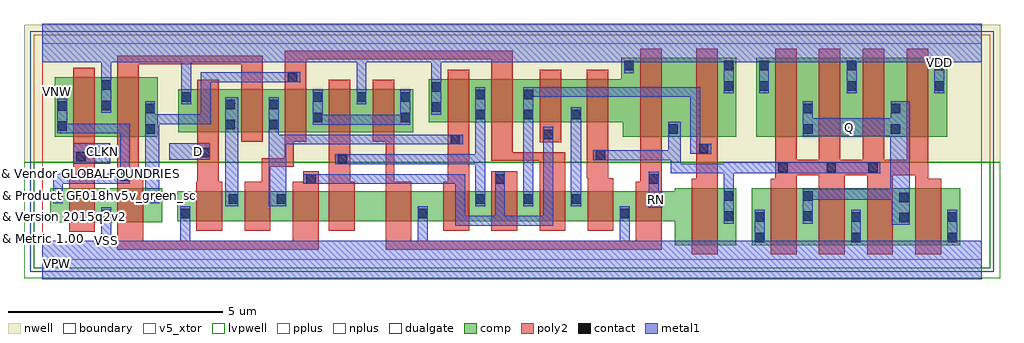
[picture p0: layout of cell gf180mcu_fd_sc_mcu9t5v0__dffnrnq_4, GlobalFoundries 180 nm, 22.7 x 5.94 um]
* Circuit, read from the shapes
.subckt gf180mcu_fd_sc_mcu9t5v0__dffnrnq_4 CLKN D Q RN VDD VNW VSS
XM1 VSS CLKN n1 VSUBS nfet_05v0 w=0.79u l=0.6u
XM2 n2 n1 VSS VSUBS nfet_05v0 w=0.79u l=0.6u
XM3 n3 D VSS VSUBS nfet_05v0 w=0.7u l=0.6u
XM4 n4 n2 n3 VSUBS nfet_05v0 w=0.7u l=0.6u
XM5 n5 n1 n4 VSUBS nfet_05v0 w=0.7u l=0.6u
XM6 n6 n7 n5 VSUBS nfet_05v0 w=0.7u l=0.6u
XM7 VSS RN n6 VSUBS nfet_05v0 w=0.7u l=0.6u
XM8 n7 n4 VSS VSUBS nfet_05v0 w=0.7u l=0.6u
XM9 n8 n1 n7 VSUBS nfet_05v0 w=0.7u l=0.6u
XM10 n9 n2 n8 VSUBS nfet_05v0 w=0.7u l=0.6u
XM11 VSS n10 n9 VSUBS nfet_05v0 w=0.7u l=0.6u
XM12 n11 RN VSS VSUBS nfet_05v0 w=0.7u l=0.6u
XM13 n10 n8 n11 VSUBS nfet_05v0 w=1.32u l=0.6u
XM14 Q n10 VSS VSUBS nfet_05v0 w=1.32u l=0.6u m=4
XM15 VDD CLKN n1 VNW pfet_05v0 w=1.38u l=0.5u
XM16 n2 n1 VDD VNW pfet_05v0 w=1.38u l=0.5u
XM17 n3 D VDD VNW pfet_05v0 w=1u l=0.5u
XM18 n4 n1 n3 VNW pfet_05v0 w=1u l=0.5u
XM19 n12 n2 n4 VNW pfet_05v0 w=1u l=0.5u
XM20 VDD n7 n12 VNW pfet_05v0 w=1u l=0.5u
XM21 n12 RN VDD VNW pfet_05v0 w=1u l=0.5u
XM22 n7 n4 VDD VNW pfet_05v0 w=1u l=0.5u
XM23 n8 n2 n7 VNW pfet_05v0 w=1u l=0.5u
XM24 n9 n1 n8 VNW pfet_05v0 w=1u l=0.5u
XM25 VDD n10 n9 VNW pfet_05v0 w=1u l=0.5u
XM26 n10 RN VDD VNW pfet_05v0 w=1.83u l=0.5u
XM27 VDD n8 n10 VNW pfet_05v0 w=1.83u l=0.5u
XM28 Q n10 VDD VNW pfet_05v0 w=1.83u l=0.5u m=4
.ends

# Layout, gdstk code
import gdstk
lib = gdstk.Library(unit=1e-6, precision=1e-09)
def R(c, l, rs):  # rectangles x0, y0, x1, y1
    for r in rs: c.add(gdstk.rectangle(r[:2], r[2:], *l))
def A(c, l, x, y, w, h, nx, ny, dx, dy):  # array of equal rectangles
    R(c, l, [(x+i*dx, y+j*dy, x+i*dx+w, y+j*dy+h) for i in range(nx) for j in range(ny)])
def P(c, l, *ps):  # polygons
    for p in ps: c.add(gdstk.Polygon(p, *l))
boundary = (0, 0)
nwell = (21, 0)
comp = (22, 0)
poly2 = (30, 0)
pplus = (31, 0)
nplus = (32, 0)
contact = (33, 0)
metal1 = (34, 0)
dualgate = (55, 0)
v5_xtor = (112, 1)
lvpwell = (204, 0)

gf180mcu_fd_sc_mcu9t5v0_ = lib.new_cell('gf180mcu_fd_sc_mcu9t5v0__dffnrnq_4')
R(gf180mcu_fd_sc_mcu9t5v0_, boundary, [(0,0,21.84,5.04)])
R(gf180mcu_fd_sc_mcu9t5v0_, nwell, [(-0.43,2.265,22.27,5.47)])
R(gf180mcu_fd_sc_mcu9t5v0_, comp, [(16.5,0.345,21.34,1.665), (0.18,0.875,2.78,1.665), (0.28,2.865,2.68,4.245), (16.6,2.865,21.04,4.695), (3.16,2.965,8.62,3.965)])
P(gf180mcu_fd_sc_mcu9t5v0_, comp, [(14.7,0.345),(14.7,0.9),(3.14,0.9),(3.14,1.6),(14.7,1.6),(14.7,1.665),(16.14,1.665),(16.14,0.345)],
  [(13.5,2.865),(13.5,3.2),(8.98,3.2),(8.98,4.2),(13.46,4.2),(13.46,4.695),(16.14,4.695),(16.14,2.865)])
R(gf180mcu_fd_sc_mcu9t5v0_, poly2, [(10.44,0.68,11.04,2.06), (11.565,2.74,12.065,4.42)])
P(gf180mcu_fd_sc_mcu9t5v0_, poly2, [(0.62,0.655),(0.62,1.885),(0.72,1.885),(0.72,4.465),(1.22,4.465),(1.22,0.655)],
  [(3.58,0.68),(3.58,1.82),(3.6,1.82),(3.6,4.185),(4.1,4.185),(4.1,1.82),(4.18,1.82),(4.18,0.68)],
  [(1.74,0.24),(1.74,4.745),(5.12,4.745),(5.12,2.745),(4.62,2.745),(4.62,4.545),(2.24,4.545),(2.24,1.885),(2.34,1.885),(2.34,0.44),(5.82,0.44),(5.82,1.82),(6.06,1.82),(6.06,2.06),(6.42,2.06),(6.42,0.24)],
  [(6.66,0.68),(6.66,4.185),(7.16,4.185),(7.16,1.82),(7.26,1.82),(7.26,0.68)],
  [(9.32,0.68),(9.32,1.82),(9.42,1.82),(9.42,4.42),(9.92,4.42),(9.92,0.68)],
  [(4.7,0.68),(4.7,1.82),(5.1,1.82),(5.1,2.36),(5.64,2.36),(5.64,4.86),(10.94,4.86),(10.94,2.5),(12.16,2.5),(12.16,0.68),(11.56,0.68),(11.56,2.3),(10.44,2.3),(10.44,4.66),(6.14,4.66),(6.14,2.745),(5.84,2.745),(5.84,2.16),(5.3,2.16),(5.3,0.68)],
  [(12.68,0.68),(12.68,1.9),(12.66,1.9),(12.66,4.42),(13.16,4.42),(13.16,1.9),(13.28,1.9),(13.28,0.68)],
  [(7.98,0.24),(7.98,2.745),(7.68,2.745),(7.68,4.185),(8.18,4.185),(8.18,1.82),(8.58,1.82),(8.58,0.44),(13.8,0.44),(13.8,1.82),(13.9,1.82),(13.9,4.915),(14.4,4.915),(14.4,0.24)],
  [(15.1,0.125),(15.1,1.885),(15.2,1.885),(15.2,4.915),(15.7,4.915),(15.7,0.125)],
  [(16.94,0.125),(16.94,1.885),(17.04,1.885),(17.04,4.915),(17.54,4.915),(17.54,2.325),(18.06,2.325),(18.06,4.915),(18.56,4.915),(18.56,2.325),(19.08,2.325),(19.08,4.915),(19.58,4.915),(19.58,2.325),(20.1,2.325),(20.1,4.915),(20.6,4.915),(20.6,1.885),(20.9,1.885),(20.9,0.125),(20.3,0.125),(20.3,1.965),(19.78,1.965),(19.78,0.125),(19.18,0.125),(19.18,1.965),(18.66,1.965),(18.66,0.125),(18.06,0.125),(18.06,1.965),(17.54,1.965),(17.54,0.125)])
R(gf180mcu_fd_sc_mcu9t5v0_, pplus, [(-0.2,2.265,22.04,5.24)])
R(gf180mcu_fd_sc_mcu9t5v0_, nplus, [(-0.2,-0.2,22.04,2.265)])
A(gf180mcu_fd_sc_mcu9t5v0_, contact, 16.57, 0.415, 0.22, 0.22, 3, 2, 2.24, 0.47)
A(gf180mcu_fd_sc_mcu9t5v0_, contact, 10.07, 1.31, 0.22, 0.22, 3, 1, 1.12, 0)
A(gf180mcu_fd_sc_mcu9t5v0_, contact, 6.29, 3.675, 0.22, 0.22, 3, 1, 1.02, 0)
A(gf180mcu_fd_sc_mcu9t5v0_, contact, 16.67, 3.935, 0.22, 0.22, 3, 2, 2.04, 0.47)
R(gf180mcu_fd_sc_mcu9t5v0_, contact, [(19.93,0.875,20.15,1.095), (15.85,0.905,16.07,1.125), (17.69,0.905,17.91,1.125), (1.37,0.945,1.59,1.165), (3.21,0.97,3.43,1.19), (8.73,0.97,8.95,1.19), (13.43,0.97,13.65,1.19), (4.33,1.31,4.55,1.53), (5.45,1.31,5.67,1.53), (19.93,1.345,20.15,1.565), (0.25,1.375,0.47,1.595), (2.49,1.375,2.71,1.595), (15.85,1.375,16.07,1.595), (17.69,1.375,17.91,1.595), (6.13,1.77,6.35,1.99), (10.53,1.77,10.75,1.99), (14.11,1.77,14.33,1.99), (1.81,1.835,2.03,2.055), (17.11,2.035,17.33,2.255), (18.235,2.035,18.455,2.255), (19.205,2.035,19.425,2.255), (6.87,2.23,7.09,2.45), (0.79,2.295,1.01,2.515), (12.87,2.325,13.09,2.545), (3.67,2.39,3.89,2.61), (15.27,2.475,15.49,2.695), (9.49,2.69,9.71,2.91), (11.65,2.81,11.87,3.03), (2.39,2.935,2.61,3.155), (14.56,2.935,14.78,3.155), (17.69,2.935,17.91,3.155), (19.73,2.935,19.95,3.155), (0.35,3,0.57,3.22), (4.25,3.035,4.47,3.255), (5.27,3.035,5.49,3.255), (6.29,3.205,6.51,3.425), (8.33,3.205,8.55,3.425), (10.07,3.27,10.29,3.49), (11.195,3.27,11.415,3.49), (12.29,3.27,12.51,3.49), (2.39,3.405,2.61,3.625), (17.69,3.405,17.91,3.625), (19.73,3.405,19.95,3.625), (9.05,3.44,9.27,3.66), (0.35,3.47,0.57,3.69), (1.37,3.485,1.59,3.705), (4.25,3.505,4.47,3.725), (5.27,3.505,5.49,3.725), (3.23,3.675,3.45,3.895), (10.07,3.74,10.29,3.96), (11.195,3.74,11.415,3.96), (9.05,3.91,9.27,4.13), (15.85,3.935,16.07,4.155), (1.37,3.955,1.59,4.175), (5.71,4.135,5.93,4.355), (13.53,4.405,13.75,4.625), (15.85,4.405,16.07,4.625)])
R(gf180mcu_fd_sc_mcu9t5v0_, metal1, [(4.245,1.25,4.555,3.785), (12.285,1.25,12.535,3.55), (0.71,2.235,1.575,2.71), (2.945,2.33,3.895,2.71)])
P(gf180mcu_fd_sc_mcu9t5v0_, metal1, [(0.245,1.315),(0.245,2.005),(1.805,2.005),(1.805,2.94),(0.345,2.94),(0.345,3.75),(0.575,3.75),(0.575,3.17),(2.035,3.17),(2.035,1.775),(0.475,1.775),(0.475,1.315)],
  [(2.385,1.315),(2.385,3.685),(2.615,3.685),(2.615,3.385),(3.685,3.385),(3.685,4.36),(5.99,4.36),(5.99,4.13),(3.915,4.13),(3.915,3.155),(2.715,3.155),(2.715,1.315)],
  [(6.285,3.145),(6.285,3.955),(6.515,3.955),(6.515,3.375),(8.325,3.375),(8.325,3.955),(8.555,3.955),(8.555,3.145)],
  [(5.265,1.25),(5.265,3.785),(5.495,3.785),(5.495,2.915),(9.77,2.915),(9.77,2.685),(5.675,2.685),(5.675,1.25)],
  [(10.065,1.25),(10.065,2.225),(6.81,2.225),(6.81,2.455),(10.065,2.455),(10.065,4.02),(10.295,4.02),(10.295,1.25)],
  [(9.605,0.79),(9.605,1.765),(6.07,1.765),(6.07,1.995),(9.835,1.995),(9.835,1.02),(10.525,1.02),(10.525,2.05),(10.755,2.05),(10.755,1.02),(11.645,1.02),(11.645,3.09),(11.875,3.09),(11.875,0.79)],
  [(14.105,1.21),(14.105,2.05),(14.335,2.05),(14.335,1.59),(14.41,1.59),(14.41,1.21)],
  [(11.185,1.25),(11.185,4.02),(15.3,4.02),(15.3,2.7),(15.55,2.7),(15.55,2.47),(15.07,2.47),(15.07,3.79),(11.42,3.79),(11.42,3.21),(11.415,3.21),(11.415,1.25)],
  [(15.845,0.845),(15.845,2.01),(14.61,2.01),(14.61,2.32),(12.81,2.32),(12.81,2.55),(14.555,2.55),(14.555,3.215),(14.84,3.215),(14.84,2.24),(15.845,2.24),(15.845,2.275),(19.485,2.275),(19.485,2.015),(16.075,2.015),(16.075,0.845)],
  [(19.75,0.815),(19.75,1.395),(17.915,1.395),(17.915,0.845),(17.685,0.845),(17.685,1.655),(19.715,1.655),(19.715,2.875),(17.685,2.875),(17.685,3.685),(17.915,3.685),(17.915,3.295),(19.725,3.295),(19.725,3.685),(20.175,3.685),(20.175,0.815)],
  [(0,-0.45),(0,0.45),(1.365,0.45),(1.365,1.225),(1.595,1.225),(1.595,0.45),(3.205,0.45),(3.205,1.25),(3.435,1.25),(3.435,0.45),(8.725,0.45),(8.725,1.25),(8.955,1.25),(8.955,0.45),(13.425,0.45),(13.425,1.25),(13.655,1.25),(13.655,0.45),(16.565,0.45),(16.565,1.165),(16.795,1.165),(16.795,0.45),(18.805,0.45),(18.805,1.165),(19.035,1.165),(19.035,0.45),(21.045,0.45),(21.045,1.165),(21.275,1.165),(21.275,0.45),(21.84,0.45),(21.84,-0.45)],
  [(9.045,3.38),(9.045,4.59),(7.535,4.59),(7.535,3.615),(7.305,3.615),(7.305,4.59),(3.455,4.59),(3.455,3.615),(3.225,3.615),(3.225,4.59),(1.595,4.59),(1.595,3.425),(1.365,3.425),(1.365,4.59),(0,4.59),(0,5.49),(21.84,5.49),(21.84,4.59),(20.975,4.59),(20.975,3.875),(20.745,3.875),(20.745,4.59),(18.935,4.59),(18.935,3.875),(18.705,3.875),(18.705,4.59),(16.895,4.59),(16.895,3.875),(16.665,3.875),(16.665,4.59),(16.075,4.59),(16.075,3.875),(15.845,3.875),(15.845,4.59),(13.755,4.59),(13.755,4.345),(13.525,4.345),(13.525,4.59),(9.275,4.59),(9.275,3.38)])
R(gf180mcu_fd_sc_mcu9t5v0_, dualgate, [(-0.28,-0.28,22.12,5.32)])
R(gf180mcu_fd_sc_mcu9t5v0_, v5_xtor, [(0,0,21.84,5.04)])
R(gf180mcu_fd_sc_mcu9t5v0_, lvpwell, [(-0.43,-0.43,22.27,2.265)])
gf180mcu_fd_sc_mcu9t5v0_.add(gdstk.Label('CLKN', (1.4,2.52), layer=34, texttype=10))
gf180mcu_fd_sc_mcu9t5v0_.add(gdstk.Label('D', (3.64,2.52), layer=34, texttype=10))
gf180mcu_fd_sc_mcu9t5v0_.add(gdstk.Label('Q', (18.76,3.08), layer=34, texttype=10))
gf180mcu_fd_sc_mcu9t5v0_.add(gdstk.Label('RN', (14.28,1.4), layer=34, texttype=10))
gf180mcu_fd_sc_mcu9t5v0_.add(gdstk.Label('VDD', (20.86,4.59), layer=34, texttype=10))
gf180mcu_fd_sc_mcu9t5v0_.add(gdstk.Label('VSS', (1.48,0.45), layer=34, texttype=10))
gf180mcu_fd_sc_mcu9t5v0_.add(gdstk.Label('& Vendor GLOBALFOUNDRIES', (0,2), layer=63, texttype=63))
gf180mcu_fd_sc_mcu9t5v0_.add(gdstk.Label('& Product GF018hv5v_green_sc9', (0,1.5), layer=63, texttype=63))
gf180mcu_fd_sc_mcu9t5v0_.add(gdstk.Label('& Version 2015q2v2', (0,1), layer=63, texttype=63))
gf180mcu_fd_sc_mcu9t5v0_.add(gdstk.Label('& Metric 1.00', (0,0.5), layer=63, texttype=63))
gf180mcu_fd_sc_mcu9t5v0_.add(gdstk.Label('VNW', (0.345,3.92), layer=21, texttype=10))
gf180mcu_fd_sc_mcu9t5v0_.add(gdstk.Label('VPW', (0.34,-0.085), layer=204, texttype=10))

lib.write_gds('gf180mcu_fd_sc_mcu9t5v0__dffnrnq_4.gds')
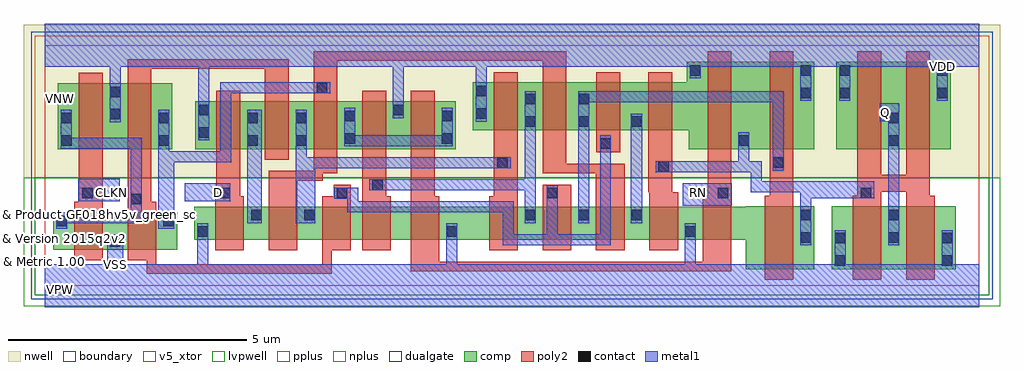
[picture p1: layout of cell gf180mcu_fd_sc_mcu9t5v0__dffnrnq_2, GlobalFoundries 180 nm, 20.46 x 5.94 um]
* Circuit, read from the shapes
.subckt gf180mcu_fd_sc_mcu9t5v0__dffnrnq_2 CLKN D Q RN VDD VNW VSS
XM1 VSS CLKN n1 VSUBS nfet_05v0 w=0.79u l=0.6u
XM2 n2 n1 VSS VSUBS nfet_05v0 w=0.79u l=0.6u
XM3 n3 D VSS VSUBS nfet_05v0 w=0.7u l=0.6u
XM4 n4 n2 n3 VSUBS nfet_05v0 w=0.7u l=0.6u
XM5 n5 n1 n4 VSUBS nfet_05v0 w=0.7u l=0.6u
XM6 n6 n7 n5 VSUBS nfet_05v0 w=0.7u l=0.6u
XM7 VSS RN n6 VSUBS nfet_05v0 w=0.7u l=0.6u
XM8 n7 n4 VSS VSUBS nfet_05v0 w=0.7u l=0.6u
XM9 n8 n1 n7 VSUBS nfet_05v0 w=0.7u l=0.6u
XM10 n9 n2 n8 VSUBS nfet_05v0 w=0.7u l=0.6u
XM11 VSS n10 n9 VSUBS nfet_05v0 w=0.7u l=0.6u
XM12 n11 RN VSS VSUBS nfet_05v0 w=0.7u l=0.6u
XM13 n10 n8 n11 VSUBS nfet_05v0 w=1.32u l=0.6u
XM14 Q n10 VSS VSUBS nfet_05v0 w=1.32u l=0.6u m=2
XM15 VDD CLKN n1 VNW pfet_05v0 w=1.38u l=0.5u
XM16 n2 n1 VDD VNW pfet_05v0 w=1.38u l=0.5u
XM17 n3 D VDD VNW pfet_05v0 w=1u l=0.5u
XM18 n4 n1 n3 VNW pfet_05v0 w=1u l=0.5u
XM19 n12 n2 n4 VNW pfet_05v0 w=1u l=0.5u
XM20 VDD n7 n12 VNW pfet_05v0 w=1u l=0.5u
XM21 n12 RN VDD VNW pfet_05v0 w=1u l=0.5u
XM22 n7 n4 VDD VNW pfet_05v0 w=1u l=0.5u
XM23 n8 n2 n7 VNW pfet_05v0 w=1u l=0.5u
XM24 n9 n1 n8 VNW pfet_05v0 w=1u l=0.5u
XM25 VDD n10 n9 VNW pfet_05v0 w=1u l=0.5u
XM26 n10 RN VDD VNW pfet_05v0 w=1.83u l=0.5u
XM27 VDD n8 n10 VNW pfet_05v0 w=1.83u l=0.5u
XM28 Q n10 VDD VNW pfet_05v0 w=1.83u l=0.5u m=2
.ends

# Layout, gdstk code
import gdstk
lib = gdstk.Library(unit=1e-6, precision=1e-09)
def R(c, l, rs):  # rectangles x0, y0, x1, y1
    for r in rs: c.add(gdstk.rectangle(r[:2], r[2:], *l))
def A(c, l, x, y, w, h, nx, ny, dx, dy):  # array of equal rectangles
    R(c, l, [(x+i*dx, y+j*dy, x+i*dx+w, y+j*dy+h) for i in range(nx) for j in range(ny)])
def P(c, l, *ps):  # polygons
    for p in ps: c.add(gdstk.Polygon(p, *l))
boundary = (0, 0)
nwell = (21, 0)
comp = (22, 0)
poly2 = (30, 0)
pplus = (31, 0)
nplus = (32, 0)
contact = (33, 0)
metal1 = (34, 0)
dualgate = (55, 0)
v5_xtor = (112, 1)
lvpwell = (204, 0)

gf180mcu_fd_sc_mcu9t5v0_ = lib.new_cell('gf180mcu_fd_sc_mcu9t5v0__dffnrnq_2')
R(gf180mcu_fd_sc_mcu9t5v0_, boundary, [(0,0,19.6,5.04)])
R(gf180mcu_fd_sc_mcu9t5v0_, nwell, [(-0.43,2.265,20.03,5.47)])
R(gf180mcu_fd_sc_mcu9t5v0_, comp, [(16.5,0.345,19.1,1.665), (0.18,0.75,2.78,1.54), (0.28,2.865,2.68,4.245), (3.16,2.865,8.62,3.865), (16.6,2.865,19,4.695)])
P(gf180mcu_fd_sc_mcu9t5v0_, comp, [(14.7,0.345),(14.7,0.96),(3.14,0.96),(3.14,1.66),(14.7,1.66),(14.7,1.665),(16.14,1.665),(16.14,0.345)],
  [(13.5,2.865),(13.5,3.26),(8.98,3.26),(8.98,4.26),(13.46,4.26),(13.46,4.695),(16.14,4.695),(16.14,2.865)])
R(gf180mcu_fd_sc_mcu9t5v0_, poly2, [(10.44,0.74,11.04,2.12), (11.565,2.8,12.065,4.48)])
P(gf180mcu_fd_sc_mcu9t5v0_, poly2, [(0.62,0.53),(0.62,1.76),(0.72,1.76),(0.72,4.465),(1.22,4.465),(1.22,0.53)],
  [(3.58,0.74),(3.58,1.88),(3.6,1.88),(3.6,4.085),(4.1,4.085),(4.1,1.88),(4.18,1.88),(4.18,0.74)],
  [(2.14,0.25),(2.14,0.53),(1.74,0.53),(1.74,4.745),(5.12,4.745),(5.12,2.645),(4.62,2.645),(4.62,4.545),(2.24,4.545),(2.24,1.76),(2.34,1.76),(2.34,0.45),(5.82,0.45),(5.82,1.88),(6.06,1.88),(6.06,2.12),(6.42,2.12),(6.42,0.74),(6.02,0.74),(6.02,0.25)],
  [(6.66,0.74),(6.66,4.085),(7.16,4.085),(7.16,1.88),(7.26,1.88),(7.26,0.74)],
  [(9.32,0.74),(9.32,1.88),(9.42,1.88),(9.42,4.48),(9.92,4.48),(9.92,0.74)],
  [(4.7,0.74),(4.7,2.405),(5.64,2.405),(5.64,4.325),(5.645,4.325),(5.645,4.92),(10.94,4.92),(10.94,2.56),(12.16,2.56),(12.16,0.74),(11.56,0.74),(11.56,2.36),(10.44,2.36),(10.44,4.72),(6.14,4.72),(6.14,2.36),(5.835,2.36),(5.835,2.205),(5.3,2.205),(5.3,0.74)],
  [(12.68,0.74),(12.68,1.96),(12.66,1.96),(12.66,4.48),(13.16,4.48),(13.16,1.96),(13.28,1.96),(13.28,0.74)],
  [(7.68,0.3),(7.68,4.085),(8.18,4.085),(8.18,1.88),(8.28,1.88),(8.28,0.5),(13.8,0.5),(13.8,1.88),(13.9,1.88),(13.9,4.915),(14.4,4.915),(14.4,0.3)],
  [(15.1,0.125),(15.1,1.885),(15.2,1.885),(15.2,4.915),(15.7,4.915),(15.7,0.125)],
  [(16.94,0.125),(16.94,1.885),(17.04,1.885),(17.04,4.915),(17.54,4.915),(17.54,2.325),(18.06,2.325),(18.06,4.915),(18.56,4.915),(18.56,1.885),(18.66,1.885),(18.66,0.125),(18.06,0.125),(18.06,1.965),(17.54,1.965),(17.54,0.125)])
R(gf180mcu_fd_sc_mcu9t5v0_, pplus, [(-0.2,2.265,19.8,5.24)])
R(gf180mcu_fd_sc_mcu9t5v0_, nplus, [(-0.2,-0.2,19.8,2.265)])
A(gf180mcu_fd_sc_mcu9t5v0_, contact, 10.07, 1.37, 0.22, 0.22, 3, 1, 1.12, 0)
R(gf180mcu_fd_sc_mcu9t5v0_, contact, [(16.57,0.415,16.79,0.635), (18.81,0.415,19.03,0.635), (1.37,0.82,1.59,1.04), (16.57,0.885,16.79,1.105), (18.81,0.885,19.03,1.105), (15.85,0.905,16.07,1.125), (17.69,0.905,17.91,1.125), (3.21,1.03,3.43,1.25), (8.43,1.03,8.65,1.25), (13.43,1.03,13.65,1.25), (0.25,1.25,0.47,1.47), (2.49,1.25,2.71,1.47), (4.33,1.37,4.55,1.59), (5.45,1.37,5.67,1.59), (15.85,1.375,16.07,1.595), (17.69,1.375,17.91,1.595), (1.81,1.71,2.03,1.93), (0.79,1.83,1.01,2.05), (3.67,1.83,3.89,2.05), (6.13,1.83,6.35,2.05), (10.53,1.83,10.75,2.05), (14.11,1.83,14.33,2.05), (17.11,1.835,17.33,2.055), (6.87,2.005,7.09,2.225), (12.87,2.385,13.09,2.605), (9.49,2.465,9.71,2.685), (15.27,2.475,15.49,2.695), (11.65,2.87,11.87,3.09), (0.35,2.935,0.57,3.155), (2.39,2.935,2.61,3.155), (4.25,2.935,4.47,3.155), (5.27,2.935,5.49,3.155), (14.55,2.935,14.77,3.155), (17.69,2.935,17.91,3.155), (6.29,2.98,6.51,3.2), (8.33,2.98,8.55,3.2), (3.23,3.105,3.45,3.325), (10.07,3.33,10.29,3.55), (11.195,3.33,11.415,3.55), (12.29,3.33,12.51,3.55), (0.35,3.405,0.57,3.625), (2.39,3.405,2.61,3.625), (4.25,3.405,4.47,3.625), (5.27,3.405,5.49,3.625), (17.69,3.405,17.91,3.625), (6.29,3.45,6.51,3.67), (8.33,3.45,8.55,3.67), (1.37,3.485,1.59,3.705), (9.05,3.5,9.27,3.72), (3.23,3.575,3.45,3.795), (7.31,3.575,7.53,3.795), (10.07,3.8,10.29,4.02), (11.195,3.8,11.415,4.02), (15.85,3.935,16.07,4.155), (16.67,3.935,16.89,4.155), (18.71,3.935,18.93,4.155), (1.37,3.955,1.59,4.175), (9.05,3.97,9.27,4.19), (5.71,4.035,5.93,4.255), (13.53,4.405,13.75,4.625), (15.85,4.405,16.07,4.625), (16.67,4.405,16.89,4.625), (18.71,4.405,18.93,4.625)])
R(gf180mcu_fd_sc_mcu9t5v0_, metal1, [(4.245,1.31,4.555,3.685), (12.285,1.31,12.535,3.61), (13.38,1.675,14.41,2.15), (0.71,1.77,1.575,2.245), (2.945,1.77,3.895,2.15)])
P(gf180mcu_fd_sc_mcu9t5v0_, metal1, [(0.245,1.19),(0.245,1.54),(1.805,1.54),(1.805,2.875),(0.345,2.875),(0.345,3.685),(0.575,3.685),(0.575,3.105),(2.035,3.105),(2.035,1.31),(0.475,1.31),(0.475,1.19)],
  [(2.385,1.19),(2.385,3.685),(2.615,3.685),(2.615,2.815),(3.685,2.815),(3.685,4.26),(5.99,4.26),(5.99,4.03),(3.915,4.03),(3.915,2.585),(2.715,2.585),(2.715,1.19)],
  [(6.285,2.92),(6.285,3.73),(6.515,3.73),(6.515,3.15),(8.325,3.15),(8.325,3.73),(8.555,3.73),(8.555,2.92)],
  [(5.265,1.31),(5.265,3.685),(5.495,3.685),(5.495,2.69),(9.77,2.69),(9.77,2.46),(5.675,2.46),(5.675,1.31)],
  [(10.065,1.31),(10.065,2),(6.81,2),(6.81,2.23),(10.065,2.23),(10.065,4.08),(10.295,4.08),(10.295,1.31)],
  [(9.605,0.85),(9.605,1.54),(6.35,1.54),(6.35,1.825),(6.07,1.825),(6.07,2.055),(6.58,2.055),(6.58,1.77),(9.835,1.77),(9.835,1.08),(10.525,1.08),(10.525,2.11),(10.755,2.11),(10.755,1.08),(11.645,1.08),(11.645,3.15),(11.875,3.15),(11.875,0.85)],
  [(11.185,1.31),(11.185,4.08),(15.495,4.08),(15.495,2.415),(15.265,2.415),(15.265,3.85),(11.42,3.85),(11.42,3.27),(11.415,3.27),(11.415,1.31)],
  [(15.845,0.845),(15.845,1.955),(14.805,1.955),(14.805,2.38),(12.81,2.38),(12.81,2.61),(14.545,2.61),(14.545,3.215),(14.775,3.215),(14.775,2.61),(15.035,2.61),(15.035,2.185),(17.39,2.185),(17.39,1.83),(16.075,1.83),(16.075,0.845)],
  [(17.685,0.845),(17.685,3.45),(17.51,3.45),(17.51,3.83),(17.915,3.83),(17.915,0.845)],
  [(0,-0.45),(0,0.45),(1.31,0.45),(1.31,1.08),(1.65,1.08),(1.65,0.45),(3.205,0.45),(3.205,1.31),(3.435,1.31),(3.435,0.45),(8.425,0.45),(8.425,1.31),(8.655,1.31),(8.655,0.45),(13.425,0.45),(13.425,1.31),(13.655,1.31),(13.655,0.45),(16.565,0.45),(16.565,1.165),(16.795,1.165),(16.795,0.45),(18.805,0.45),(18.805,1.165),(19.035,1.165),(19.035,0.45),(19.6,0.45),(19.6,-0.45)],
  [(3.225,3.045),(3.225,4.59),(1.595,4.59),(1.595,3.425),(1.365,3.425),(1.365,4.59),(0,4.59),(0,5.49),(19.6,5.49),(19.6,4.59),(18.935,4.59),(18.935,3.875),(18.705,3.875),(18.705,4.59),(16.895,4.59),(16.895,3.875),(16.665,3.875),(16.665,4.59),(16.075,4.59),(16.075,3.875),(15.845,3.875),(15.845,4.59),(13.755,4.59),(13.755,4.345),(13.525,4.345),(13.525,4.59),(9.275,4.59),(9.275,3.44),(9.045,3.44),(9.045,4.59),(7.535,4.59),(7.535,3.515),(7.305,3.515),(7.305,4.59),(3.455,4.59),(3.455,3.045)])
R(gf180mcu_fd_sc_mcu9t5v0_, dualgate, [(-0.28,-0.28,19.88,5.32)])
R(gf180mcu_fd_sc_mcu9t5v0_, v5_xtor, [(0,0,19.6,5.04)])
R(gf180mcu_fd_sc_mcu9t5v0_, lvpwell, [(-0.43,-0.43,20.03,2.265)])
gf180mcu_fd_sc_mcu9t5v0_.add(gdstk.Label('CLKN', (1.4,1.96), layer=34, texttype=10))
gf180mcu_fd_sc_mcu9t5v0_.add(gdstk.Label('D', (3.64,1.96), layer=34, texttype=10))
gf180mcu_fd_sc_mcu9t5v0_.add(gdstk.Label('Q', (17.64,3.64), layer=34, texttype=10))
gf180mcu_fd_sc_mcu9t5v0_.add(gdstk.Label('RN', (13.72,1.96), layer=34, texttype=10))
gf180mcu_fd_sc_mcu9t5v0_.add(gdstk.Label('VDD', (18.82,4.59), layer=34, texttype=10))
gf180mcu_fd_sc_mcu9t5v0_.add(gdstk.Label('VSS', (1.48,0.45), layer=34, texttype=10))
gf180mcu_fd_sc_mcu9t5v0_.add(gdstk.Label('& Vendor GLOBALFOUNDRIES', (0,2), layer=63, texttype=63))
gf180mcu_fd_sc_mcu9t5v0_.add(gdstk.Label('& Product GF018hv5v_green_sc9', (0,1.5), layer=63, texttype=63))
gf180mcu_fd_sc_mcu9t5v0_.add(gdstk.Label('& Version 2015q2v2', (0,1), layer=63, texttype=63))
gf180mcu_fd_sc_mcu9t5v0_.add(gdstk.Label('& Metric 1.00', (0,0.5), layer=63, texttype=63))
gf180mcu_fd_sc_mcu9t5v0_.add(gdstk.Label('VNW', (0.345,3.92), layer=21, texttype=10))
gf180mcu_fd_sc_mcu9t5v0_.add(gdstk.Label('VPW', (0.34,-0.085), layer=204, texttype=10))

lib.write_gds('gf180mcu_fd_sc_mcu9t5v0__dffnrnq_2.gds')
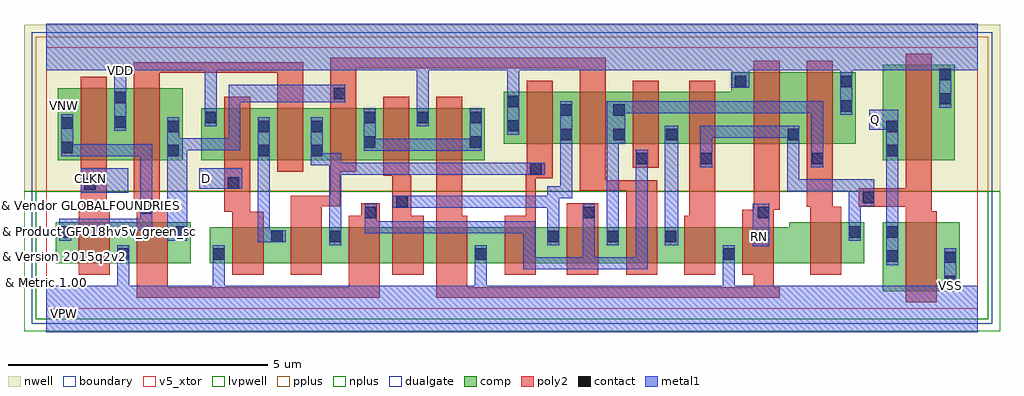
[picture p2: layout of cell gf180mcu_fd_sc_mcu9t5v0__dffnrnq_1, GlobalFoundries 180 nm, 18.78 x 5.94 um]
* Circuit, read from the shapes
.subckt gf180mcu_fd_sc_mcu9t5v0__dffnrnq_1 CLKN D Q RN VDD VNW VSS
XM1 VSS CLKN n1 VSUBS nfet_05v0 w=0.79u l=0.6u
XM2 n2 n1 VSS VSUBS nfet_05v0 w=0.79u l=0.6u
XM3 n3 D VSS VSUBS nfet_05v0 w=0.7u l=0.6u
XM4 n4 n2 n3 VSUBS nfet_05v0 w=0.7u l=0.6u
XM5 n5 n1 n4 VSUBS nfet_05v0 w=0.7u l=0.6u
XM6 n6 n7 n5 VSUBS nfet_05v0 w=0.7u l=0.6u
XM7 VSS RN n6 VSUBS nfet_05v0 w=0.7u l=0.6u
XM8 n7 n4 VSS VSUBS nfet_05v0 w=0.7u l=0.6u
XM9 n8 n1 n7 VSUBS nfet_05v0 w=0.7u l=0.6u
XM10 n9 n2 n8 VSUBS nfet_05v0 w=0.7u l=0.6u
XM11 VSS n10 n9 VSUBS nfet_05v0 w=0.7u l=0.6u
XM12 n11 RN VSS VSUBS nfet_05v0 w=0.7u l=0.6u
XM13 n10 n8 n11 VSUBS nfet_05v0 w=0.79u l=0.6u
XM14 VSS n10 Q VSUBS nfet_05v0 w=1.32u l=0.6u
XM15 VDD CLKN n1 VNW pfet_05v0 w=1.38u l=0.5u
XM16 n2 n1 VDD VNW pfet_05v0 w=1.38u l=0.5u
XM17 n3 D VDD VNW pfet_05v0 w=1u l=0.5u
XM18 n4 n1 n3 VNW pfet_05v0 w=1u l=0.5u
XM19 n12 n2 n4 VNW pfet_05v0 w=1u l=0.5u
XM20 VDD n7 n12 VNW pfet_05v0 w=1u l=0.5u
XM21 n12 RN VDD VNW pfet_05v0 w=1u l=0.5u
XM22 n7 n4 VDD VNW pfet_05v0 w=1u l=0.5u
XM23 n8 n2 n7 VNW pfet_05v0 w=1u l=0.5u
XM24 n9 n1 n8 VNW pfet_05v0 w=1u l=0.5u
XM25 VDD n10 n9 VNW pfet_05v0 w=1u l=0.5u
XM26 n10 RN VDD VNW pfet_05v0 w=1.38u l=0.5u
XM27 VDD n8 n10 VNW pfet_05v0 w=1.38u l=0.5u
XM28 VDD n10 Q VNW pfet_05v0 w=1.83u l=0.5u
.ends

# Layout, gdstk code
import gdstk
lib = gdstk.Library(unit=1e-6, precision=1e-09)
def R(c, l, rs):  # rectangles x0, y0, x1, y1
    for r in rs: c.add(gdstk.rectangle(r[:2], r[2:], *l))
def A(c, l, x, y, w, h, nx, ny, dx, dy):  # array of equal rectangles
    R(c, l, [(x+i*dx, y+j*dy, x+i*dx+w, y+j*dy+h) for i in range(nx) for j in range(ny)])
def P(c, l, *ps):  # polygons
    for p in ps: c.add(gdstk.Polygon(p, *l))
boundary = (0, 0)
nwell = (21, 0)
comp = (22, 0)
poly2 = (30, 0)
pplus = (31, 0)
nplus = (32, 0)
contact = (33, 0)
metal1 = (34, 0)
dualgate = (55, 0)
v5_xtor = (112, 1)
lvpwell = (204, 0)

gf180mcu_fd_sc_mcu9t5v0_ = lib.new_cell('gf180mcu_fd_sc_mcu9t5v0__dffnrnq_1')
R(gf180mcu_fd_sc_mcu9t5v0_, boundary, [(0,0,17.92,5.04)])
R(gf180mcu_fd_sc_mcu9t5v0_, nwell, [(-0.43,2.265,18.35,5.47)])
R(gf180mcu_fd_sc_mcu9t5v0_, comp, [(16.095,0.345,17.575,1.665), (0.18,0.875,2.78,1.665), (0.22,2.865,2.62,4.245), (2.98,2.865,8.44,3.865), (16.095,2.865,17.475,4.695)])
P(gf180mcu_fd_sc_mcu9t5v0_, comp, [(8.8,3.175),(8.8,4.175),(13.175,4.175),(13.175,4.555),(15.575,4.555),(15.575,3.175)],
  [(3.14,0.875),(3.14,1.575),(14.295,1.575),(14.295,1.665),(15.735,1.665),(15.735,0.875)])
R(gf180mcu_fd_sc_mcu9t5v0_, poly2, [(10.015,0.655,10.615,2.035), (11.28,2.715,11.78,4.395)])
P(gf180mcu_fd_sc_mcu9t5v0_, poly2, [(0.62,0.655),(0.62,1.885),(0.66,1.885),(0.66,4.465),(1.16,4.465),(1.16,1.885),(1.22,1.885),(1.22,0.655)],
  [(3.58,0.655),(3.58,1.875),(3.42,1.875),(3.42,4.085),(3.92,4.085),(3.92,1.875),(4.18,1.875),(4.18,0.655)],
  [(1.74,0.215),(1.74,1.965),(1.68,1.965),(1.68,4.745),(4.94,4.745),(4.94,2.645),(4.44,2.645),(4.44,4.545),(2.18,4.545),(2.18,1.965),(2.34,1.965),(2.34,0.415),(5.82,0.415),(5.82,1.795),(6.06,1.795),(6.06,2.035),(6.42,2.035),(6.42,0.215)],
  [(6.66,0.655),(6.66,2.565),(6.48,2.565),(6.48,4.085),(6.98,4.085),(6.98,2.565),(7.02,2.565),(7.02,1.795),(7.26,1.795),(7.26,0.655)],
  [(8.82,0.655),(8.82,1.795),(9.22,1.795),(9.22,2.61),(9.24,2.61),(9.24,4.395),(9.74,4.395),(9.74,2.52),(9.42,2.52),(9.42,0.655)],
  [(4.7,0.655),(4.7,2.175),(5.46,2.175),(5.46,4.835),(10.76,4.835),(10.76,2.475),(11.755,2.475),(11.755,0.655),(11.155,0.655),(11.155,2.275),(10.26,2.275),(10.26,4.635),(5.96,4.635),(5.96,2.645),(5.66,2.645),(5.66,1.975),(5.3,1.975),(5.3,0.655)],
  [(12.275,0.655),(12.275,1.795),(12.375,1.795),(12.375,4.395),(12.875,4.395),(12.875,0.655)],
  [(7.5,0.215),(7.5,4.085),(8,4.085),(8,1.795),(8.1,1.795),(8.1,0.415),(13.615,0.415),(13.615,0.655),(13.395,0.655),(13.395,1.905),(13.615,1.905),(13.615,4.775),(14.115,4.775),(14.115,1.905),(13.995,1.905),(13.995,0.415),(14.115,0.415),(14.115,0.215)],
  [(14.695,0.655),(14.695,1.965),(14.635,1.965),(14.635,4.775),(15.135,4.775),(15.135,1.965),(15.295,1.965),(15.295,0.655)],
  [(16.535,0.125),(16.535,1.965),(15.635,1.965),(15.635,2.325),(16.535,2.325),(16.535,4.915),(17.035,4.915),(17.035,1.885),(17.135,1.885),(17.135,0.125)])
R(gf180mcu_fd_sc_mcu9t5v0_, pplus, [(-0.2,2.265,18.12,5.24)])
R(gf180mcu_fd_sc_mcu9t5v0_, nplus, [(-0.2,-0.2,18.12,2.265)])
A(gf180mcu_fd_sc_mcu9t5v0_, contact, 9.89, 3.245, 0.22, 0.22, 3, 1, 1.02, 0)
A(gf180mcu_fd_sc_mcu9t5v0_, contact, 6.11, 3.575, 0.22, 0.22, 3, 1, 1.02, 0)
R(gf180mcu_fd_sc_mcu9t5v0_, contact, [(17.285,0.415,17.505,0.635), (17.285,0.885,17.505,1.105), (16.165,0.905,16.385,1.125), (1.37,0.945,1.59,1.165), (3.21,0.945,3.43,1.165), (8.25,0.945,8.47,1.165), (13.025,0.945,13.245,1.165), (4.33,1.285,4.55,1.505), (5.45,1.285,5.67,1.505), (9.64,1.285,9.86,1.505), (10.785,1.285,11.005,1.505), (11.905,1.285,12.125,1.505), (0.25,1.375,0.47,1.595), (2.49,1.375,2.71,1.595), (15.445,1.375,15.665,1.595), (16.165,1.375,16.385,1.595), (6.13,1.745,6.35,1.965), (10.325,1.745,10.545,1.965), (13.685,1.745,13.905,1.965), (1.81,1.835,2.03,2.055), (6.73,1.955,6.95,2.175), (15.705,2.035,15.925,2.255), (0.73,2.295,0.95,2.515), (3.49,2.315,3.71,2.535), (9.31,2.59,9.53,2.81), (11.35,2.785,11.57,3.005), (12.585,2.785,12.805,3.005), (14.725,2.785,14.945,3.005), (2.33,2.935,2.55,3.155), (4.07,2.935,4.29,3.155), (5.09,2.935,5.31,3.155), (16.165,2.935,16.385,3.155), (0.29,3,0.51,3.22), (6.11,3.105,6.33,3.325), (8.15,3.105,8.37,3.325), (14.265,3.245,14.485,3.465), (2.33,3.405,2.55,3.625), (4.07,3.405,4.29,3.625), (5.09,3.405,5.31,3.625), (16.165,3.405,16.385,3.625), (8.87,3.415,9.09,3.635), (0.29,3.47,0.51,3.69), (1.31,3.485,1.53,3.705), (3.05,3.575,3.27,3.795), (9.89,3.715,10.11,3.935), (10.91,3.715,11.13,3.935), (15.285,3.795,15.505,4.015), (8.87,3.885,9.09,4.105), (17.185,3.935,17.405,4.155), (1.31,3.955,1.53,4.175), (5.53,4.035,5.75,4.255), (13.245,4.265,13.465,4.485), (15.285,4.265,15.505,4.485), (17.185,4.405,17.405,4.625)])
R(gf180mcu_fd_sc_mcu9t5v0_, metal1, [(13.59,1.21,13.91,2.025), (11.9,1.225,12.155,3.525), (0.665,2.235,1.575,2.71), (2.945,2.31,3.77,2.71)])
P(gf180mcu_fd_sc_mcu9t5v0_, metal1, [(0.245,1.315),(0.245,1.74),(1.805,1.74),(1.805,2.94),(0.285,2.94),(0.285,3.75),(0.515,3.75),(0.515,3.17),(2.035,3.17),(2.035,1.51),(0.475,1.51),(0.475,1.315)],
  [(4.065,1.28),(4.065,3.685),(4.295,3.685),(4.295,1.51),(4.61,1.51),(4.61,1.28)],
  [(2.325,1.315),(2.325,3.685),(2.555,3.685),(2.555,3.285),(3.505,3.285),(3.505,4.315),(5.755,4.315),(5.755,3.975),(3.735,3.975),(3.735,3.055),(2.715,3.055),(2.715,1.315)],
  [(6.105,3.045),(6.105,3.855),(6.335,3.855),(6.335,3.275),(8.145,3.275),(8.145,3.855),(8.375,3.855),(8.375,3.045)],
  [(5.445,1.225),(5.445,2.765),(5.085,2.765),(5.085,3.685),(5.315,3.685),(5.315,2.995),(5.67,2.995),(5.67,2.815),(9.59,2.815),(9.59,2.585),(5.675,2.585),(5.675,1.225)],
  [(9.635,1.225),(9.635,1.95),(6.67,1.95),(6.67,2.18),(9.64,2.18),(9.64,2.36),(9.885,2.36),(9.885,3.995),(10.115,3.995),(10.115,2.13),(9.865,2.13),(9.865,1.225)],
  [(9.175,0.765),(9.175,1.455),(6.125,1.455),(6.125,2.025),(6.355,2.025),(6.355,1.685),(9.405,1.685),(9.405,0.995),(10.32,0.995),(10.32,2.025),(10.55,2.025),(10.55,0.995),(11.345,0.995),(11.345,3.065),(11.575,3.065),(11.575,0.765)],
  [(10.78,1.225),(10.78,3.995),(14.95,3.995),(14.95,2.725),(14.72,2.725),(14.72,3.765),(11.135,3.765),(11.135,3.185),(11.01,3.185),(11.01,1.225)],
  [(15.44,1.315),(15.44,2.265),(14.26,2.265),(14.26,3.295),(12.81,3.295),(12.81,2.725),(12.58,2.725),(12.58,3.525),(14.49,3.525),(14.49,2.495),(15.93,2.495),(15.93,1.975),(15.67,1.975),(15.67,1.315)],
  [(16.16,0.845),(16.16,3.45),(15.83,3.45),(15.83,3.83),(16.39,3.83),(16.39,0.845)],
  [(0,-0.45),(0,0.45),(1.365,0.45),(1.365,1.225),(1.595,1.225),(1.595,0.45),(3.205,0.45),(3.205,1.225),(3.435,1.225),(3.435,0.45),(8.245,0.45),(8.245,1.225),(8.475,1.225),(8.475,0.45),(13.02,0.45),(13.02,1.225),(13.25,1.225),(13.25,0.45),(17.28,0.45),(17.28,1.165),(17.51,1.165),(17.51,0.45),(17.92,0.45),(17.92,-0.45)],
  [(8.865,3.355),(8.865,4.59),(7.355,4.59),(7.355,3.515),(7.125,3.515),(7.125,4.59),(3.275,4.59),(3.275,3.515),(3.045,3.515),(3.045,4.59),(1.535,4.59),(1.535,3.425),(1.305,3.425),(1.305,4.59),(0,4.59),(0,5.49),(17.92,5.49),(17.92,4.59),(17.41,4.59),(17.41,3.875),(17.18,3.875),(17.18,4.59),(15.51,4.59),(15.51,3.735),(15.28,3.735),(15.28,4.59),(13.525,4.59),(13.525,4.26),(13.185,4.26),(13.185,4.59),(9.095,4.59),(9.095,3.355)])
R(gf180mcu_fd_sc_mcu9t5v0_, dualgate, [(-0.28,-0.28,18.2,5.32)])
R(gf180mcu_fd_sc_mcu9t5v0_, v5_xtor, [(0,0,17.92,5.04)])
R(gf180mcu_fd_sc_mcu9t5v0_, lvpwell, [(-0.43,-0.43,18.35,2.265)])
gf180mcu_fd_sc_mcu9t5v0_.add(gdstk.Label('CLKN', (0.84,2.52), layer=34, texttype=10))
gf180mcu_fd_sc_mcu9t5v0_.add(gdstk.Label('D', (3.08,2.52), layer=34, texttype=10))
gf180mcu_fd_sc_mcu9t5v0_.add(gdstk.Label('Q', (15.96,3.64), layer=34, texttype=10))
gf180mcu_fd_sc_mcu9t5v0_.add(gdstk.Label('RN', (13.72,1.4), layer=34, texttype=10))
gf180mcu_fd_sc_mcu9t5v0_.add(gdstk.Label('VDD', (1.42,4.59), layer=34, texttype=10))
gf180mcu_fd_sc_mcu9t5v0_.add(gdstk.Label('VSS', (17.395,0.45), layer=34, texttype=10))
gf180mcu_fd_sc_mcu9t5v0_.add(gdstk.Label('& Vendor GLOBALFOUNDRIES', (0,2), layer=63, texttype=63))
gf180mcu_fd_sc_mcu9t5v0_.add(gdstk.Label('& Product GF018hv5v_green_sc9', (0,1.5), layer=63, texttype=63))
gf180mcu_fd_sc_mcu9t5v0_.add(gdstk.Label('& Version 2015q2v2', (0,1), layer=63, texttype=63))
gf180mcu_fd_sc_mcu9t5v0_.add(gdstk.Label('& Metric 1.00', (0,0.5), layer=63, texttype=63))
gf180mcu_fd_sc_mcu9t5v0_.add(gdstk.Label('VNW', (0.345,3.92), layer=21, texttype=10))
gf180mcu_fd_sc_mcu9t5v0_.add(gdstk.Label('VPW', (0.34,-0.085), layer=204, texttype=10))

lib.write_gds('gf180mcu_fd_sc_mcu9t5v0__dffnrnq_1.gds')
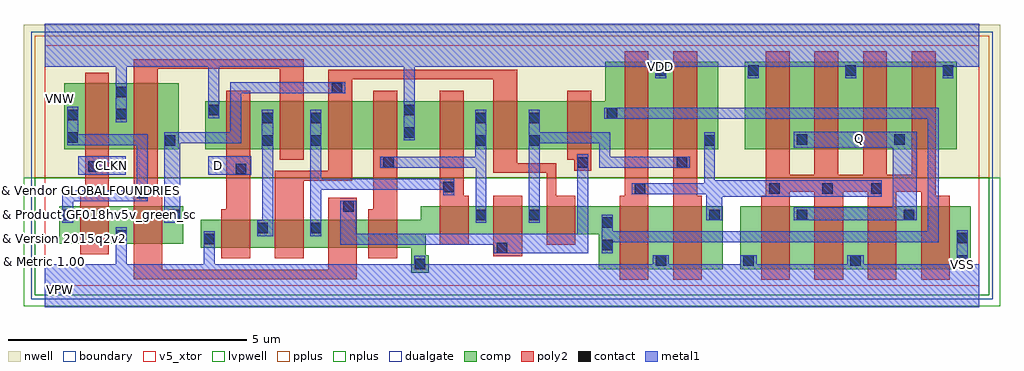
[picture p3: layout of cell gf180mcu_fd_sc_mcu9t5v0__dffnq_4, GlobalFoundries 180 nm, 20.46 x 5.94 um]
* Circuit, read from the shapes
.subckt gf180mcu_fd_sc_mcu9t5v0__dffnq_4 CLKN D Q VDD VNW VSS
XM1 VSS CLKN n1 VSUBS nfet_05v0 w=0.79u l=0.6u
XM2 n2 n1 VSS VSUBS nfet_05v0 w=0.79u l=0.6u
XM3 n3 D VSS VSUBS nfet_05v0 w=0.59u l=0.6u
XM4 n4 n2 n3 VSUBS nfet_05v0 w=0.59u l=0.6u
XM5 n5 n1 n4 VSUBS nfet_05v0 w=0.59u l=0.6u
XM6 VSS n6 n5 VSUBS nfet_05v0 w=0.59u l=0.6u
XM7 n6 n4 VSS VSUBS nfet_05v0 w=0.59u l=0.6u
XM8 n7 n1 n6 VSUBS nfet_05v0 w=0.59u l=0.6u
XM9 n8 n2 n7 VSUBS nfet_05v0 w=0.59u l=0.6u
XM10 VSS n9 n8 VSUBS nfet_05v0 w=1.32u l=0.6u
XM11 n9 n7 VSS VSUBS nfet_05v0 w=1.32u l=0.6u
XM12 Q n9 VSS VSUBS nfet_05v0 w=1.32u l=0.6u m=4
XM13 VDD CLKN n1 VNW pfet_05v0 w=1.38u l=0.5u
XM14 n2 n1 VDD VNW pfet_05v0 w=1.38u l=0.5u
XM15 n3 D VDD VNW pfet_05v0 w=1u l=0.5u
XM16 n4 n1 n3 VNW pfet_05v0 w=1u l=0.5u
XM17 n10 n2 n4 VNW pfet_05v0 w=1u l=0.5u
XM18 VDD n6 n10 VNW pfet_05v0 w=1u l=0.5u
XM19 n6 n4 VDD VNW pfet_05v0 w=1u l=0.5u
XM20 n7 n2 n6 VNW pfet_05v0 w=1u l=0.5u
XM21 n8 n1 n7 VNW pfet_05v0 w=1u l=0.5u
XM22 VDD n9 n8 VNW pfet_05v0 w=1.83u l=0.5u
XM23 n9 n7 VDD VNW pfet_05v0 w=1.83u l=0.5u
XM24 Q n9 VDD VNW pfet_05v0 w=1.83u l=0.5u m=4
.ends

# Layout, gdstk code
import gdstk
lib = gdstk.Library(unit=1e-6, precision=1e-09)
def R(c, l, rs):  # rectangles x0, y0, x1, y1
    for r in rs: c.add(gdstk.rectangle(r[:2], r[2:], *l))
def A(c, l, x, y, w, h, nx, ny, dx, dy):  # array of equal rectangles
    R(c, l, [(x+i*dx, y+j*dy, x+i*dx+w, y+j*dy+h) for i in range(nx) for j in range(ny)])
def P(c, l, *ps):  # polygons
    for p in ps: c.add(gdstk.Polygon(p, *l))
boundary = (0, 0)
nwell = (21, 0)
comp = (22, 0)
poly2 = (30, 0)
pplus = (31, 0)
nplus = (32, 0)
contact = (33, 0)
metal1 = (34, 0)
dualgate = (55, 0)
v5_xtor = (112, 1)
lvpwell = (204, 0)

gf180mcu_fd_sc_mcu9t5v0_ = lib.new_cell('gf180mcu_fd_sc_mcu9t5v0__dffnq_4')
R(gf180mcu_fd_sc_mcu9t5v0_, boundary, [(0,0,19.6,5.04)])
R(gf180mcu_fd_sc_mcu9t5v0_, nwell, [(-0.43,2.265,20.03,5.47)])
R(gf180mcu_fd_sc_mcu9t5v0_, comp, [(14.58,0.345,19.42,1.665), (0.31,0.875,2.91,1.665), (0.41,2.865,2.81,4.245), (14.68,2.865,19.12,4.695)])
P(gf180mcu_fd_sc_mcu9t5v0_, comp, [(3.37,2.865),(3.37,3.865),(11.76,3.865),(11.76,4.695),(14.12,4.695),(14.12,2.865)],
  [(7.69,0.275),(7.69,0.795),(3.27,0.795),(3.27,1.385),(7.89,1.385),(7.89,1.665),(14.22,1.665),(14.22,0.345),(11.62,0.345),(11.62,1.075),(7.99,1.075),(7.99,0.635),(8.05,0.635),(8.05,0.275)])
R(gf180mcu_fd_sc_mcu9t5v0_, poly2, [(9.41,0.615,10.01,1.885)])
P(gf180mcu_fd_sc_mcu9t5v0_, poly2, [(0.75,0.655),(0.75,1.885),(0.85,1.885),(0.85,4.465),(1.35,4.465),(1.35,0.655)],
  [(3.71,0.575),(3.71,1.605),(3.81,1.605),(3.81,4.085),(4.31,4.085),(4.31,0.575)],
  [(1.87,0.135),(1.87,4.745),(5.43,4.745),(5.43,2.645),(4.93,2.645),(4.93,4.545),(2.37,4.545),(2.37,1.885),(2.47,1.885),(2.47,0.335),(5.95,0.335),(5.95,1.845),(6.55,1.845),(6.55,0.135)],
  [(6.79,0.575),(6.79,1.605),(6.89,1.605),(6.89,4.085),(7.39,4.085),(7.39,0.575)],
  [(8.29,0.855),(8.29,4.085),(8.79,4.085),(8.79,1.885),(8.89,1.885),(8.89,0.855)],
  [(4.83,0.575),(4.83,2.405),(5.95,2.405),(5.95,4.525),(9.905,4.525),(9.905,2.565),(10.73,2.565),(10.73,1.885),(11.13,1.885),(11.13,0.855),(10.53,0.855),(10.53,2.365),(9.405,2.365),(9.405,4.325),(6.45,4.325),(6.45,2.205),(5.43,2.205),(5.43,0.575)],
  [(11.1,2.405),(11.1,2.645),(10.96,2.645),(10.96,4.085),(11.46,4.085),(11.46,2.405)],
  [(12.06,0.125),(12.06,1.885),(12.16,1.885),(12.16,4.915),(12.66,4.915),(12.66,0.125)],
  [(13.18,0.125),(13.18,4.915),(13.68,4.915),(13.68,1.885),(13.78,1.885),(13.78,0.125)],
  [(15.02,0.125),(15.02,1.885),(15.12,1.885),(15.12,4.915),(15.62,4.915),(15.62,2.325),(16.14,2.325),(16.14,4.915),(16.64,4.915),(16.64,2.325),(17.16,2.325),(17.16,4.915),(17.66,4.915),(17.66,2.325),(18.18,2.325),(18.18,4.915),(18.68,4.915),(18.68,1.885),(18.98,1.885),(18.98,0.125),(18.38,0.125),(18.38,1.965),(17.86,1.965),(17.86,0.125),(17.26,0.125),(17.26,1.965),(16.74,1.965),(16.74,0.125),(16.14,0.125),(16.14,1.965),(15.62,1.965),(15.62,0.125)])
R(gf180mcu_fd_sc_mcu9t5v0_, pplus, [(-0.2,2.265,19.8,5.24)])
R(gf180mcu_fd_sc_mcu9t5v0_, nplus, [(-0.2,-0.2,19.8,2.265)])
A(gf180mcu_fd_sc_mcu9t5v0_, contact, 14.65, 0.415, 0.22, 0.22, 3, 1, 2.24, 0)
A(gf180mcu_fd_sc_mcu9t5v0_, contact, 14.75, 4.405, 0.22, 0.22, 3, 1, 2.04, 0)
R(gf180mcu_fd_sc_mcu9t5v0_, contact, [(7.76,0.345,7.98,0.565), (12.81,0.415,13.03,0.635), (9.48,0.685,9.7,0.905), (11.69,0.74,11.91,0.96), (3.34,0.865,3.56,1.085), (19.13,0.885,19.35,1.105), (1.5,0.945,1.72,1.165), (4.46,1.095,4.68,1.315), (5.58,1.095,5.8,1.315), (11.69,1.21,11.91,1.43), (0.38,1.375,0.6,1.595), (2.62,1.375,2.84,1.595), (9.04,1.375,9.26,1.595), (10.16,1.375,10.38,1.595), (13.93,1.375,14.15,1.595), (15.77,1.375,15.99,1.595), (18.01,1.375,18.23,1.595), (6.26,1.555,6.48,1.775), (1.94,1.835,2.16,2.055), (12.37,1.925,12.59,2.145), (15.19,1.93,15.41,2.15), (16.305,1.93,16.525,2.15), (17.33,1.93,17.55,2.15), (8.36,1.96,8.58,2.18), (4.01,2.335,4.23,2.555), (0.92,2.39,1.14,2.61), (7.1,2.475,7.32,2.695), (11.17,2.475,11.39,2.695), (13.25,2.475,13.47,2.695), (2.52,2.935,2.74,3.155), (4.56,2.935,4.78,3.155), (5.58,2.935,5.8,3.155), (9.035,2.935,9.255,3.155), (10.16,2.935,10.38,3.155), (13.83,2.935,14.05,3.155), (15.77,2.95,15.99,3.17), (17.81,2.95,18.03,3.17), (0.48,3,0.7,3.22), (7.54,3.105,7.76,3.325), (4.56,3.405,4.78,3.625), (5.58,3.405,5.8,3.625), (9.035,3.405,9.255,3.625), (10.16,3.405,10.38,3.625), (0.48,3.47,0.7,3.69), (1.5,3.485,1.72,3.705), (11.79,3.505,12.01,3.725), (3.44,3.575,3.66,3.795), (7.54,3.575,7.76,3.795), (1.5,3.955,1.72,4.175), (6.02,4.035,6.24,4.255), (12.81,4.405,13.03,4.625)])
R(gf180mcu_fd_sc_mcu9t5v0_, metal1, [(0.71,2.33,1.705,2.71), (3.43,2.33,4.33,2.71)])
P(gf180mcu_fd_sc_mcu9t5v0_, metal1, [(0.375,1.315),(0.375,2.005),(1.935,2.005),(1.935,2.94),(0.475,2.94),(0.475,3.75),(0.705,3.75),(0.705,3.17),(2.165,3.17),(2.165,1.775),(0.605,1.775),(0.605,1.315)],
  [(4.455,1.035),(4.455,1.375),(4.56,1.375),(4.56,2.875),(4.555,2.875),(4.555,3.685),(4.79,3.685),(4.79,1.035)],
  [(2.515,1.315),(2.515,3.215),(3.895,3.215),(3.895,4.26),(6.3,4.26),(6.3,4.03),(4.125,4.03),(4.125,2.985),(2.845,2.985),(2.845,1.315)],
  [(5.575,1.035),(5.575,3.685),(5.805,3.685),(5.805,2.24),(8.585,2.24),(8.585,1.9),(8.355,1.9),(8.355,2.01),(5.805,2.01),(5.805,1.035)],
  [(9.035,1.315),(9.035,2.47),(7.04,2.47),(7.04,2.7),(9.03,2.7),(9.03,3.685),(9.265,3.685),(9.265,1.315)],
  [(9.42,0.68),(9.42,0.855),(6.2,0.855),(6.2,1.78),(6.54,1.78),(6.54,1.085),(11.165,1.085),(11.165,2.755),(11.395,2.755),(11.395,0.68)],
  [(10.155,1.315),(10.155,3.685),(10.385,3.685),(10.385,3.215),(11.855,3.215),(11.855,2.7),(13.53,2.7),(13.53,2.47),(11.625,2.47),(11.625,2.985),(10.385,2.985),(10.385,1.315)],
  [(13.87,1.37),(13.87,1.92),(12.31,1.92),(12.31,2.15),(13.825,2.15),(13.825,3.215),(14.055,3.215),(14.055,2.21),(17.555,2.21),(17.555,1.87),(14.21,1.87),(14.21,1.37)],
  [(15.71,1.37),(15.71,1.64),(17.785,1.64),(17.785,2.89),(15.71,2.89),(15.71,3.23),(18.29,3.23),(18.29,1.37)],
  [(11.685,0.68),(11.685,1.49),(11.915,1.49),(11.915,1.14),(18.52,1.14),(18.52,3.5),(11.73,3.5),(11.73,3.73),(18.75,3.73),(18.75,0.91),(11.915,0.91),(11.915,0.68)],
  [(0,-0.45),(0,0.45),(1.495,0.45),(1.495,1.225),(1.725,1.225),(1.725,0.45),(3.335,0.45),(3.335,1.145),(3.565,1.145),(3.565,0.45),(7.755,0.45),(7.755,0.625),(7.985,0.625),(7.985,0.45),(12.75,0.45),(12.75,0.64),(13.09,0.64),(13.09,0.45),(14.59,0.45),(14.59,0.64),(14.93,0.64),(14.93,0.45),(16.83,0.45),(16.83,0.64),(17.17,0.64),(17.17,0.45),(19.125,0.45),(19.125,1.165),(19.355,1.165),(19.355,0.45),(19.6,0.45),(19.6,-0.45)],
  [(7.535,3.045),(7.535,4.59),(3.665,4.59),(3.665,3.515),(3.435,3.515),(3.435,4.59),(1.725,4.59),(1.725,3.425),(1.495,3.425),(1.495,4.59),(0,4.59),(0,5.49),(19.6,5.49),(19.6,4.59),(19.055,4.59),(19.055,4.345),(18.825,4.345),(18.825,4.59),(17.015,4.59),(17.015,4.345),(16.785,4.345),(16.785,4.59),(14.975,4.59),(14.975,4.345),(14.745,4.345),(14.745,4.59),(13.035,4.59),(13.035,4.345),(12.805,4.345),(12.805,4.59),(7.765,4.59),(7.765,3.045)])
R(gf180mcu_fd_sc_mcu9t5v0_, dualgate, [(-0.28,-0.28,19.88,5.32)])
R(gf180mcu_fd_sc_mcu9t5v0_, v5_xtor, [(0,0,19.6,5.04)])
R(gf180mcu_fd_sc_mcu9t5v0_, lvpwell, [(-0.43,-0.43,20.03,2.265)])
gf180mcu_fd_sc_mcu9t5v0_.add(gdstk.Label('CLKN', (1.4,2.52), layer=34, texttype=10))
gf180mcu_fd_sc_mcu9t5v0_.add(gdstk.Label('D', (3.64,2.52), layer=34, texttype=10))
gf180mcu_fd_sc_mcu9t5v0_.add(gdstk.Label('Q', (17.08,3.08), layer=34, texttype=10))
gf180mcu_fd_sc_mcu9t5v0_.add(gdstk.Label('VDD', (12.92,4.59), layer=34, texttype=10))
gf180mcu_fd_sc_mcu9t5v0_.add(gdstk.Label('VSS', (19.24,0.45), layer=34, texttype=10))
gf180mcu_fd_sc_mcu9t5v0_.add(gdstk.Label('& Vendor GLOBALFOUNDRIES', (0,2), layer=63, texttype=63))
gf180mcu_fd_sc_mcu9t5v0_.add(gdstk.Label('& Product GF018hv5v_green_sc9', (0,1.5), layer=63, texttype=63))
gf180mcu_fd_sc_mcu9t5v0_.add(gdstk.Label('& Version 2015q2v2', (0,1), layer=63, texttype=63))
gf180mcu_fd_sc_mcu9t5v0_.add(gdstk.Label('& Metric 1.00', (0,0.5), layer=63, texttype=63))
gf180mcu_fd_sc_mcu9t5v0_.add(gdstk.Label('VNW', (0.345,3.92), layer=21, texttype=10))
gf180mcu_fd_sc_mcu9t5v0_.add(gdstk.Label('VPW', (0.34,-0.085), layer=204, texttype=10))

lib.write_gds('gf180mcu_fd_sc_mcu9t5v0__dffnq_4.gds')
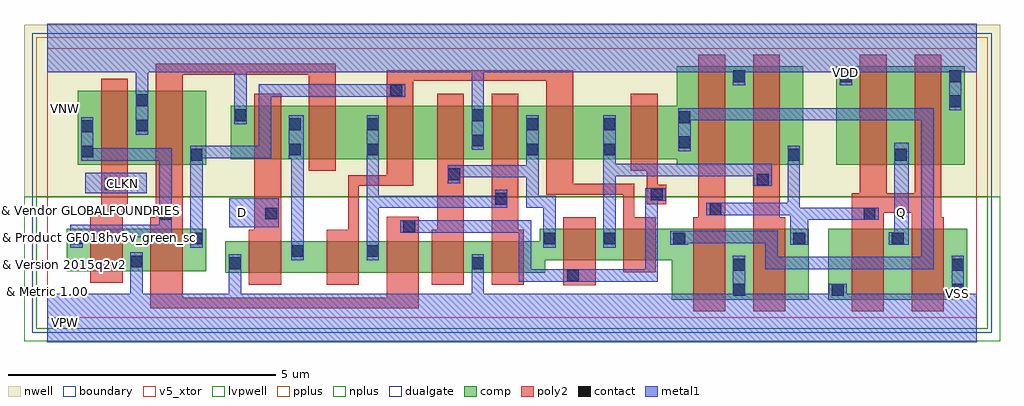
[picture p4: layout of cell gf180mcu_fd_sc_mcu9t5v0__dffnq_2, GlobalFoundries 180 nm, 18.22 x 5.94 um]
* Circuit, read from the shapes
.subckt gf180mcu_fd_sc_mcu9t5v0__dffnq_2 CLKN D Q VDD VNW VSS
XM1 VSS CLKN n1 VSUBS nfet_05v0 w=0.79u l=0.6u
XM2 n2 n1 VSS VSUBS nfet_05v0 w=0.79u l=0.6u
XM3 n3 D VSS VSUBS nfet_05v0 w=0.59u l=0.6u
XM4 n4 n2 n3 VSUBS nfet_05v0 w=0.59u l=0.6u
XM5 n5 n1 n4 VSUBS nfet_05v0 w=0.59u l=0.6u
XM6 VSS n6 n5 VSUBS nfet_05v0 w=0.59u l=0.6u
XM7 n6 n4 VSS VSUBS nfet_05v0 w=0.59u l=0.6u
XM8 n7 n1 n6 VSUBS nfet_05v0 w=0.59u l=0.6u
XM9 n8 n2 n7 VSUBS nfet_05v0 w=0.59u l=0.6u
XM10 VSS n9 n8 VSUBS nfet_05v0 w=1.32u l=0.6u
XM11 n9 n7 VSS VSUBS nfet_05v0 w=1.32u l=0.6u
XM12 Q n9 VSS VSUBS nfet_05v0 w=1.32u l=0.6u m=2
XM13 VDD CLKN n1 VNW pfet_05v0 w=1.38u l=0.5u
XM14 n2 n1 VDD VNW pfet_05v0 w=1.38u l=0.5u
XM15 n3 D VDD VNW pfet_05v0 w=1u l=0.5u
XM16 n4 n1 n3 VNW pfet_05v0 w=1u l=0.5u
XM17 n10 n2 n4 VNW pfet_05v0 w=1u l=0.5u
XM18 VDD n6 n10 VNW pfet_05v0 w=1u l=0.5u
XM19 n6 n4 VDD VNW pfet_05v0 w=1u l=0.5u
XM20 n7 n2 n6 VNW pfet_05v0 w=1u l=0.5u
XM21 n8 n1 n7 VNW pfet_05v0 w=1u l=0.5u
XM22 VDD n9 n8 VNW pfet_05v0 w=1.83u l=0.5u
XM23 n9 n7 VDD VNW pfet_05v0 w=1.83u l=0.5u
XM24 Q n9 VDD VNW pfet_05v0 w=1.83u l=0.5u m=2
.ends

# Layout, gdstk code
import gdstk
lib = gdstk.Library(unit=1e-6, precision=1e-09)
def R(c, l, rs):  # rectangles x0, y0, x1, y1
    for r in rs: c.add(gdstk.rectangle(r[:2], r[2:], *l))
def P(c, l, *ps):  # polygons
    for p in ps: c.add(gdstk.Polygon(p, *l))
boundary = (0, 0)
nwell = (21, 0)
comp = (22, 0)
poly2 = (30, 0)
pplus = (31, 0)
nplus = (32, 0)
contact = (33, 0)
metal1 = (34, 0)
dualgate = (55, 0)
v5_xtor = (112, 1)
lvpwell = (204, 0)

gf180mcu_fd_sc_mcu9t5v0_ = lib.new_cell('gf180mcu_fd_sc_mcu9t5v0__dffnq_2')
R(gf180mcu_fd_sc_mcu9t5v0_, boundary, [(0,0,17.36,5.04)])
R(gf180mcu_fd_sc_mcu9t5v0_, nwell, [(-0.43,2.265,17.79,5.47)])
R(gf180mcu_fd_sc_mcu9t5v0_, comp, [(14.58,0.345,17.18,1.665), (0.37,0.875,2.97,1.665), (0.57,2.865,2.97,4.245), (14.735,2.865,17.135,4.695)])
P(gf180mcu_fd_sc_mcu9t5v0_, comp, [(11.76,2.865),(11.76,2.965),(3.43,2.965),(3.43,3.965),(11.76,3.965),(11.76,4.695),(14.12,4.695),(14.12,2.865)],
  [(11.66,0.345),(11.66,1.075),(9.3,1.075),(9.3,0.84),(3.33,0.84),(3.33,1.43),(9.2,1.43),(9.2,1.665),(14.22,1.665),(14.22,0.345)])
R(gf180mcu_fd_sc_mcu9t5v0_, poly2, [(9.64,0.615,10.24,1.885)])
P(gf180mcu_fd_sc_mcu9t5v0_, poly2, [(0.81,0.655),(0.81,1.965),(1.01,1.965),(1.01,4.465),(1.51,4.465),(1.51,1.965),(1.41,1.965),(1.41,0.655)],
  [(3.77,0.62),(3.77,1.65),(3.87,1.65),(3.87,4.185),(4.37,4.185),(4.37,0.62)],
  [(1.93,0.18),(1.93,1.885),(2.03,1.885),(2.03,4.745),(5.39,4.745),(5.39,2.745),(4.89,2.745),(4.89,4.545),(2.53,4.545),(2.53,0.38),(6.34,0.38),(6.34,1.89),(6.94,1.89),(6.94,0.18)],
  [(7.18,0.62),(7.18,1.65),(7.28,1.65),(7.28,4.185),(7.78,4.185),(7.78,0.62)],
  [(8.3,0.62),(8.3,4.185),(8.8,4.185),(8.8,1.65),(8.9,1.65),(8.9,0.62)],
  [(5.22,0.62),(5.22,1.65),(5.62,1.65),(5.62,2.665),(6.34,2.665),(6.34,4.625),(9.82,4.625),(9.82,2.505),(10.96,2.505),(10.96,1.885),(11.36,1.885),(11.36,0.855),(10.76,0.855),(10.76,2.305),(9.32,2.305),(9.32,4.425),(6.84,4.425),(6.84,2.465),(5.82,2.465),(5.82,0.62)],
  [(11.2,2.125),(11.2,2.745),(10.9,2.745),(10.9,4.185),(11.4,4.185),(11.4,2.485),(11.56,2.485),(11.56,2.125)],
  [(12.06,0.125),(12.06,1.885),(12.16,1.885),(12.16,4.915),(12.66,4.915),(12.66,0.125)],
  [(13.18,0.125),(13.18,4.915),(13.68,4.915),(13.68,1.885),(13.78,1.885),(13.78,0.125)],
  [(15.02,0.125),(15.02,2.325),(15.175,2.325),(15.175,4.915),(15.675,4.915),(15.675,2.325),(16.195,2.325),(16.195,4.915),(16.695,4.915),(16.695,1.885),(16.74,1.885),(16.74,0.125),(16.14,0.125),(16.14,1.965),(15.62,1.965),(15.62,0.125)])
R(gf180mcu_fd_sc_mcu9t5v0_, pplus, [(-0.2,2.265,17.56,5.24)])
R(gf180mcu_fd_sc_mcu9t5v0_, nplus, [(-0.2,-0.2,17.56,2.265)])
R(gf180mcu_fd_sc_mcu9t5v0_, contact, [(12.81,0.415,13.03,0.635), (14.65,0.415,14.87,0.635), (16.89,0.415,17.11,0.635), (9.71,0.685,9.93,0.905), (12.81,0.885,13.03,1.105), (16.89,0.885,17.11,1.105), (3.4,0.91,3.62,1.13), (7.93,0.91,8.15,1.13), (1.56,0.945,1.78,1.165), (4.565,1.14,4.785,1.36), (5.97,1.14,6.19,1.36), (0.44,1.375,0.66,1.595), (2.68,1.375,2.9,1.595), (9.27,1.375,9.49,1.595), (10.39,1.375,10.61,1.595), (11.69,1.375,11.91,1.595), (13.93,1.375,14.15,1.595), (15.77,1.375,15.99,1.595), (6.65,1.6,6.87,1.82), (2.1,1.835,2.32,2.055), (15.245,1.835,15.465,2.055), (4.075,1.84,4.295,2.06), (12.37,1.925,12.59,2.145), (8.37,2.115,8.59,2.335), (11.27,2.195,11.49,2.415), (1.08,2.39,1.3,2.61), (13.25,2.475,13.47,2.695), (7.49,2.575,7.71,2.795), (2.68,2.935,2.9,3.155), (13.83,2.935,14.05,3.155), (15.825,2.935,16.045,3.155), (0.64,3,0.86,3.22), (4.52,3.035,4.74,3.255), (5.97,3.035,6.19,3.255), (8.95,3.035,9.17,3.255), (10.39,3.035,10.61,3.255), (11.79,3.17,12.01,3.39), (7.93,3.205,8.15,3.425), (0.64,3.47,0.86,3.69), (1.66,3.485,1.88,3.705), (4.52,3.505,4.74,3.725), (5.97,3.505,6.19,3.725), (8.95,3.505,9.17,3.725), (10.39,3.505,10.61,3.725), (11.79,3.64,12.01,3.86), (3.5,3.675,3.72,3.895), (7.93,3.675,8.15,3.895), (16.845,3.935,17.065,4.155), (1.66,3.955,1.88,4.175), (6.41,4.135,6.63,4.355), (12.81,4.405,13.03,4.625), (14.805,4.405,15.025,4.625), (16.845,4.405,17.065,4.625)])
R(gf180mcu_fd_sc_mcu9t5v0_, metal1, [(3.4,1.69,4.325,2.235), (0.71,2.33,1.865,2.71)])
P(gf180mcu_fd_sc_mcu9t5v0_, metal1, [(0.435,1.315),(0.435,1.74),(2.095,1.74),(2.095,2.94),(0.635,2.94),(0.635,3.75),(0.865,3.75),(0.865,3.17),(2.325,3.17),(2.325,1.51),(0.665,1.51),(0.665,1.315)],
  [(4.56,1.08),(4.56,2.975),(4.515,2.975),(4.515,3.785),(4.79,3.785),(4.79,1.08)],
  [(2.675,1.315),(2.675,3.215),(3.955,3.215),(3.955,4.36),(6.69,4.36),(6.69,4.13),(4.185,4.13),(4.185,2.985),(2.905,2.985),(2.905,1.315)],
  [(5.965,1.08),(5.965,3.785),(6.195,3.785),(6.195,2.285),(8.365,2.285),(8.365,2.395),(8.595,2.395),(8.595,2.055),(6.195,2.055),(6.195,1.08)],
  [(9.265,1.315),(9.265,2.055),(8.945,2.055),(8.945,2.625),(7.715,2.625),(7.715,2.515),(7.485,2.515),(7.485,2.855),(8.945,2.855),(8.945,3.785),(9.175,3.785),(9.175,2.285),(9.495,2.285),(9.495,1.315)],
  [(8.805,0.68),(8.805,1.595),(6.59,1.595),(6.59,1.825),(9.035,1.825),(9.035,0.91),(11.17,0.91),(11.17,2.42),(11.55,2.42),(11.55,2.19),(11.4,2.19),(11.4,0.68)],
  [(10.385,1.315),(10.385,3.785),(10.615,3.785),(10.615,2.88),(13.53,2.88),(13.53,2.47),(13.19,2.47),(13.19,2.65),(10.615,2.65),(10.615,1.315)],
  [(13.87,1.37),(13.87,1.92),(12.31,1.92),(12.31,2.15),(13.825,2.15),(13.825,3.215),(14.055,3.215),(14.055,2.06),(15.525,2.06),(15.525,1.83),(14.21,1.83),(14.21,1.37)],
  [(15.71,1.37),(15.71,1.6),(15.82,1.6),(15.82,3.27),(16.09,3.27),(16.09,1.37)],
  [(13.41,0.91),(13.41,1.395),(11.97,1.395),(11.97,1.37),(11.63,1.37),(11.63,1.625),(13.64,1.625),(13.64,1.14),(16.32,1.14),(16.32,3.69),(12.015,3.69),(12.015,3.11),(11.785,3.11),(11.785,3.92),(16.55,3.92),(16.55,0.91)],
  [(0,-0.45),(0,0.45),(1.555,0.45),(1.555,1.225),(1.785,1.225),(1.785,0.45),(3.395,0.45),(3.395,1.19),(3.625,1.19),(3.625,0.45),(7.925,0.45),(7.925,1.19),(8.155,1.19),(8.155,0.45),(12.805,0.45),(12.805,1.165),(13.035,1.165),(13.035,0.45),(14.59,0.45),(14.59,0.64),(14.93,0.64),(14.93,0.45),(16.885,0.45),(16.885,1.165),(17.115,1.165),(17.115,0.45),(17.36,0.45),(17.36,-0.45)],
  [(7.925,3.145),(7.925,4.59),(3.725,4.59),(3.725,3.615),(3.495,3.615),(3.495,4.59),(1.885,4.59),(1.885,3.425),(1.655,3.425),(1.655,4.59),(0,4.59),(0,5.49),(17.36,5.49),(17.36,4.59),(17.07,4.59),(17.07,3.875),(16.84,3.875),(16.84,4.59),(15.03,4.59),(15.03,4.345),(14.8,4.345),(14.8,4.59),(13.035,4.59),(13.035,4.345),(12.805,4.345),(12.805,4.59),(8.155,4.59),(8.155,3.145)])
R(gf180mcu_fd_sc_mcu9t5v0_, dualgate, [(-0.28,-0.28,17.64,5.32)])
R(gf180mcu_fd_sc_mcu9t5v0_, v5_xtor, [(0,0,17.36,5.04)])
R(gf180mcu_fd_sc_mcu9t5v0_, lvpwell, [(-0.43,-0.43,17.79,2.265)])
gf180mcu_fd_sc_mcu9t5v0_.add(gdstk.Label('CLKN', (1.4,2.52), layer=34, texttype=10))
gf180mcu_fd_sc_mcu9t5v0_.add(gdstk.Label('D', (3.64,1.96), layer=34, texttype=10))
gf180mcu_fd_sc_mcu9t5v0_.add(gdstk.Label('Q', (15.96,1.96), layer=34, texttype=10))
gf180mcu_fd_sc_mcu9t5v0_.add(gdstk.Label('VDD', (14.915,4.59), layer=34, texttype=10))
gf180mcu_fd_sc_mcu9t5v0_.add(gdstk.Label('VSS', (17,0.45), layer=34, texttype=10))
gf180mcu_fd_sc_mcu9t5v0_.add(gdstk.Label('& Vendor GLOBALFOUNDRIES', (0,2), layer=63, texttype=63))
gf180mcu_fd_sc_mcu9t5v0_.add(gdstk.Label('& Product GF018hv5v_green_sc9', (0,1.5), layer=63, texttype=63))
gf180mcu_fd_sc_mcu9t5v0_.add(gdstk.Label('& Version 2015q2v2', (0,1), layer=63, texttype=63))
gf180mcu_fd_sc_mcu9t5v0_.add(gdstk.Label('& Metric 1.00', (0,0.5), layer=63, texttype=63))
gf180mcu_fd_sc_mcu9t5v0_.add(gdstk.Label('VNW', (0.345,3.92), layer=21, texttype=10))
gf180mcu_fd_sc_mcu9t5v0_.add(gdstk.Label('VPW', (0.34,-0.085), layer=204, texttype=10))

lib.write_gds('gf180mcu_fd_sc_mcu9t5v0__dffnq_2.gds')
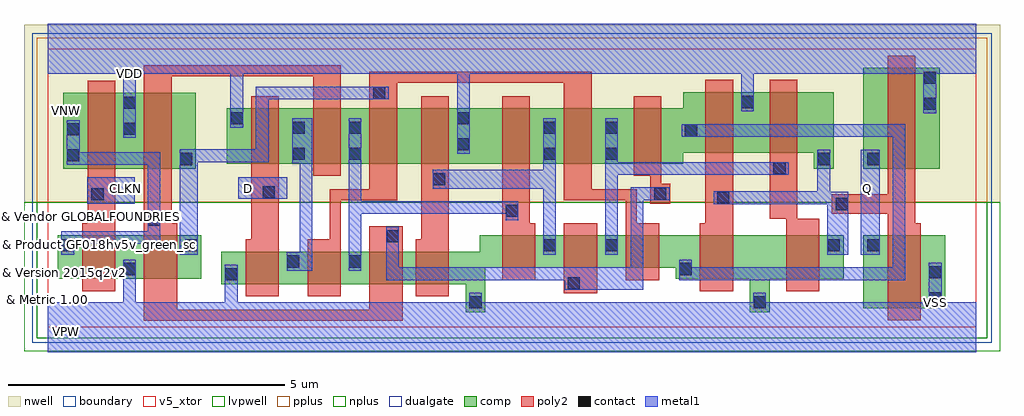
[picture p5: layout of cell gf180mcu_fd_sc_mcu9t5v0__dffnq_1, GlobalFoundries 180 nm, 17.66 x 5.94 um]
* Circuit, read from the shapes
.subckt gf180mcu_fd_sc_mcu9t5v0__dffnq_1 CLKN D Q VDD VNW VSS
XM1 VSS CLKN n1 VSUBS nfet_05v0 w=0.79u l=0.6u
XM2 n2 n1 VSS VSUBS nfet_05v0 w=0.79u l=0.6u
XM3 n3 D VSS VSUBS nfet_05v0 w=0.59u l=0.6u
XM4 n4 n2 n3 VSUBS nfet_05v0 w=0.59u l=0.6u
XM5 n5 n1 n4 VSUBS nfet_05v0 w=0.59u l=0.6u
XM6 VSS n6 n5 VSUBS nfet_05v0 w=0.59u l=0.6u
XM7 n6 n4 VSS VSUBS nfet_05v0 w=0.59u l=0.6u
XM8 n7 n1 n6 VSUBS nfet_05v0 w=0.59u l=0.6u
XM9 n8 n2 n7 VSUBS nfet_05v0 w=0.59u l=0.6u
XM10 VSS n9 n8 VSUBS nfet_05v0 w=0.79u l=0.6u
XM11 n9 n7 VSS VSUBS nfet_05v0 w=0.79u l=0.6u
XM12 VSS n9 Q VSUBS nfet_05v0 w=1.32u l=0.6u
XM13 VDD CLKN n1 VNW pfet_05v0 w=1.38u l=0.5u
XM14 n2 n1 VDD VNW pfet_05v0 w=1.38u l=0.5u
XM15 n3 D VDD VNW pfet_05v0 w=1u l=0.5u
XM16 n4 n1 n3 VNW pfet_05v0 w=1u l=0.5u
XM17 n10 n2 n4 VNW pfet_05v0 w=1u l=0.5u
XM18 VDD n6 n10 VNW pfet_05v0 w=1u l=0.5u
XM19 n6 n4 VDD VNW pfet_05v0 w=1u l=0.5u
XM20 n7 n2 n6 VNW pfet_05v0 w=1u l=0.5u
XM21 n8 n1 n7 VNW pfet_05v0 w=1u l=0.5u
XM22 VDD n9 n8 VNW pfet_05v0 w=1.1u l=0.5u
XM23 n9 n7 VDD VNW pfet_05v0 w=1.1u l=0.5u
XM24 VDD n9 Q VNW pfet_05v0 w=1.83u l=0.5u
.ends

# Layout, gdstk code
import gdstk
lib = gdstk.Library(unit=1e-6, precision=1e-09)
def R(c, l, rs):  # rectangles x0, y0, x1, y1
    for r in rs: c.add(gdstk.rectangle(r[:2], r[2:], *l))
def P(c, l, *ps):  # polygons
    for p in ps: c.add(gdstk.Polygon(p, *l))
boundary = (0, 0)
nwell = (21, 0)
comp = (22, 0)
poly2 = (30, 0)
pplus = (31, 0)
nplus = (32, 0)
contact = (33, 0)
metal1 = (34, 0)
dualgate = (55, 0)
v5_xtor = (112, 1)
lvpwell = (204, 0)

gf180mcu_fd_sc_mcu9t5v0_ = lib.new_cell('gf180mcu_fd_sc_mcu9t5v0__dffnq_1')
R(gf180mcu_fd_sc_mcu9t5v0_, boundary, [(0,0,16.8,5.04)])
R(gf180mcu_fd_sc_mcu9t5v0_, nwell, [(-0.43,2.265,17.23,5.47)])
R(gf180mcu_fd_sc_mcu9t5v0_, comp, [(14.76,0.345,16.24,1.665), (0.18,0.875,2.78,1.665), (0.28,2.865,2.68,4.245), (14.76,2.865,16.14,4.695)])
P(gf180mcu_fd_sc_mcu9t5v0_, comp, [(13.86,2.865),(13.86,3.155),(11.5,3.155),(11.5,2.96),(3.24,2.96),(3.24,3.96),(11.5,3.96),(11.5,4.255),(14.22,4.255),(14.22,2.865)],
  [(7.56,0.275),(7.56,0.78),(3.14,0.78),(3.14,1.37),(7.82,1.37),(7.82,1.665),(14.4,1.665),(14.4,0.875),(13.06,0.875),(13.06,0.275),(12.7,0.275),(12.7,0.875),(11.36,0.875),(11.36,1.075),(7.92,1.075),(7.92,0.275)])
R(gf180mcu_fd_sc_mcu9t5v0_, poly2, [(9.34,0.615,9.94,1.885)])
P(gf180mcu_fd_sc_mcu9t5v0_, poly2, [(0.62,0.655),(0.62,1.885),(0.72,1.885),(0.72,4.465),(1.22,4.465),(1.22,0.655)],
  [(3.58,0.56),(3.58,1.59),(3.68,1.59),(3.68,4.18),(4.18,4.18),(4.18,0.56)],
  [(1.74,0.12),(1.74,4.745),(5.3,4.745),(5.3,2.74),(4.8,2.74),(4.8,4.545),(2.24,4.545),(2.24,1.885),(2.34,1.885),(2.34,0.32),(5.82,0.32),(5.82,1.83),(6.42,1.83),(6.42,0.12)],
  [(6.66,0.56),(6.66,1.59),(6.76,1.59),(6.76,4.18),(7.26,4.18),(7.26,0.56)],
  [(8.22,0.855),(8.22,4.18),(8.72,4.18),(8.72,1.885),(8.82,1.885),(8.82,0.855)],
  [(4.7,0.56),(4.7,1.59),(5.1,1.59),(5.1,2.5),(5.82,2.5),(5.82,4.62),(9.84,4.62),(9.84,2.5),(10.66,2.5),(10.66,1.885),(11.06,1.885),(11.06,0.855),(10.46,0.855),(10.46,2.3),(9.34,2.3),(9.34,4.42),(6.32,4.42),(6.32,2.3),(5.3,2.3),(5.3,0.56)],
  [(10.9,2.235),(10.9,2.74),(10.6,2.74),(10.6,4.18),(11.1,4.18),(11.1,2.595),(11.26,2.595),(11.26,2.235)],
  [(11.8,0.655),(11.8,1.885),(11.9,1.885),(11.9,4.475),(12.4,4.475),(12.4,0.655)],
  [(13.36,0.655),(13.36,1.965),(13.06,1.965),(13.06,4.475),(13.56,4.475),(13.56,1.965),(13.96,1.965),(13.96,0.655)],
  [(15.2,0.125),(15.2,2.05),(14.185,2.05),(14.185,2.41),(15.2,2.41),(15.2,4.915),(15.7,4.915),(15.7,1.885),(15.8,1.885),(15.8,0.125)])
R(gf180mcu_fd_sc_mcu9t5v0_, pplus, [(-0.2,2.265,17,5.24)])
R(gf180mcu_fd_sc_mcu9t5v0_, nplus, [(-0.2,-0.2,17,2.265)])
R(gf180mcu_fd_sc_mcu9t5v0_, contact, [(7.63,0.345,7.85,0.565), (12.77,0.345,12.99,0.565), (15.95,0.415,16.17,0.635), (9.41,0.685,9.63,0.905), (3.21,0.85,3.43,1.07), (15.95,0.885,16.17,1.105), (1.37,0.945,1.59,1.165), (11.43,0.945,11.65,1.165), (4.33,1.08,4.55,1.3), (5.45,1.08,5.67,1.3), (0.25,1.375,0.47,1.595), (2.49,1.375,2.71,1.595), (8.97,1.375,9.19,1.595), (10.09,1.375,10.31,1.595), (14.11,1.375,14.33,1.595), (14.83,1.375,15.05,1.595), (6.13,1.54,6.35,1.76), (1.81,1.835,2.03,2.055), (8.29,2,8.51,2.22), (14.255,2.12,14.475,2.34), (12.11,2.235,12.33,2.455), (0.79,2.295,1.01,2.515), (10.97,2.305,11.19,2.525), (3.89,2.335,4.11,2.555), (6.97,2.57,7.19,2.79), (13.13,2.765,13.35,2.985), (2.39,2.935,2.61,3.155), (13.93,2.935,14.15,3.155), (14.83,2.935,15.05,3.155), (0.35,3,0.57,3.22), (4.43,3.03,4.65,3.25), (5.45,3.03,5.67,3.25), (8.97,3.03,9.19,3.25), (10.09,3.03,10.31,3.25), (7.41,3.2,7.63,3.42), (11.53,3.45,11.75,3.67), (0.35,3.47,0.57,3.69), (1.37,3.485,1.59,3.705), (4.43,3.5,4.65,3.72), (5.45,3.5,5.67,3.72), (8.97,3.5,9.19,3.72), (10.09,3.5,10.31,3.72), (3.31,3.67,3.53,3.89), (7.41,3.67,7.63,3.89), (15.85,3.935,16.07,4.155), (1.37,3.955,1.59,4.175), (12.55,3.965,12.77,4.185), (5.89,4.13,6.11,4.35), (15.85,4.405,16.07,4.625)])
R(gf180mcu_fd_sc_mcu9t5v0_, metal1, [(14.71,1.315,15.055,3.215), (0.71,2.235,1.57,2.71), (3.45,2.33,4.33,2.71)])
P(gf180mcu_fd_sc_mcu9t5v0_, metal1, [(0.245,1.315),(0.245,1.74),(1.805,1.74),(1.805,2.94),(0.345,2.94),(0.345,3.75),(0.575,3.75),(0.575,3.17),(2.035,3.17),(2.035,1.51),(0.475,1.51),(0.475,1.315)],
  [(4.325,1.02),(4.325,1.36),(4.56,1.36),(4.56,2.97),(4.425,2.97),(4.425,3.78),(4.79,3.78),(4.79,1.02)],
  [(2.385,1.315),(2.385,3.22),(3.765,3.22),(3.765,4.355),(6.17,4.355),(6.17,4.125),(3.995,4.125),(3.995,2.99),(2.715,2.99),(2.715,1.315)],
  [(5.445,1.02),(5.445,3.78),(5.675,3.78),(5.675,2.28),(8.515,2.28),(8.515,1.94),(8.285,1.94),(8.285,2.05),(5.675,2.05),(5.675,1.02)],
  [(8.965,1.315),(8.965,2.51),(6.965,2.51),(6.965,2.85),(8.965,2.85),(8.965,3.78),(9.195,3.78),(9.195,1.315)],
  [(9.35,0.68),(9.35,0.855),(6.125,0.855),(6.125,1.82),(6.355,1.82),(6.355,1.085),(10.545,1.085),(10.545,2.53),(11.25,2.53),(11.25,2.3),(10.775,2.3),(10.775,0.68)],
  [(10.085,1.315),(10.085,3.78),(10.315,3.78),(10.315,2.99),(13.41,2.99),(13.41,2.76),(10.315,2.76),(10.315,1.315)],
  [(14.105,1.315),(14.105,2.23),(12.05,2.23),(12.05,2.46),(13.925,2.46),(13.925,3.215),(14.155,3.215),(14.155,2.455),(14.48,2.455),(14.48,1.315)],
  [(11.425,0.855),(11.425,1.225),(11.655,1.225),(11.655,1.085),(15.285,1.085),(15.285,3.445),(11.47,3.445),(11.47,3.675),(15.515,3.675),(15.515,0.855)],
  [(0,-0.45),(0,0.45),(1.365,0.45),(1.365,1.225),(1.595,1.225),(1.595,0.45),(3.205,0.45),(3.205,1.13),(3.435,1.13),(3.435,0.45),(7.625,0.45),(7.625,0.625),(7.855,0.625),(7.855,0.45),(12.765,0.45),(12.765,0.625),(12.995,0.625),(12.995,0.45),(15.945,0.45),(15.945,1.165),(16.175,1.165),(16.175,0.45),(16.8,0.45),(16.8,-0.45)],
  [(7.405,3.14),(7.405,4.59),(3.535,4.59),(3.535,3.61),(3.305,3.61),(3.305,4.59),(1.595,4.59),(1.595,3.425),(1.365,3.425),(1.365,4.59),(0,4.59),(0,5.49),(16.8,5.49),(16.8,4.59),(16.075,4.59),(16.075,3.875),(15.845,3.875),(15.845,4.59),(12.775,4.59),(12.775,3.905),(12.545,3.905),(12.545,4.59),(7.635,4.59),(7.635,3.14)])
R(gf180mcu_fd_sc_mcu9t5v0_, dualgate, [(-0.28,-0.28,17.08,5.32)])
R(gf180mcu_fd_sc_mcu9t5v0_, v5_xtor, [(0,0,16.8,5.04)])
R(gf180mcu_fd_sc_mcu9t5v0_, lvpwell, [(-0.43,-0.43,17.23,2.265)])
gf180mcu_fd_sc_mcu9t5v0_.add(gdstk.Label('CLKN', (1.4,2.52), layer=34, texttype=10))
gf180mcu_fd_sc_mcu9t5v0_.add(gdstk.Label('D', (3.64,2.52), layer=34, texttype=10))
gf180mcu_fd_sc_mcu9t5v0_.add(gdstk.Label('Q', (14.84,2.52), layer=34, texttype=10))
gf180mcu_fd_sc_mcu9t5v0_.add(gdstk.Label('VDD', (1.48,4.59), layer=34, texttype=10))
gf180mcu_fd_sc_mcu9t5v0_.add(gdstk.Label('VSS', (16.06,0.45), layer=34, texttype=10))
gf180mcu_fd_sc_mcu9t5v0_.add(gdstk.Label('& Vendor GLOBALFOUNDRIES', (0,2), layer=63, texttype=63))
gf180mcu_fd_sc_mcu9t5v0_.add(gdstk.Label('& Product GF018hv5v_green_sc9', (0,1.5), layer=63, texttype=63))
gf180mcu_fd_sc_mcu9t5v0_.add(gdstk.Label('& Version 2015q2v2', (0,1), layer=63, texttype=63))
gf180mcu_fd_sc_mcu9t5v0_.add(gdstk.Label('& Metric 1.00', (0,0.5), layer=63, texttype=63))
gf180mcu_fd_sc_mcu9t5v0_.add(gdstk.Label('VNW', (0.345,3.92), layer=21, texttype=10))
gf180mcu_fd_sc_mcu9t5v0_.add(gdstk.Label('VPW', (0.34,-0.085), layer=204, texttype=10))

lib.write_gds('gf180mcu_fd_sc_mcu9t5v0__dffnq_1.gds')
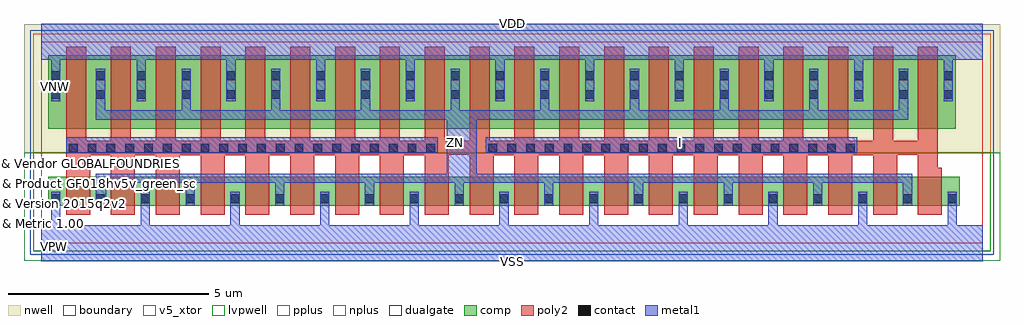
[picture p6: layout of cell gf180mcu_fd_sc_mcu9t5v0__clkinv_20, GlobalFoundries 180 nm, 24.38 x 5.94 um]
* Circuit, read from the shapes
.subckt gf180mcu_fd_sc_mcu9t5v0__clkinv_20 I VDD VNW VSS ZN
XM1 ZN I VSS VSUBS nfet_05v0 w=0.73u l=0.6u m=20
XM2 ZN I VDD VNW pfet_05v0 w=1.83u l=0.5u m=20
.ends

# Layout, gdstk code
import gdstk
lib = gdstk.Library(unit=1e-6, precision=1e-09)
def R(c, l, rs):  # rectangles x0, y0, x1, y1
    for r in rs: c.add(gdstk.rectangle(r[:2], r[2:], *l))
def A(c, l, x, y, w, h, nx, ny, dx, dy):  # array of equal rectangles
    R(c, l, [(x+i*dx, y+j*dy, x+i*dx+w, y+j*dy+h) for i in range(nx) for j in range(ny)])
def P(c, l, *ps):  # polygons
    for p in ps: c.add(gdstk.Polygon(p, *l))
boundary = (0, 0)
nwell = (21, 0)
comp = (22, 0)
poly2 = (30, 0)
pplus = (31, 0)
nplus = (32, 0)
contact = (33, 0)
metal1 = (34, 0)
dualgate = (55, 0)
v5_xtor = (112, 1)
lvpwell = (204, 0)

gf180mcu_fd_sc_mcu9t5v0_ = lib.new_cell('gf180mcu_fd_sc_mcu9t5v0__clkinv_20')
R(gf180mcu_fd_sc_mcu9t5v0_, boundary, [(0,0,23.52,5.04)])
R(gf180mcu_fd_sc_mcu9t5v0_, nwell, [(-0.43,2.265,23.95,5.47)])
R(gf180mcu_fd_sc_mcu9t5v0_, comp, [(0.18,0.935,22.94,1.665), (0.18,2.865,22.84,4.695)])
P(gf180mcu_fd_sc_mcu9t5v0_, poly2, [(0.62,0.715),(0.62,4.915),(1.12,4.915),(1.12,2.565),(1.74,2.565),(1.74,4.915),(2.24,4.915),(2.24,2.565),(2.86,2.565),(2.86,4.915),(3.36,4.915),(3.36,2.565),(3.98,2.565),(3.98,4.915),(4.48,4.915),(4.48,2.565),(5.1,2.565),(5.1,4.915),(5.6,4.915),(5.6,2.565),(6.22,2.565),(6.22,4.915),(6.72,4.915),(6.72,2.565),(7.34,2.565),(7.34,4.915),(7.84,4.915),(7.84,2.565),(8.46,2.565),(8.46,4.915),(8.96,4.915),(8.96,2.565),(9.58,2.565),(9.58,4.915),(10.08,4.915),(10.08,2.565),(10.7,2.565),(10.7,4.915),(11.2,4.915),(11.2,2.565),(11.82,2.565),(11.82,4.915),(12.32,4.915),(12.32,2.565),(12.94,2.565),(12.94,4.915),(13.44,4.915),(13.44,2.565),(14.06,2.565),(14.06,4.915),(14.56,4.915),(14.56,2.565),(15.18,2.565),(15.18,4.915),(15.68,4.915),(15.68,2.565),(16.3,2.565),(16.3,4.915),(16.8,4.915),(16.8,2.565),(17.42,2.565),(17.42,4.915),(17.92,4.915),(17.92,2.565),(18.54,2.565),(18.54,4.915),(19.04,4.915),(19.04,2.565),(19.66,2.565),(19.66,4.915),(20.16,4.915),(20.16,2.565),(20.78,2.565),(20.78,4.915),(21.28,4.915),(21.28,2.56),(21.9,2.56),(21.9,4.915),(22.4,4.915),(22.4,1.885),(22.5,1.885),(22.5,0.715),(21.9,0.715),(21.9,2.21),(21.38,2.21),(21.38,0.715),(20.78,0.715),(20.78,2.205),(20.26,2.205),(20.26,0.715),(19.66,0.715),(19.66,2.205),(19.14,2.205),(19.14,0.715),(18.54,0.715),(18.54,2.205),(18.02,2.205),(18.02,0.715),(17.42,0.715),(17.42,2.205),(16.9,2.205),(16.9,0.715),(16.3,0.715),(16.3,2.205),(15.78,2.205),(15.78,0.715),(15.18,0.715),(15.18,2.205),(14.66,2.205),(14.66,0.715),(14.06,0.715),(14.06,2.205),(13.54,2.205),(13.54,0.715),(12.94,0.715),(12.94,2.205),(12.42,2.205),(12.42,0.715),(11.82,0.715),(11.82,2.205),(11.3,2.205),(11.3,0.715),(10.7,0.715),(10.7,2.21),(10.18,2.21),(10.18,0.715),(9.58,0.715),(9.58,2.205),(9.06,2.205),(9.06,0.715),(8.46,0.715),(8.46,2.205),(7.94,2.205),(7.94,0.715),(7.34,0.715),(7.34,2.205),(6.82,2.205),(6.82,0.715),(6.22,0.715),(6.22,2.205),(5.7,2.205),(5.7,0.715),(5.1,0.715),(5.1,2.205),(4.58,2.205),(4.58,0.715),(3.98,0.715),(3.98,2.205),(3.46,2.205),(3.46,0.715),(2.86,0.715),(2.86,2.205),(2.34,2.205),(2.34,0.715),(1.74,0.715),(1.74,2.205),(1.22,2.205),(1.22,0.715)])
R(gf180mcu_fd_sc_mcu9t5v0_, pplus, [(-0.2,2.265,23.72,5.24)])
R(gf180mcu_fd_sc_mcu9t5v0_, nplus, [(-0.2,-0.2,23.72,2.265)])
A(gf180mcu_fd_sc_mcu9t5v0_, contact, 0.25, 1.005, 0.22, 0.22, 21, 1, 1.12, 0)
A(gf180mcu_fd_sc_mcu9t5v0_, contact, 0.69, 2.275, 0.22, 0.22, 20, 1, 0.47, 0)
A(gf180mcu_fd_sc_mcu9t5v0_, contact, 11.17, 2.275, 0.22, 0.22, 20, 1, 0.47, 0)
A(gf180mcu_fd_sc_mcu9t5v0_, contact, 2.39, 3.61, 0.22, 0.22, 19, 2, 1.12, 0.47)
R(gf180mcu_fd_sc_mcu9t5v0_, contact, [(0.25,3.61,0.47,3.83), (1.37,3.61,1.59,3.83), (0.25,4.08,0.47,4.3), (1.37,4.08,1.59,4.3)])
R(gf180mcu_fd_sc_mcu9t5v0_, metal1, [(0.63,2.27,9.9,2.65), (11.11,2.27,20.38,2.65)])
P(gf180mcu_fd_sc_mcu9t5v0_, metal1, [(1.365,0.945),(1.365,1.745),(10.13,1.745),(10.13,3.09),(1.365,3.09),(1.365,4.36),(1.595,4.36),(1.595,3.32),(3.505,3.32),(3.505,4.36),(3.735,4.36),(3.735,3.32),(5.745,3.32),(5.745,4.36),(5.975,4.36),(5.975,3.32),(7.985,3.32),(7.985,4.36),(8.215,4.36),(8.215,3.32),(10.225,3.32),(10.225,4.36),(10.455,4.36),(10.455,3.32),(12.465,3.32),(12.465,4.36),(12.695,4.36),(12.695,3.32),(14.705,3.32),(14.705,4.36),(14.935,4.36),(14.935,3.32),(16.945,3.32),(16.945,4.36),(17.175,4.36),(17.175,3.32),(19.185,3.32),(19.185,4.36),(19.415,4.36),(19.415,3.32),(21.425,3.32),(21.425,4.36),(21.655,4.36),(21.655,3.09),(10.88,3.09),(10.88,1.745),(21.755,1.745),(21.755,0.945),(21.525,0.945),(21.525,1.515),(19.515,1.515),(19.515,0.945),(19.285,0.945),(19.285,1.515),(17.275,1.515),(17.275,0.945),(17.045,0.945),(17.045,1.515),(15.035,1.515),(15.035,0.945),(14.805,0.945),(14.805,1.515),(12.795,1.515),(12.795,0.945),(12.565,0.945),(12.565,1.515),(10.555,1.515),(10.555,0.945),(10.325,0.945),(10.325,1.515),(8.315,1.515),(8.315,0.945),(8.085,0.945),(8.085,1.515),(6.075,1.515),(6.075,0.945),(5.845,0.945),(5.845,1.515),(3.835,1.515),(3.835,0.945),(3.605,0.945),(3.605,1.515),(1.625,1.515),(1.625,0.945)],
  [(0,-0.45),(0,0.45),(0.245,0.45),(0.245,1.285),(0.475,1.285),(0.475,0.45),(2.485,0.45),(2.485,1.285),(2.715,1.285),(2.715,0.45),(4.725,0.45),(4.725,1.285),(4.955,1.285),(4.955,0.45),(6.965,0.45),(6.965,1.285),(7.195,1.285),(7.195,0.45),(9.205,0.45),(9.205,1.285),(9.435,1.285),(9.435,0.45),(11.445,0.45),(11.445,1.285),(11.675,1.285),(11.675,0.45),(13.685,0.45),(13.685,1.285),(13.915,1.285),(13.915,0.45),(15.925,0.45),(15.925,1.285),(16.155,1.285),(16.155,0.45),(18.165,0.45),(18.165,1.285),(18.395,1.285),(18.395,0.45),(20.405,0.45),(20.405,1.285),(20.635,1.285),(20.635,0.45),(22.645,0.45),(22.645,1.285),(22.875,1.285),(22.875,0.45),(23.52,0.45),(23.52,-0.45)],
  [(0.245,3.55),(0.245,4.59),(0,4.59),(0,5.49),(23.52,5.49),(23.52,4.59),(22.775,4.59),(22.775,3.55),(22.545,3.55),(22.545,4.59),(20.535,4.59),(20.535,3.55),(20.305,3.55),(20.305,4.59),(18.295,4.59),(18.295,3.55),(18.065,3.55),(18.065,4.59),(16.055,4.59),(16.055,3.55),(15.825,3.55),(15.825,4.59),(13.815,4.59),(13.815,3.55),(13.585,3.55),(13.585,4.59),(11.575,4.59),(11.575,3.55),(11.345,3.55),(11.345,4.59),(9.335,4.59),(9.335,3.55),(9.105,3.55),(9.105,4.59),(7.095,4.59),(7.095,3.55),(6.865,3.55),(6.865,4.59),(4.855,4.59),(4.855,3.55),(4.625,3.55),(4.625,4.59),(2.615,4.59),(2.615,3.55),(2.385,3.55),(2.385,4.59),(0.475,4.59),(0.475,3.55)])
R(gf180mcu_fd_sc_mcu9t5v0_, dualgate, [(-0.28,-0.28,23.8,5.32)])
R(gf180mcu_fd_sc_mcu9t5v0_, v5_xtor, [(0,0,23.52,5.04)])
R(gf180mcu_fd_sc_mcu9t5v0_, lvpwell, [(-0.43,-0.43,23.95,2.265)])
gf180mcu_fd_sc_mcu9t5v0_.add(gdstk.Label('I', (15.96,2.52), layer=34, texttype=10))
gf180mcu_fd_sc_mcu9t5v0_.add(gdstk.Label('VDD', (11.76,5.49), layer=34, texttype=10))
gf180mcu_fd_sc_mcu9t5v0_.add(gdstk.Label('VSS', (11.76,-0.45), layer=34, texttype=10))
gf180mcu_fd_sc_mcu9t5v0_.add(gdstk.Label('ZN', (10.36,2.52), layer=34, texttype=10))
gf180mcu_fd_sc_mcu9t5v0_.add(gdstk.Label('& Vendor GLOBALFOUNDRIES', (0,2), layer=63, texttype=63))
gf180mcu_fd_sc_mcu9t5v0_.add(gdstk.Label('& Product GF018hv5v_green_sc9', (0,1.5), layer=63, texttype=63))
gf180mcu_fd_sc_mcu9t5v0_.add(gdstk.Label('& Version 2015q2v2', (0,1), layer=63, texttype=63))
gf180mcu_fd_sc_mcu9t5v0_.add(gdstk.Label('& Metric 1.00', (0,0.5), layer=63, texttype=63))
gf180mcu_fd_sc_mcu9t5v0_.add(gdstk.Label('VNW', (0.345,3.92), layer=21, texttype=10))
gf180mcu_fd_sc_mcu9t5v0_.add(gdstk.Label('VPW', (0.34,-0.085), layer=204, texttype=10))

lib.write_gds('gf180mcu_fd_sc_mcu9t5v0__clkinv_20.gds')
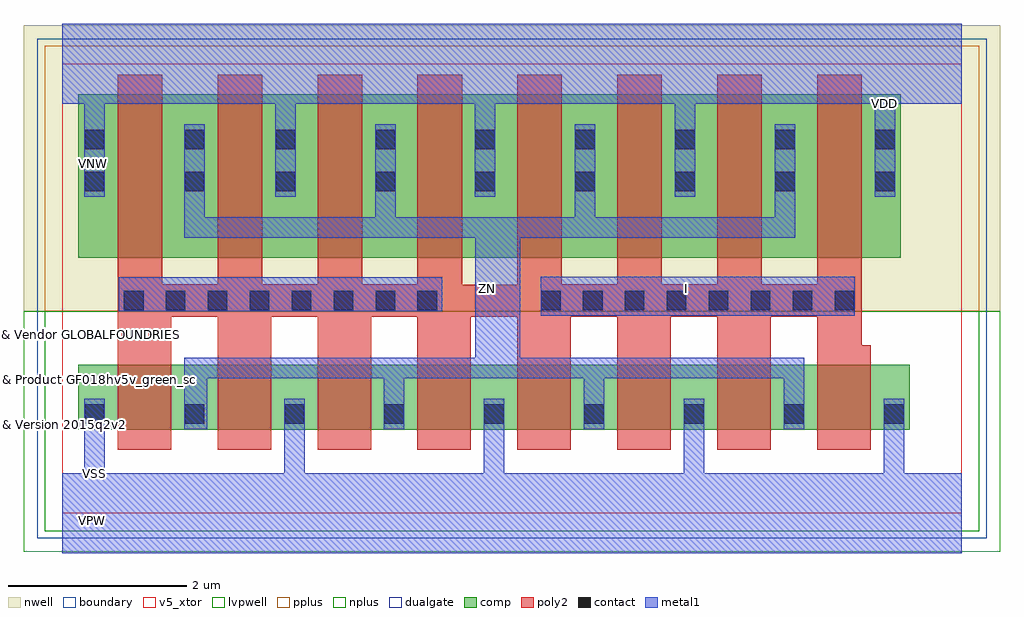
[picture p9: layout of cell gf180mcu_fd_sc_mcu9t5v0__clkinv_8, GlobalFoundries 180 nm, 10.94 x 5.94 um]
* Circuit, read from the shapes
.subckt gf180mcu_fd_sc_mcu9t5v0__clkinv_8 I VDD VNW VSS ZN
XM1 ZN I VSS VSUBS nfet_05v0 w=0.73u l=0.6u m=8
XM2 ZN I VDD VNW pfet_05v0 w=1.83u l=0.5u m=8
.ends

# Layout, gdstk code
import gdstk
lib = gdstk.Library(unit=1e-6, precision=1e-09)
def R(c, l, rs):  # rectangles x0, y0, x1, y1
    for r in rs: c.add(gdstk.rectangle(r[:2], r[2:], *l))
def A(c, l, x, y, w, h, nx, ny, dx, dy):  # array of equal rectangles
    R(c, l, [(x+i*dx, y+j*dy, x+i*dx+w, y+j*dy+h) for i in range(nx) for j in range(ny)])
def P(c, l, *ps):  # polygons
    for p in ps: c.add(gdstk.Polygon(p, *l))
boundary = (0, 0)
nwell = (21, 0)
comp = (22, 0)
poly2 = (30, 0)
pplus = (31, 0)
nplus = (32, 0)
contact = (33, 0)
metal1 = (34, 0)
dualgate = (55, 0)
v5_xtor = (112, 1)
lvpwell = (204, 0)

gf180mcu_fd_sc_mcu9t5v0_ = lib.new_cell('gf180mcu_fd_sc_mcu9t5v0__clkinv_8')
R(gf180mcu_fd_sc_mcu9t5v0_, boundary, [(0,0,10.08,5.04)])
R(gf180mcu_fd_sc_mcu9t5v0_, nwell, [(-0.43,2.265,10.51,5.47)])
R(gf180mcu_fd_sc_mcu9t5v0_, comp, [(0.18,0.935,9.5,1.665), (0.18,2.865,9.4,4.695)])
P(gf180mcu_fd_sc_mcu9t5v0_, poly2, [(0.62,0.715),(0.62,4.915),(1.12,4.915),(1.12,2.565),(1.74,2.565),(1.74,4.915),(2.24,4.915),(2.24,2.565),(2.86,2.565),(2.86,4.915),(3.36,4.915),(3.36,2.565),(3.98,2.565),(3.98,4.915),(4.48,4.915),(4.48,2.56),(5.1,2.56),(5.1,4.915),(5.6,4.915),(5.6,2.565),(6.22,2.565),(6.22,4.915),(6.72,4.915),(6.72,2.565),(7.34,2.565),(7.34,4.915),(7.84,4.915),(7.84,2.565),(8.46,2.565),(8.46,4.915),(8.96,4.915),(8.96,1.885),(9.06,1.885),(9.06,0.715),(8.46,0.715),(8.46,2.205),(7.94,2.205),(7.94,0.715),(7.34,0.715),(7.34,2.205),(6.82,2.205),(6.82,0.715),(6.22,0.715),(6.22,2.205),(5.7,2.205),(5.7,0.715),(5.1,0.715),(5.1,2.205),(4.58,2.205),(4.58,0.715),(3.98,0.715),(3.98,2.205),(3.46,2.205),(3.46,0.715),(2.86,0.715),(2.86,2.205),(2.34,2.205),(2.34,0.715),(1.74,0.715),(1.74,2.205),(1.22,2.205),(1.22,0.715)])
R(gf180mcu_fd_sc_mcu9t5v0_, pplus, [(-0.2,2.265,10.28,5.24)])
R(gf180mcu_fd_sc_mcu9t5v0_, nplus, [(-0.2,-0.2,10.28,2.265)])
A(gf180mcu_fd_sc_mcu9t5v0_, contact, 0.25, 1.005, 0.22, 0.22, 9, 1, 1.12, 0)
A(gf180mcu_fd_sc_mcu9t5v0_, contact, 0.69, 2.275, 0.22, 0.22, 8, 1, 0.47, 0)
A(gf180mcu_fd_sc_mcu9t5v0_, contact, 5.365, 2.275, 0.22, 0.22, 8, 1, 0.47, 0)
A(gf180mcu_fd_sc_mcu9t5v0_, contact, 2.39, 3.61, 0.22, 0.22, 7, 2, 1.12, 0.47)
R(gf180mcu_fd_sc_mcu9t5v0_, contact, [(0.25,3.61,0.47,3.83), (1.37,3.61,1.59,3.83), (0.25,4.08,0.47,4.3), (1.37,4.08,1.59,4.3)])
R(gf180mcu_fd_sc_mcu9t5v0_, metal1, [(5.36,2.215,8.88,2.65), (0.63,2.265,4.26,2.645)])
P(gf180mcu_fd_sc_mcu9t5v0_, metal1, [(1.365,0.945),(1.365,1.745),(4.63,1.745),(4.63,3.09),(1.365,3.09),(1.365,4.36),(1.595,4.36),(1.595,3.32),(3.505,3.32),(3.505,4.36),(3.735,4.36),(3.735,3.32),(5.745,3.32),(5.745,4.36),(5.975,4.36),(5.975,3.32),(7.985,3.32),(7.985,4.36),(8.215,4.36),(8.215,3.09),(5.13,3.09),(5.13,1.745),(8.315,1.745),(8.315,0.945),(8.085,0.945),(8.085,1.515),(6.075,1.515),(6.075,0.945),(5.845,0.945),(5.845,1.515),(3.835,1.515),(3.835,0.945),(3.605,0.945),(3.605,1.515),(1.625,1.515),(1.625,0.945)],
  [(0,-0.45),(0,0.45),(0.245,0.45),(0.245,1.285),(0.475,1.285),(0.475,0.45),(2.485,0.45),(2.485,1.285),(2.715,1.285),(2.715,0.45),(4.725,0.45),(4.725,1.285),(4.955,1.285),(4.955,0.45),(6.965,0.45),(6.965,1.285),(7.195,1.285),(7.195,0.45),(9.205,0.45),(9.205,1.285),(9.435,1.285),(9.435,0.45),(10.08,0.45),(10.08,-0.45)],
  [(0.245,3.55),(0.245,4.59),(0,4.59),(0,5.49),(10.08,5.49),(10.08,4.59),(9.335,4.59),(9.335,3.55),(9.105,3.55),(9.105,4.59),(7.095,4.59),(7.095,3.55),(6.865,3.55),(6.865,4.59),(4.855,4.59),(4.855,3.55),(4.625,3.55),(4.625,4.59),(2.615,4.59),(2.615,3.55),(2.385,3.55),(2.385,4.59),(0.475,4.59),(0.475,3.55)])
R(gf180mcu_fd_sc_mcu9t5v0_, dualgate, [(-0.28,-0.28,10.36,5.32)])
R(gf180mcu_fd_sc_mcu9t5v0_, v5_xtor, [(0,0,10.08,5.04)])
R(gf180mcu_fd_sc_mcu9t5v0_, lvpwell, [(-0.43,-0.43,10.51,2.265)])
gf180mcu_fd_sc_mcu9t5v0_.add(gdstk.Label('I', (7,2.52), layer=34, texttype=10))
gf180mcu_fd_sc_mcu9t5v0_.add(gdstk.Label('VDD', (9.22,4.59), layer=34, texttype=10))
gf180mcu_fd_sc_mcu9t5v0_.add(gdstk.Label('VSS', (0.36,0.45), layer=34, texttype=10))
gf180mcu_fd_sc_mcu9t5v0_.add(gdstk.Label('ZN', (4.76,2.52), layer=34, texttype=10))
gf180mcu_fd_sc_mcu9t5v0_.add(gdstk.Label('& Vendor GLOBALFOUNDRIES', (0,2), layer=63, texttype=63))
gf180mcu_fd_sc_mcu9t5v0_.add(gdstk.Label('& Product GF018hv5v_green_sc9', (0,1.5), layer=63, texttype=63))
gf180mcu_fd_sc_mcu9t5v0_.add(gdstk.Label('& Version 2015q2v2', (0,1), layer=63, texttype=63))
gf180mcu_fd_sc_mcu9t5v0_.add(gdstk.Label('& Metric 1.00', (0,0.5), layer=63, texttype=63))
gf180mcu_fd_sc_mcu9t5v0_.add(gdstk.Label('VNW', (0.345,3.92), layer=21, texttype=10))
gf180mcu_fd_sc_mcu9t5v0_.add(gdstk.Label('VPW', (0.34,-0.085), layer=204, texttype=10))

lib.write_gds('gf180mcu_fd_sc_mcu9t5v0__clkinv_8.gds')
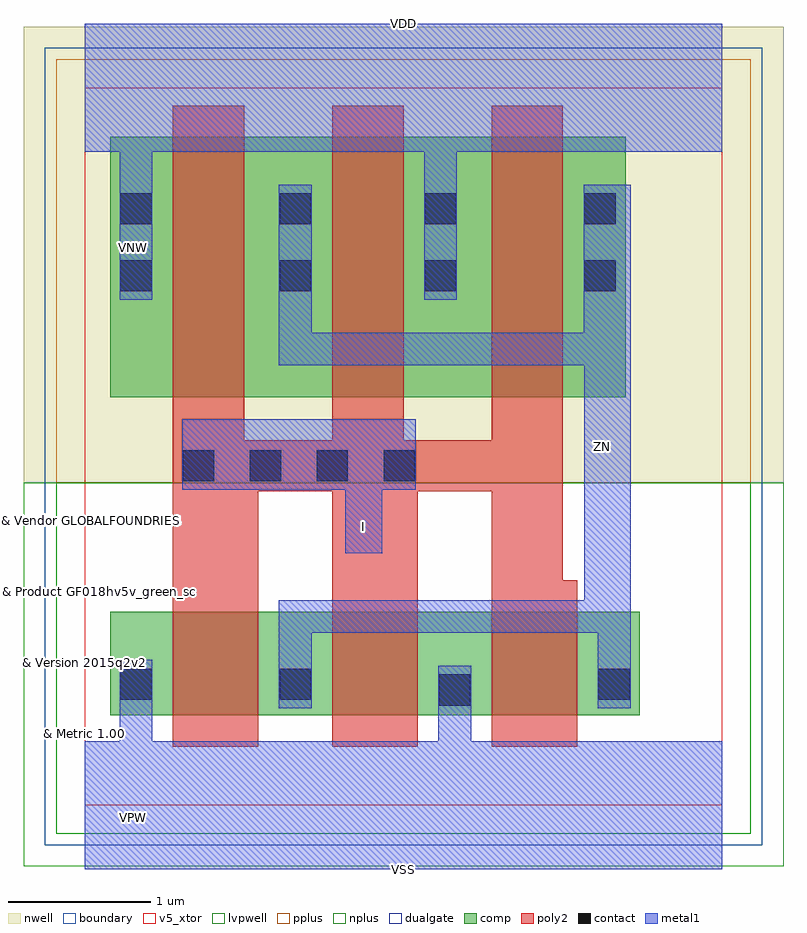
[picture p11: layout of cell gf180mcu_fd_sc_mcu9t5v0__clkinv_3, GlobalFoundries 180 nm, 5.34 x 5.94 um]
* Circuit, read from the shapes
.subckt gf180mcu_fd_sc_mcu9t5v0__clkinv_3 I VDD VNW VSS ZN
XM1 ZN I VSS VSUBS nfet_05v0 w=0.73u l=0.6u m=3
XM2 ZN I VDD VNW pfet_05v0 w=1.83u l=0.5u m=3
.ends

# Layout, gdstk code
import gdstk
lib = gdstk.Library(unit=1e-6, precision=1e-09)
def R(c, l, rs):  # rectangles x0, y0, x1, y1
    for r in rs: c.add(gdstk.rectangle(r[:2], r[2:], *l))
def A(c, l, x, y, w, h, nx, ny, dx, dy):  # array of equal rectangles
    R(c, l, [(x+i*dx, y+j*dy, x+i*dx+w, y+j*dy+h) for i in range(nx) for j in range(ny)])
def P(c, l, *ps):  # polygons
    for p in ps: c.add(gdstk.Polygon(p, *l))
boundary = (0, 0)
nwell = (21, 0)
comp = (22, 0)
poly2 = (30, 0)
pplus = (31, 0)
nplus = (32, 0)
contact = (33, 0)
metal1 = (34, 0)
dualgate = (55, 0)
v5_xtor = (112, 1)
lvpwell = (204, 0)

gf180mcu_fd_sc_mcu9t5v0_ = lib.new_cell('gf180mcu_fd_sc_mcu9t5v0__clkinv_3')
R(gf180mcu_fd_sc_mcu9t5v0_, boundary, [(0,0,4.48,5.04)])
R(gf180mcu_fd_sc_mcu9t5v0_, nwell, [(-0.43,2.265,4.91,5.47)])
R(gf180mcu_fd_sc_mcu9t5v0_, comp, [(0.18,0.63,3.9,1.36), (0.18,2.865,3.8,4.695)])
P(gf180mcu_fd_sc_mcu9t5v0_, poly2, [(0.62,0.41),(0.62,4.915),(1.12,4.915),(1.12,2.565),(1.74,2.565),(1.74,4.915),(2.24,4.915),(2.24,2.565),(2.86,2.565),(2.86,4.915),(3.36,4.915),(3.36,1.58),(3.46,1.58),(3.46,0.41),(2.86,0.41),(2.86,2.205),(2.34,2.205),(2.34,0.41),(1.74,0.41),(1.74,2.205),(1.22,2.205),(1.22,0.41)])
R(gf180mcu_fd_sc_mcu9t5v0_, pplus, [(-0.2,2.265,4.68,5.24)])
R(gf180mcu_fd_sc_mcu9t5v0_, nplus, [(-0.2,-0.2,4.68,2.265)])
A(gf180mcu_fd_sc_mcu9t5v0_, contact, 0.69, 2.275, 0.22, 0.22, 4, 1, 0.47, 0)
R(gf180mcu_fd_sc_mcu9t5v0_, contact, [(2.49,0.7,2.71,0.92), (0.25,0.74,0.47,0.96), (1.37,0.74,1.59,0.96), (3.61,0.74,3.83,0.96), (0.25,3.61,0.47,3.83), (1.37,3.61,1.59,3.83), (2.39,3.61,2.61,3.83), (3.51,3.61,3.73,3.83), (0.25,4.08,0.47,4.3), (1.37,4.08,1.59,4.3), (2.39,4.08,2.61,4.3), (3.51,4.08,3.73,4.3)])
P(gf180mcu_fd_sc_mcu9t5v0_, metal1, [(1.83,1.77),(1.83,2.215),(0.685,2.215),(0.685,2.71),(2.325,2.71),(2.325,2.215),(2.09,2.215),(2.09,1.77)],
  [(1.365,0.68),(1.365,1.44),(3.51,1.44),(3.51,3.09),(1.365,3.09),(1.365,4.36),(1.595,4.36),(1.595,3.32),(3.505,3.32),(3.505,4.36),(3.835,4.36),(3.835,0.68),(3.605,0.68),(3.605,1.21),(1.595,1.21),(1.595,0.68)],
  [(0,-0.45),(0,0.45),(0.245,0.45),(0.245,1.02),(0.475,1.02),(0.475,0.45),(2.485,0.45),(2.485,0.98),(2.715,0.98),(2.715,0.45),(4.48,0.45),(4.48,-0.45)],
  [(0.245,3.55),(0.245,4.59),(0,4.59),(0,5.49),(4.48,5.49),(4.48,4.59),(2.615,4.59),(2.615,3.55),(2.385,3.55),(2.385,4.59),(0.475,4.59),(0.475,3.55)])
R(gf180mcu_fd_sc_mcu9t5v0_, dualgate, [(-0.28,-0.28,4.76,5.32)])
R(gf180mcu_fd_sc_mcu9t5v0_, v5_xtor, [(0,0,4.48,5.04)])
R(gf180mcu_fd_sc_mcu9t5v0_, lvpwell, [(-0.43,-0.43,4.91,2.265)])
gf180mcu_fd_sc_mcu9t5v0_.add(gdstk.Label('I', (1.96,1.96), layer=34, texttype=10))
gf180mcu_fd_sc_mcu9t5v0_.add(gdstk.Label('VDD', (2.24,5.49), layer=34, texttype=10))
gf180mcu_fd_sc_mcu9t5v0_.add(gdstk.Label('VSS', (2.24,-0.45), layer=34, texttype=10))
gf180mcu_fd_sc_mcu9t5v0_.add(gdstk.Label('ZN', (3.64,2.52), layer=34, texttype=10))
gf180mcu_fd_sc_mcu9t5v0_.add(gdstk.Label('& Vendor GLOBALFOUNDRIES', (0,2), layer=63, texttype=63))
gf180mcu_fd_sc_mcu9t5v0_.add(gdstk.Label('& Product GF018hv5v_green_sc9', (0,1.5), layer=63, texttype=63))
gf180mcu_fd_sc_mcu9t5v0_.add(gdstk.Label('& Version 2015q2v2', (0,1), layer=63, texttype=63))
gf180mcu_fd_sc_mcu9t5v0_.add(gdstk.Label('& Metric 1.00', (0,0.5), layer=63, texttype=63))
gf180mcu_fd_sc_mcu9t5v0_.add(gdstk.Label('VNW', (0.345,3.92), layer=21, texttype=10))
gf180mcu_fd_sc_mcu9t5v0_.add(gdstk.Label('VPW', (0.34,-0.085), layer=204, texttype=10))

lib.write_gds('gf180mcu_fd_sc_mcu9t5v0__clkinv_3.gds')
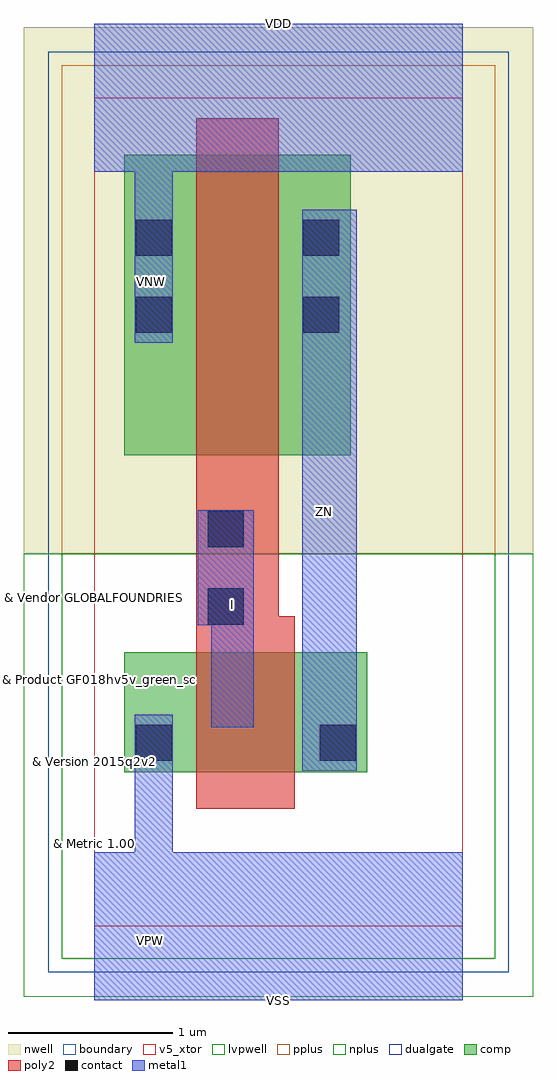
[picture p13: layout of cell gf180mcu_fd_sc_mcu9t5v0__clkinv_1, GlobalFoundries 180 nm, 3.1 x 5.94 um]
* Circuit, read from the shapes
.subckt gf180mcu_fd_sc_mcu9t5v0__clkinv_1 I VDD VNW VSS ZN
XM1 ZN I VSS VSUBS nfet_05v0 w=0.73u l=0.6u
XM2 ZN I VDD VNW pfet_05v0 w=1.83u l=0.5u
.ends

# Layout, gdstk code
import gdstk
lib = gdstk.Library(unit=1e-6, precision=1e-09)
def R(c, l, rs):  # rectangles x0, y0, x1, y1
    for r in rs: c.add(gdstk.rectangle(r[:2], r[2:], *l))
def P(c, l, *ps):  # polygons
    for p in ps: c.add(gdstk.Polygon(p, *l))
boundary = (0, 0)
nwell = (21, 0)
comp = (22, 0)
poly2 = (30, 0)
pplus = (31, 0)
nplus = (32, 0)
contact = (33, 0)
metal1 = (34, 0)
dualgate = (55, 0)
v5_xtor = (112, 1)
lvpwell = (204, 0)

gf180mcu_fd_sc_mcu9t5v0_ = lib.new_cell('gf180mcu_fd_sc_mcu9t5v0__clkinv_1')
R(gf180mcu_fd_sc_mcu9t5v0_, boundary, [(0,0,2.24,5.04)])
R(gf180mcu_fd_sc_mcu9t5v0_, nwell, [(-0.43,2.265,2.67,5.47)])
R(gf180mcu_fd_sc_mcu9t5v0_, comp, [(0.18,0.935,1.66,1.665), (0.18,2.865,1.56,4.695)])
P(gf180mcu_fd_sc_mcu9t5v0_, poly2, [(0.62,0.715),(0.62,4.915),(1.12,4.915),(1.12,1.885),(1.22,1.885),(1.22,0.715)])
R(gf180mcu_fd_sc_mcu9t5v0_, pplus, [(-0.2,2.265,2.44,5.24)])
R(gf180mcu_fd_sc_mcu9t5v0_, nplus, [(-0.2,-0.2,2.44,2.265)])
R(gf180mcu_fd_sc_mcu9t5v0_, contact, [(0.25,1.005,0.47,1.225), (1.37,1.005,1.59,1.225), (0.69,1.835,0.91,2.055), (0.69,2.305,0.91,2.525), (0.25,3.61,0.47,3.83), (1.27,3.61,1.49,3.83), (0.25,4.08,0.47,4.3), (1.27,4.08,1.49,4.3)])
R(gf180mcu_fd_sc_mcu9t5v0_, metal1, [(1.265,0.945,1.595,4.36)])
P(gf180mcu_fd_sc_mcu9t5v0_, metal1, [(0.71,1.21),(0.71,1.83),(0.63,1.83),(0.63,2.53),(0.97,2.53),(0.97,1.21)],
  [(0,-0.45),(0,0.45),(0.245,0.45),(0.245,1.285),(0.475,1.285),(0.475,0.45),(2.24,0.45),(2.24,-0.45)],
  [(0.245,3.55),(0.245,4.59),(0,4.59),(0,5.49),(2.24,5.49),(2.24,4.59),(0.475,4.59),(0.475,3.55)])
R(gf180mcu_fd_sc_mcu9t5v0_, dualgate, [(-0.28,-0.28,2.52,5.32)])
R(gf180mcu_fd_sc_mcu9t5v0_, v5_xtor, [(0,0,2.24,5.04)])
R(gf180mcu_fd_sc_mcu9t5v0_, lvpwell, [(-0.43,-0.43,2.67,2.265)])
gf180mcu_fd_sc_mcu9t5v0_.add(gdstk.Label('I', (0.84,1.96), layer=34, texttype=10))
gf180mcu_fd_sc_mcu9t5v0_.add(gdstk.Label('VDD', (1.12,5.49), layer=34, texttype=10))
gf180mcu_fd_sc_mcu9t5v0_.add(gdstk.Label('VSS', (1.12,-0.45), layer=34, texttype=10))
gf180mcu_fd_sc_mcu9t5v0_.add(gdstk.Label('ZN', (1.4,2.52), layer=34, texttype=10))
gf180mcu_fd_sc_mcu9t5v0_.add(gdstk.Label('& Vendor GLOBALFOUNDRIES', (0,2), layer=63, texttype=63))
gf180mcu_fd_sc_mcu9t5v0_.add(gdstk.Label('& Product GF018hv5v_green_sc9', (0,1.5), layer=63, texttype=63))
gf180mcu_fd_sc_mcu9t5v0_.add(gdstk.Label('& Version 2015q2v2', (0,1), layer=63, texttype=63))
gf180mcu_fd_sc_mcu9t5v0_.add(gdstk.Label('& Metric 1.00', (0,0.5), layer=63, texttype=63))
gf180mcu_fd_sc_mcu9t5v0_.add(gdstk.Label('VNW', (0.345,3.92), layer=21, texttype=10))
gf180mcu_fd_sc_mcu9t5v0_.add(gdstk.Label('VPW', (0.34,-0.085), layer=204, texttype=10))

lib.write_gds('gf180mcu_fd_sc_mcu9t5v0__clkinv_1.gds')
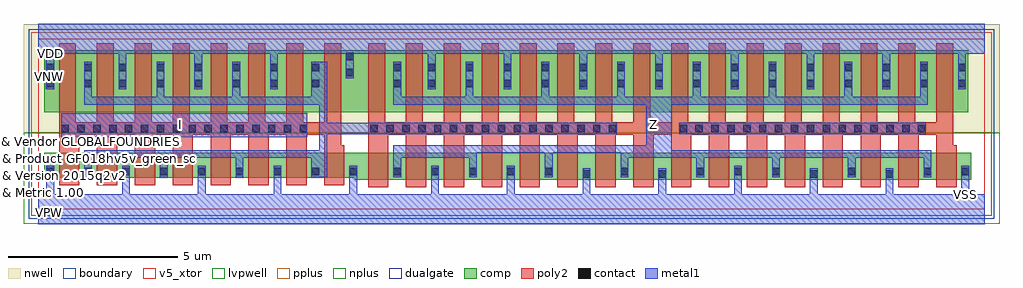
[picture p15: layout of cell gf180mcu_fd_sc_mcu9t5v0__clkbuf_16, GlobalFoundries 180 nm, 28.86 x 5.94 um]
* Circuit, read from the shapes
.subckt gf180mcu_fd_sc_mcu9t5v0__clkbuf_16 I VDD VNW VSS Z
XM1 n1 I VSS VSUBS nfet_05v0 w=0.73u l=0.6u m=8
XM2 Z n1 VSS VSUBS nfet_05v0 w=0.8u l=0.6u m=16
XM3 n1 I VDD VNW pfet_05v0 w=1.83u l=0.5u m=8
XM4 Z n1 VDD VNW pfet_05v0 w=1.83u l=0.5u m=16
.ends

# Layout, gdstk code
import gdstk
lib = gdstk.Library(unit=1e-6, precision=1e-09)
def R(c, l, rs):  # rectangles x0, y0, x1, y1
    for r in rs: c.add(gdstk.rectangle(r[:2], r[2:], *l))
def A(c, l, x, y, w, h, nx, ny, dx, dy):  # array of equal rectangles
    R(c, l, [(x+i*dx, y+j*dy, x+i*dx+w, y+j*dy+h) for i in range(nx) for j in range(ny)])
def P(c, l, *ps):  # polygons
    for p in ps: c.add(gdstk.Polygon(p, *l))
boundary = (0, 0)
nwell = (21, 0)
comp = (22, 0)
poly2 = (30, 0)
pplus = (31, 0)
nplus = (32, 0)
contact = (33, 0)
metal1 = (34, 0)
dualgate = (55, 0)
v5_xtor = (112, 1)
lvpwell = (204, 0)

gf180mcu_fd_sc_mcu9t5v0_ = lib.new_cell('gf180mcu_fd_sc_mcu9t5v0__clkbuf_16')
R(gf180mcu_fd_sc_mcu9t5v0_, boundary, [(0,0,28,5.04)])
R(gf180mcu_fd_sc_mcu9t5v0_, nwell, [(-0.43,2.265,28.43,5.47)])
R(gf180mcu_fd_sc_mcu9t5v0_, comp, [(0.18,2.865,27.5,4.695)])
P(gf180mcu_fd_sc_mcu9t5v0_, comp, [(9.36,0.865),(9.36,0.935),(0.18,0.935),(0.18,1.665),(27.6,1.665),(27.6,0.865)])
P(gf180mcu_fd_sc_mcu9t5v0_, poly2, [(0.62,0.715),(0.62,4.915),(1.12,4.915),(1.12,2.565),(1.74,2.565),(1.74,4.915),(2.24,4.915),(2.24,2.565),(2.86,2.565),(2.86,4.915),(3.36,4.915),(3.36,2.565),(3.98,2.565),(3.98,4.915),(4.48,4.915),(4.48,2.565),(5.1,2.565),(5.1,4.915),(5.6,4.915),(5.6,2.565),(6.22,2.565),(6.22,4.915),(6.72,4.915),(6.72,2.565),(7.34,2.565),(7.34,4.915),(7.84,4.915),(7.84,2.565),(8.46,2.565),(8.46,4.915),(8.96,4.915),(8.96,1.885),(9.06,1.885),(9.06,0.715),(8.46,0.715),(8.46,2.205),(7.94,2.205),(7.94,0.715),(7.34,0.715),(7.34,2.205),(6.82,2.205),(6.82,0.715),(6.22,0.715),(6.22,2.205),(5.7,2.205),(5.7,0.715),(5.1,0.715),(5.1,2.205),(4.58,2.205),(4.58,0.715),(3.98,0.715),(3.98,2.205),(3.46,2.205),(3.46,0.715),(2.86,0.715),(2.86,2.205),(2.34,2.205),(2.34,0.715),(1.74,0.715),(1.74,2.205),(1.22,2.205),(1.22,0.715)],
  [(9.76,0.645),(9.76,4.915),(10.26,4.915),(10.26,2.565),(10.88,2.565),(10.88,4.915),(11.38,4.915),(11.38,2.565),(12,2.565),(12,4.915),(12.5,4.915),(12.5,2.565),(13.12,2.565),(13.12,4.915),(13.62,4.915),(13.62,2.565),(14.24,2.565),(14.24,4.915),(14.74,4.915),(14.74,2.565),(15.36,2.565),(15.36,4.915),(15.86,4.915),(15.86,2.565),(16.48,2.565),(16.48,4.915),(16.98,4.915),(16.98,2.565),(17.6,2.565),(17.6,4.915),(18.1,4.915),(18.1,2.565),(18.72,2.565),(18.72,4.915),(19.22,4.915),(19.22,2.565),(19.84,2.565),(19.84,4.915),(20.34,4.915),(20.34,2.565),(20.96,2.565),(20.96,4.915),(21.46,4.915),(21.46,2.565),(22.08,2.565),(22.08,4.915),(22.58,4.915),(22.58,2.565),(23.2,2.565),(23.2,4.915),(23.7,4.915),(23.7,2.565),(24.32,2.565),(24.32,4.915),(24.82,4.915),(24.82,2.565),(25.44,2.565),(25.44,4.915),(25.94,4.915),(25.94,2.565),(26.56,2.565),(26.56,4.915),(27.06,4.915),(27.06,1.885),(27.16,1.885),(27.16,0.645),(26.56,0.645),(26.56,2.205),(26.04,2.205),(26.04,0.645),(25.44,0.645),(25.44,2.205),(24.92,2.205),(24.92,0.645),(24.32,0.645),(24.32,2.205),(23.8,2.205),(23.8,0.645),(23.2,0.645),(23.2,2.205),(22.68,2.205),(22.68,0.645),(22.08,0.645),(22.08,2.205),(21.56,2.205),(21.56,0.645),(20.96,0.645),(20.96,2.205),(20.44,2.205),(20.44,0.645),(19.84,0.645),(19.84,2.205),(19.32,2.205),(19.32,0.645),(18.72,0.645),(18.72,2.205),(18.2,2.205),(18.2,0.645),(17.6,0.645),(17.6,2.205),(17.08,2.205),(17.08,0.645),(16.48,0.645),(16.48,2.205),(15.96,2.205),(15.96,0.645),(15.36,0.645),(15.36,2.205),(14.84,2.205),(14.84,0.645),(14.24,0.645),(14.24,2.205),(13.72,2.205),(13.72,0.645),(13.12,0.645),(13.12,2.205),(12.6,2.205),(12.6,0.645),(12,0.645),(12,2.205),(11.48,2.205),(11.48,0.645),(10.88,0.645),(10.88,2.205),(10.36,2.205),(10.36,0.645)])
R(gf180mcu_fd_sc_mcu9t5v0_, pplus, [(-0.2,2.265,28.2,5.24)])
R(gf180mcu_fd_sc_mcu9t5v0_, nplus, [(-0.2,-0.2,28.2,2.265)])
A(gf180mcu_fd_sc_mcu9t5v0_, contact, 0.25, 1.005, 0.22, 0.22, 9, 1, 1.12, 0)
A(gf180mcu_fd_sc_mcu9t5v0_, contact, 10.51, 1.005, 0.22, 0.22, 5, 1, 1.12, 0)
A(gf180mcu_fd_sc_mcu9t5v0_, contact, 19.47, 1.005, 0.22, 0.22, 3, 1, 1.12, 0)
A(gf180mcu_fd_sc_mcu9t5v0_, contact, 0.69, 2.275, 0.22, 0.22, 16, 1, 0.47, 0)
A(gf180mcu_fd_sc_mcu9t5v0_, contact, 9.83, 2.275, 0.22, 0.22, 16, 1, 0.47, 0)
A(gf180mcu_fd_sc_mcu9t5v0_, contact, 18.97, 2.275, 0.22, 0.22, 16, 1, 0.47, 0)
A(gf180mcu_fd_sc_mcu9t5v0_, contact, 2.39, 3.61, 0.22, 0.22, 5, 2, 1.12, 0.47)
A(gf180mcu_fd_sc_mcu9t5v0_, contact, 11.53, 3.61, 0.22, 0.22, 15, 2, 1.12, 0.47)
R(gf180mcu_fd_sc_mcu9t5v0_, contact, [(16.11,0.935,16.33,1.155), (18.35,0.935,18.57,1.155), (22.83,0.935,23.05,1.155), (25.07,0.935,25.29,1.155), (17.23,1.005,17.45,1.225), (23.95,1.005,24.17,1.225), (26.19,1.005,26.41,1.225), (27.31,1.005,27.53,1.225), (0.25,3.61,0.47,3.83), (1.37,3.61,1.59,3.83), (8.09,3.61,8.31,3.83), (10.51,3.61,10.73,3.83), (9.11,3.935,9.33,4.155), (0.25,4.08,0.47,4.3), (1.37,4.08,1.59,4.3), (8.09,4.08,8.31,4.3), (10.51,4.08,10.73,4.3), (9.11,4.405,9.33,4.625)])
R(gf180mcu_fd_sc_mcu9t5v0_, metal1, [(0.685,2.125,7.965,2.84), (18.965,2.215,26.245,2.555)])
P(gf180mcu_fd_sc_mcu9t5v0_, metal1, [(1.365,0.945),(1.365,1.745),(8.32,1.745),(8.32,3.09),(1.365,3.09),(1.365,4.36),(1.595,4.36),(1.595,3.32),(3.505,3.32),(3.505,4.36),(3.735,4.36),(3.735,3.32),(5.745,3.32),(5.745,4.36),(5.975,4.36),(5.975,3.32),(8.085,3.32),(8.085,4.36),(8.55,4.36),(8.55,2.555),(17.105,2.555),(17.105,2.215),(8.55,2.215),(8.55,0.945),(8.085,0.945),(8.085,1.515),(6.075,1.515),(6.075,0.945),(5.845,0.945),(5.845,1.515),(3.835,1.515),(3.835,0.945),(3.605,0.945),(3.605,1.515),(1.595,1.515),(1.595,0.945)],
  [(10.505,0.945),(10.505,1.895),(17.985,1.895),(17.985,3.09),(10.505,3.09),(10.505,4.36),(10.735,4.36),(10.735,3.32),(12.645,3.32),(12.645,4.36),(12.875,4.36),(12.875,3.32),(14.885,3.32),(14.885,4.36),(15.115,4.36),(15.115,3.32),(17.125,3.32),(17.125,4.36),(17.355,4.36),(17.355,3.32),(19.365,3.32),(19.365,4.36),(19.595,4.36),(19.595,3.32),(21.605,3.32),(21.605,4.36),(21.835,4.36),(21.835,3.32),(23.845,3.32),(23.845,4.36),(24.075,4.36),(24.075,3.32),(26.085,3.32),(26.085,4.36),(26.315,4.36),(26.315,3.09),(18.735,3.09),(18.735,1.745),(26.415,1.745),(26.415,0.945),(26.185,0.945),(26.185,1.515),(24.175,1.515),(24.175,0.945),(23.945,0.945),(23.945,1.515),(21.935,1.515),(21.935,0.945),(21.705,0.945),(21.705,1.515),(19.695,1.515),(19.695,0.945),(19.465,0.945),(19.465,1.515),(17.455,1.515),(17.455,0.945),(17.225,0.945),(17.225,1.665),(15.215,1.665),(15.215,0.945),(14.985,0.945),(14.985,1.665),(12.975,1.665),(12.975,0.945),(12.745,0.945),(12.745,1.515),(10.735,1.515),(10.735,0.945)],
  [(0,-0.45),(0,0.45),(0.245,0.45),(0.245,1.285),(0.475,1.285),(0.475,0.45),(2.485,0.45),(2.485,1.285),(2.715,1.285),(2.715,0.45),(4.725,0.45),(4.725,1.285),(4.955,1.285),(4.955,0.45),(6.965,0.45),(6.965,1.285),(7.195,1.285),(7.195,0.45),(9.205,0.45),(9.205,1.285),(9.435,1.285),(9.435,0.45),(11.625,0.45),(11.625,1.285),(11.855,1.285),(11.855,0.45),(13.865,0.45),(13.865,1.285),(14.095,1.285),(14.095,0.45),(16.105,0.45),(16.105,1.215),(16.335,1.215),(16.335,0.45),(18.345,0.45),(18.345,1.215),(18.575,1.215),(18.575,0.45),(20.585,0.45),(20.585,1.285),(20.815,1.285),(20.815,0.45),(22.825,0.45),(22.825,1.215),(23.055,1.215),(23.055,0.45),(25.065,0.45),(25.065,1.215),(25.295,1.215),(25.295,0.45),(27.305,0.45),(27.305,1.285),(27.535,1.285),(27.535,0.45),(28,0.45),(28,-0.45)],
  [(0.245,3.55),(0.245,4.59),(0,4.59),(0,5.49),(28,5.49),(28,4.59),(27.435,4.59),(27.435,3.55),(27.205,3.55),(27.205,4.59),(25.195,4.59),(25.195,3.55),(24.965,3.55),(24.965,4.59),(22.955,4.59),(22.955,3.55),(22.725,3.55),(22.725,4.59),(20.715,4.59),(20.715,3.55),(20.485,3.55),(20.485,4.59),(18.475,4.59),(18.475,3.55),(18.245,3.55),(18.245,4.59),(16.235,4.59),(16.235,3.55),(16.005,3.55),(16.005,4.59),(13.995,4.59),(13.995,3.55),(13.765,3.55),(13.765,4.59),(11.755,4.59),(11.755,3.55),(11.525,3.55),(11.525,4.59),(9.335,4.59),(9.335,3.875),(9.105,3.875),(9.105,4.59),(7.095,4.59),(7.095,3.55),(6.865,3.55),(6.865,4.59),(4.855,4.59),(4.855,3.55),(4.625,3.55),(4.625,4.59),(2.615,4.59),(2.615,3.55),(2.385,3.55),(2.385,4.59),(0.475,4.59),(0.475,3.55)])
R(gf180mcu_fd_sc_mcu9t5v0_, dualgate, [(-0.28,-0.28,28.28,5.32)])
R(gf180mcu_fd_sc_mcu9t5v0_, v5_xtor, [(0,0,28,5.04)])
R(gf180mcu_fd_sc_mcu9t5v0_, lvpwell, [(-0.43,-0.43,28.43,2.265)])
gf180mcu_fd_sc_mcu9t5v0_.add(gdstk.Label('I', (4.2,2.52), layer=34, texttype=10))
gf180mcu_fd_sc_mcu9t5v0_.add(gdstk.Label('VDD', (0.36,4.59), layer=34, texttype=10))
gf180mcu_fd_sc_mcu9t5v0_.add(gdstk.Label('VSS', (27.42,0.45), layer=34, texttype=10))
gf180mcu_fd_sc_mcu9t5v0_.add(gdstk.Label('Z', (18.2,2.52), layer=34, texttype=10))
gf180mcu_fd_sc_mcu9t5v0_.add(gdstk.Label('& Vendor GLOBALFOUNDRIES', (0,2), layer=63, texttype=63))
gf180mcu_fd_sc_mcu9t5v0_.add(gdstk.Label('& Product GF018hv5v_green_sc9', (0,1.5), layer=63, texttype=63))
gf180mcu_fd_sc_mcu9t5v0_.add(gdstk.Label('& Version 2015q2v2', (0,1), layer=63, texttype=63))
gf180mcu_fd_sc_mcu9t5v0_.add(gdstk.Label('& Metric 1.00', (0,0.5), layer=63, texttype=63))
gf180mcu_fd_sc_mcu9t5v0_.add(gdstk.Label('VNW', (0.345,3.92), layer=21, texttype=10))
gf180mcu_fd_sc_mcu9t5v0_.add(gdstk.Label('VPW', (0.34,-0.085), layer=204, texttype=10))

lib.write_gds('gf180mcu_fd_sc_mcu9t5v0__clkbuf_16.gds')
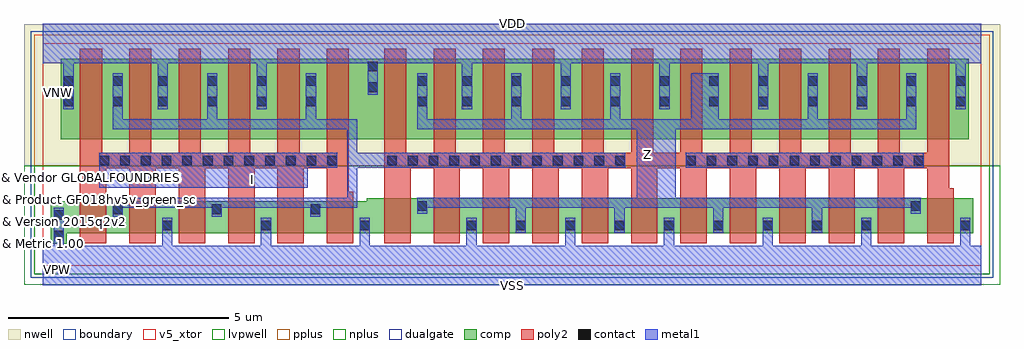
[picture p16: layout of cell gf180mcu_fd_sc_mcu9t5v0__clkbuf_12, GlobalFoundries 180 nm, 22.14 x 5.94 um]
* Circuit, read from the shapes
.subckt gf180mcu_fd_sc_mcu9t5v0__clkbuf_12 I VDD VNW VSS Z
XM1 n1 I VSS VSUBS nfet_05v0 w=0.73u l=0.6u m=6
XM2 Z n1 VSS VSUBS nfet_05v0 w=0.8u l=0.6u m=12
XM3 n1 I VDD VNW pfet_05v0 w=1.83u l=0.5u m=6
XM4 Z n1 VDD VNW pfet_05v0 w=1.83u l=0.5u m=12
.ends

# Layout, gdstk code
import gdstk
lib = gdstk.Library(unit=1e-6, precision=1e-09)
def R(c, l, rs):  # rectangles x0, y0, x1, y1
    for r in rs: c.add(gdstk.rectangle(r[:2], r[2:], *l))
def A(c, l, x, y, w, h, nx, ny, dx, dy):  # array of equal rectangles
    R(c, l, [(x+i*dx, y+j*dy, x+i*dx+w, y+j*dy+h) for i in range(nx) for j in range(ny)])
def P(c, l, *ps):  # polygons
    for p in ps: c.add(gdstk.Polygon(p, *l))
boundary = (0, 0)
nwell = (21, 0)
comp = (22, 0)
poly2 = (30, 0)
pplus = (31, 0)
nplus = (32, 0)
contact = (33, 0)
metal1 = (34, 0)
dualgate = (55, 0)
v5_xtor = (112, 1)
lvpwell = (204, 0)

gf180mcu_fd_sc_mcu9t5v0_ = lib.new_cell('gf180mcu_fd_sc_mcu9t5v0__clkbuf_12')
R(gf180mcu_fd_sc_mcu9t5v0_, boundary, [(0,0,21.28,5.04)])
R(gf180mcu_fd_sc_mcu9t5v0_, nwell, [(-0.43,2.265,21.71,5.47)])
R(gf180mcu_fd_sc_mcu9t5v0_, comp, [(0.4,2.865,21,4.695)])
P(gf180mcu_fd_sc_mcu9t5v0_, comp, [(0.18,0.495),(0.18,1.46),(7.34,1.46),(7.34,1.53),(21.1,1.53),(21.1,0.73),(0.54,0.73),(0.54,0.495)])
P(gf180mcu_fd_sc_mcu9t5v0_, poly2, [(0.84,0.51),(0.84,4.915),(1.34,4.915),(1.34,2.565),(1.96,2.565),(1.96,4.915),(2.46,4.915),(2.46,2.565),(3.08,2.565),(3.08,4.915),(3.58,4.915),(3.58,2.565),(4.2,2.565),(4.2,4.915),(4.7,4.915),(4.7,2.565),(5.32,2.565),(5.32,4.915),(5.82,4.915),(5.82,2.565),(6.44,2.565),(6.44,4.915),(6.94,4.915),(6.94,1.68),(7.04,1.68),(7.04,0.51),(6.44,0.51),(6.44,2.205),(5.92,2.205),(5.92,0.51),(5.32,0.51),(5.32,2.205),(4.8,2.205),(4.8,0.51),(4.2,0.51),(4.2,2.205),(3.68,2.205),(3.68,0.51),(3.08,0.51),(3.08,2.205),(2.56,2.205),(2.56,0.51),(1.96,0.51),(1.96,2.205),(1.44,2.205),(1.44,0.51)],
  [(7.74,0.51),(7.74,4.915),(8.24,4.915),(8.24,2.565),(8.86,2.565),(8.86,4.915),(9.36,4.915),(9.36,2.565),(9.98,2.565),(9.98,4.915),(10.48,4.915),(10.48,2.565),(11.1,2.565),(11.1,4.915),(11.6,4.915),(11.6,2.565),(12.22,2.565),(12.22,4.915),(12.72,4.915),(12.72,2.565),(13.34,2.565),(13.34,4.915),(13.84,4.915),(13.84,2.565),(14.46,2.565),(14.46,4.915),(14.96,4.915),(14.96,2.565),(15.58,2.565),(15.58,4.915),(16.08,4.915),(16.08,2.565),(16.7,2.565),(16.7,4.915),(17.2,4.915),(17.2,2.565),(17.82,2.565),(17.82,4.915),(18.32,4.915),(18.32,2.565),(18.94,2.565),(18.94,4.915),(19.44,4.915),(19.44,2.565),(20.06,2.565),(20.06,4.915),(20.56,4.915),(20.56,1.75),(20.66,1.75),(20.66,0.51),(20.06,0.51),(20.06,2.205),(19.54,2.205),(19.54,0.51),(18.94,0.51),(18.94,2.205),(18.42,2.205),(18.42,0.51),(17.82,0.51),(17.82,2.205),(17.3,2.205),(17.3,0.51),(16.7,0.51),(16.7,2.205),(16.18,2.205),(16.18,0.51),(15.58,0.51),(15.58,2.205),(15.06,2.205),(15.06,0.51),(14.46,0.51),(14.46,2.205),(13.94,2.205),(13.94,0.51),(13.34,0.51),(13.34,2.205),(12.82,2.205),(12.82,0.51),(12.22,0.51),(12.22,2.205),(11.7,2.205),(11.7,0.51),(11.1,0.51),(11.1,2.205),(10.58,2.205),(10.58,0.51),(9.98,0.51),(9.98,2.205),(9.46,2.205),(9.46,0.51),(8.86,0.51),(8.86,2.205),(8.34,2.205),(8.34,0.51)])
R(gf180mcu_fd_sc_mcu9t5v0_, pplus, [(-0.2,2.265,21.48,5.24)])
R(gf180mcu_fd_sc_mcu9t5v0_, nplus, [(-0.2,-0.2,21.48,2.265)])
A(gf180mcu_fd_sc_mcu9t5v0_, contact, 2.71, 0.8, 0.22, 0.22, 3, 1, 2.24, 0)
A(gf180mcu_fd_sc_mcu9t5v0_, contact, 9.61, 0.8, 0.22, 0.22, 9, 1, 1.12, 0)
A(gf180mcu_fd_sc_mcu9t5v0_, contact, 1.59, 1.17, 0.22, 0.22, 3, 1, 2.24, 0)
A(gf180mcu_fd_sc_mcu9t5v0_, contact, 1.28, 2.275, 0.22, 0.22, 12, 1, 0.47, 0)
A(gf180mcu_fd_sc_mcu9t5v0_, contact, 7.81, 2.275, 0.22, 0.22, 12, 1, 0.47, 0)
A(gf180mcu_fd_sc_mcu9t5v0_, contact, 14.585, 2.275, 0.22, 0.22, 12, 1, 0.47, 0)
A(gf180mcu_fd_sc_mcu9t5v0_, contact, 2.61, 3.61, 0.22, 0.22, 4, 2, 1.12, 0.47)
A(gf180mcu_fd_sc_mcu9t5v0_, contact, 9.51, 3.61, 0.22, 0.22, 11, 2, 1.12, 0.47)
R(gf180mcu_fd_sc_mcu9t5v0_, contact, [(0.25,0.565,0.47,0.785), (20.81,0.8,21.03,1.02), (0.25,1.035,0.47,1.255), (8.49,1.24,8.71,1.46), (19.69,1.24,19.91,1.46), (0.47,3.61,0.69,3.83), (1.59,3.61,1.81,3.83), (8.49,3.61,8.71,3.83), (7.37,3.935,7.59,4.155), (0.47,4.08,0.69,4.3), (1.59,4.08,1.81,4.3), (8.49,4.08,8.71,4.3), (7.37,4.405,7.59,4.625)])
R(gf180mcu_fd_sc_mcu9t5v0_, metal1, [(14.58,2.215,19.98,2.555)])
P(gf180mcu_fd_sc_mcu9t5v0_, metal1, [(1.275,1.77),(1.275,2.555),(6.675,2.555),(6.675,2.215),(6.01,2.215),(6.01,1.77)],
  [(1.585,1.11),(1.585,1.54),(6.905,1.54),(6.905,3.09),(1.585,3.09),(1.585,4.36),(1.815,4.36),(1.815,3.32),(3.725,3.32),(3.725,4.36),(3.955,4.36),(3.955,3.32),(5.965,3.32),(5.965,4.36),(6.195,4.36),(6.195,3.32),(7.135,3.32),(7.135,2.555),(13.205,2.555),(13.205,2.215),(7.135,2.215),(7.135,1.31),(6.295,1.31),(6.295,1.11),(6.065,1.11),(6.065,1.31),(4.055,1.31),(4.055,1.11),(3.825,1.11),(3.825,1.31),(1.815,1.31),(1.815,1.11)],
  [(10.725,0.74),(10.725,1.31),(8.715,1.31),(8.715,1.18),(8.485,1.18),(8.485,1.54),(13.465,1.54),(13.465,3.09),(8.485,3.09),(8.485,4.36),(8.715,4.36),(8.715,3.32),(10.625,3.32),(10.625,4.36),(10.855,4.36),(10.855,3.32),(12.865,3.32),(12.865,4.36),(13.095,4.36),(13.095,3.32),(14.71,3.32),(14.71,4.36),(15.335,4.36),(15.335,3.32),(17.345,3.32),(17.345,4.36),(17.575,4.36),(17.575,3.32),(19.585,3.32),(19.585,4.36),(19.815,4.36),(19.815,3.09),(14.35,3.09),(14.35,1.54),(19.915,1.54),(19.915,1.18),(19.685,1.18),(19.685,1.31),(17.675,1.31),(17.675,0.74),(17.445,0.74),(17.445,1.31),(15.435,1.31),(15.435,0.74),(15.205,0.74),(15.205,1.31),(13.195,1.31),(13.195,0.74),(12.965,0.74),(12.965,1.31),(10.955,1.31),(10.955,0.74)],
  [(0,-0.45),(0,0.45),(0.245,0.45),(0.245,1.315),(0.475,1.315),(0.475,0.45),(2.705,0.45),(2.705,1.08),(2.935,1.08),(2.935,0.45),(4.945,0.45),(4.945,1.08),(5.175,1.08),(5.175,0.45),(7.185,0.45),(7.185,1.08),(7.415,1.08),(7.415,0.45),(9.605,0.45),(9.605,1.08),(9.835,1.08),(9.835,0.45),(11.845,0.45),(11.845,1.08),(12.075,1.08),(12.075,0.45),(14.085,0.45),(14.085,1.08),(14.315,1.08),(14.315,0.45),(16.325,0.45),(16.325,1.08),(16.555,1.08),(16.555,0.45),(18.565,0.45),(18.565,1.08),(18.795,1.08),(18.795,0.45),(20.805,0.45),(20.805,1.08),(21.035,1.08),(21.035,0.45),(21.28,0.45),(21.28,-0.45)],
  [(0.465,3.55),(0.465,4.59),(0,4.59),(0,5.49),(21.28,5.49),(21.28,4.59),(20.935,4.59),(20.935,3.55),(20.705,3.55),(20.705,4.59),(18.695,4.59),(18.695,3.55),(18.465,3.55),(18.465,4.59),(16.455,4.59),(16.455,3.55),(16.225,3.55),(16.225,4.59),(14.215,4.59),(14.215,3.55),(13.985,3.55),(13.985,4.59),(11.975,4.59),(11.975,3.55),(11.745,3.55),(11.745,4.59),(9.735,4.59),(9.735,3.55),(9.505,3.55),(9.505,4.59),(7.595,4.59),(7.595,3.875),(7.365,3.875),(7.365,4.59),(5.075,4.59),(5.075,3.55),(4.845,3.55),(4.845,4.59),(2.835,4.59),(2.835,3.55),(2.605,3.55),(2.605,4.59),(0.695,4.59),(0.695,3.55)])
R(gf180mcu_fd_sc_mcu9t5v0_, dualgate, [(-0.28,-0.28,21.56,5.32)])
R(gf180mcu_fd_sc_mcu9t5v0_, v5_xtor, [(0,0,21.28,5.04)])
R(gf180mcu_fd_sc_mcu9t5v0_, lvpwell, [(-0.43,-0.43,21.71,2.265)])
gf180mcu_fd_sc_mcu9t5v0_.add(gdstk.Label('I', (4.76,1.96), layer=34, texttype=10))
gf180mcu_fd_sc_mcu9t5v0_.add(gdstk.Label('VDD', (10.64,5.49), layer=34, texttype=10))
gf180mcu_fd_sc_mcu9t5v0_.add(gdstk.Label('VSS', (10.64,-0.45), layer=34, texttype=10))
gf180mcu_fd_sc_mcu9t5v0_.add(gdstk.Label('Z', (13.72,2.52), layer=34, texttype=10))
gf180mcu_fd_sc_mcu9t5v0_.add(gdstk.Label('& Vendor GLOBALFOUNDRIES', (0,2), layer=63, texttype=63))
gf180mcu_fd_sc_mcu9t5v0_.add(gdstk.Label('& Product GF018hv5v_green_sc9', (0,1.5), layer=63, texttype=63))
gf180mcu_fd_sc_mcu9t5v0_.add(gdstk.Label('& Version 2015q2v2', (0,1), layer=63, texttype=63))
gf180mcu_fd_sc_mcu9t5v0_.add(gdstk.Label('& Metric 1.00', (0,0.5), layer=63, texttype=63))
gf180mcu_fd_sc_mcu9t5v0_.add(gdstk.Label('VNW', (0.345,3.92), layer=21, texttype=10))
gf180mcu_fd_sc_mcu9t5v0_.add(gdstk.Label('VPW', (0.34,-0.085), layer=204, texttype=10))

lib.write_gds('gf180mcu_fd_sc_mcu9t5v0__clkbuf_12.gds')
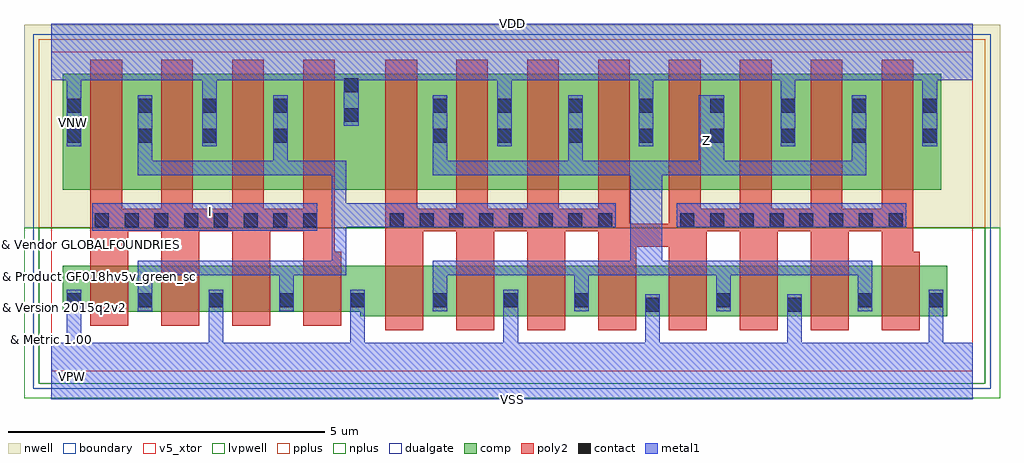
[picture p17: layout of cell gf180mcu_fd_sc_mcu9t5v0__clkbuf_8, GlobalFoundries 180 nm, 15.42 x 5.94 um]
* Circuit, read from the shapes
.subckt gf180mcu_fd_sc_mcu9t5v0__clkbuf_8 I VDD VNW VSS Z
XM1 n1 I VSS VSUBS nfet_05v0 w=0.73u l=0.6u m=4
XM2 Z n1 VSS VSUBS nfet_05v0 w=0.8u l=0.6u m=8
XM3 n1 I VDD VNW pfet_05v0 w=1.83u l=0.5u m=4
XM4 Z n1 VDD VNW pfet_05v0 w=1.83u l=0.5u m=8
.ends

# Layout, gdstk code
import gdstk
lib = gdstk.Library(unit=1e-6, precision=1e-09)
def R(c, l, rs):  # rectangles x0, y0, x1, y1
    for r in rs: c.add(gdstk.rectangle(r[:2], r[2:], *l))
def A(c, l, x, y, w, h, nx, ny, dx, dy):  # array of equal rectangles
    R(c, l, [(x+i*dx, y+j*dy, x+i*dx+w, y+j*dy+h) for i in range(nx) for j in range(ny)])
def P(c, l, *ps):  # polygons
    for p in ps: c.add(gdstk.Polygon(p, *l))
boundary = (0, 0)
nwell = (21, 0)
comp = (22, 0)
poly2 = (30, 0)
pplus = (31, 0)
nplus = (32, 0)
contact = (33, 0)
metal1 = (34, 0)
dualgate = (55, 0)
v5_xtor = (112, 1)
lvpwell = (204, 0)

gf180mcu_fd_sc_mcu9t5v0_ = lib.new_cell('gf180mcu_fd_sc_mcu9t5v0__clkbuf_8')
R(gf180mcu_fd_sc_mcu9t5v0_, boundary, [(0,0,14.56,5.04)])
R(gf180mcu_fd_sc_mcu9t5v0_, nwell, [(-0.43,2.265,14.99,5.47)])
R(gf180mcu_fd_sc_mcu9t5v0_, comp, [(0.18,2.865,14.06,4.695)])
P(gf180mcu_fd_sc_mcu9t5v0_, comp, [(4.88,0.865),(4.88,0.935),(0.18,0.935),(0.18,1.665),(14.16,1.665),(14.16,0.865)])
P(gf180mcu_fd_sc_mcu9t5v0_, poly2, [(0.62,0.715),(0.62,4.915),(1.12,4.915),(1.12,2.565),(1.74,2.565),(1.74,4.915),(2.24,4.915),(2.24,2.565),(2.86,2.565),(2.86,4.915),(3.36,4.915),(3.36,2.565),(3.98,2.565),(3.98,4.915),(4.48,4.915),(4.48,1.885),(4.58,1.885),(4.58,0.715),(3.98,0.715),(3.98,2.205),(3.46,2.205),(3.46,0.715),(2.86,0.715),(2.86,2.205),(2.34,2.205),(2.34,0.715),(1.74,0.715),(1.74,2.205),(1.22,2.205),(1.22,0.715)],
  [(5.28,0.645),(5.28,4.915),(5.78,4.915),(5.78,2.565),(6.4,2.565),(6.4,4.915),(6.9,4.915),(6.9,2.565),(7.52,2.565),(7.52,4.915),(8.02,4.915),(8.02,2.565),(8.64,2.565),(8.64,4.915),(9.14,4.915),(9.14,2.325),(9.76,2.325),(9.76,4.915),(10.26,4.915),(10.26,2.565),(10.88,2.565),(10.88,4.915),(11.38,4.915),(11.38,2.565),(12,2.565),(12,4.915),(12.5,4.915),(12.5,2.565),(13.12,2.565),(13.12,4.915),(13.62,4.915),(13.62,1.885),(13.72,1.885),(13.72,0.645),(13.12,0.645),(13.12,2.205),(12.6,2.205),(12.6,0.645),(12,0.645),(12,2.205),(11.48,2.205),(11.48,0.645),(10.88,0.645),(10.88,2.205),(10.36,2.205),(10.36,0.645),(9.76,0.645),(9.76,1.965),(9.24,1.965),(9.24,0.645),(8.64,0.645),(8.64,2.205),(8.12,2.205),(8.12,0.645),(7.52,0.645),(7.52,2.205),(7,2.205),(7,0.645),(6.4,0.645),(6.4,2.205),(5.88,2.205),(5.88,0.645)])
R(gf180mcu_fd_sc_mcu9t5v0_, pplus, [(-0.2,2.265,14.76,5.24)])
R(gf180mcu_fd_sc_mcu9t5v0_, nplus, [(-0.2,-0.2,14.76,2.265)])
A(gf180mcu_fd_sc_mcu9t5v0_, contact, 0.25, 1.005, 0.22, 0.22, 5, 1, 1.12, 0)
A(gf180mcu_fd_sc_mcu9t5v0_, contact, 6.03, 1.005, 0.22, 0.22, 3, 1, 1.12, 0)
A(gf180mcu_fd_sc_mcu9t5v0_, contact, 0.69, 2.275, 0.22, 0.22, 8, 1, 0.47, 0)
A(gf180mcu_fd_sc_mcu9t5v0_, contact, 5.35, 2.275, 0.22, 0.22, 8, 1, 0.47, 0)
A(gf180mcu_fd_sc_mcu9t5v0_, contact, 9.94, 2.275, 0.22, 0.22, 8, 1, 0.47, 0)
A(gf180mcu_fd_sc_mcu9t5v0_, contact, 7.05, 3.61, 0.22, 0.22, 7, 2, 1.12, 0.47)
R(gf180mcu_fd_sc_mcu9t5v0_, contact, [(9.39,0.935,9.61,1.155), (11.63,0.935,11.85,1.155), (10.51,1.005,10.73,1.225), (12.75,1.005,12.97,1.225), (13.87,1.005,14.09,1.225), (0.25,3.61,0.47,3.83), (1.37,3.61,1.59,3.83), (2.39,3.61,2.61,3.83), (3.51,3.61,3.73,3.83), (6.03,3.61,6.25,3.83), (4.63,3.935,4.85,4.155), (0.25,4.08,0.47,4.3), (1.37,4.08,1.59,4.3), (2.39,4.08,2.61,4.3), (3.51,4.08,3.73,4.3), (6.03,4.08,6.25,4.3), (4.63,4.405,4.85,4.625)])
R(gf180mcu_fd_sc_mcu9t5v0_, metal1, [(0.65,2.215,4.205,2.65), (9.88,2.27,13.51,2.65)])
P(gf180mcu_fd_sc_mcu9t5v0_, metal1, [(1.365,0.945),(1.365,1.745),(4.435,1.745),(4.435,3.09),(1.365,3.09),(1.365,4.36),(1.595,4.36),(1.595,3.32),(3.505,3.32),(3.505,4.36),(3.735,4.36),(3.735,3.32),(4.665,3.32),(4.665,2.65),(8.92,2.65),(8.92,2.27),(4.665,2.27),(4.665,1.515),(3.835,1.515),(3.835,0.945),(3.605,0.945),(3.605,1.515),(1.595,1.515),(1.595,0.945)],
  [(6.025,0.945),(6.025,1.745),(9.15,1.745),(9.15,3.09),(6.025,3.09),(6.025,4.36),(6.255,4.36),(6.255,3.32),(8.165,3.32),(8.165,4.36),(8.395,4.36),(8.395,3.32),(10.23,3.32),(10.23,4.36),(10.635,4.36),(10.635,3.32),(12.645,3.32),(12.645,4.36),(12.875,4.36),(12.875,3.09),(9.65,3.09),(9.65,1.745),(12.975,1.745),(12.975,0.945),(12.745,0.945),(12.745,1.515),(10.735,1.515),(10.735,0.945),(10.505,0.945),(10.505,1.515),(8.495,1.515),(8.495,0.945),(8.265,0.945),(8.265,1.515),(6.255,1.515),(6.255,0.945)],
  [(0,-0.45),(0,0.45),(0.245,0.45),(0.245,1.285),(0.475,1.285),(0.475,0.45),(2.485,0.45),(2.485,1.285),(2.715,1.285),(2.715,0.45),(4.725,0.45),(4.725,1.285),(4.955,1.285),(4.955,0.45),(7.145,0.45),(7.145,1.285),(7.375,1.285),(7.375,0.45),(9.385,0.45),(9.385,1.215),(9.615,1.215),(9.615,0.45),(11.625,0.45),(11.625,1.215),(11.855,1.215),(11.855,0.45),(13.865,0.45),(13.865,1.285),(14.095,1.285),(14.095,0.45),(14.56,0.45),(14.56,-0.45)],
  [(0.245,3.55),(0.245,4.59),(0,4.59),(0,5.49),(14.56,5.49),(14.56,4.59),(13.995,4.59),(13.995,3.55),(13.765,3.55),(13.765,4.59),(11.755,4.59),(11.755,3.55),(11.525,3.55),(11.525,4.59),(9.515,4.59),(9.515,3.55),(9.285,3.55),(9.285,4.59),(7.275,4.59),(7.275,3.55),(7.045,3.55),(7.045,4.59),(4.855,4.59),(4.855,3.875),(4.625,3.875),(4.625,4.59),(2.615,4.59),(2.615,3.55),(2.385,3.55),(2.385,4.59),(0.475,4.59),(0.475,3.55)])
R(gf180mcu_fd_sc_mcu9t5v0_, dualgate, [(-0.28,-0.28,14.84,5.32)])
R(gf180mcu_fd_sc_mcu9t5v0_, v5_xtor, [(0,0,14.56,5.04)])
R(gf180mcu_fd_sc_mcu9t5v0_, lvpwell, [(-0.43,-0.43,14.99,2.265)])
gf180mcu_fd_sc_mcu9t5v0_.add(gdstk.Label('I', (2.52,2.52), layer=34, texttype=10))
gf180mcu_fd_sc_mcu9t5v0_.add(gdstk.Label('VDD', (7.28,5.49), layer=34, texttype=10))
gf180mcu_fd_sc_mcu9t5v0_.add(gdstk.Label('VSS', (7.28,-0.45), layer=34, texttype=10))
gf180mcu_fd_sc_mcu9t5v0_.add(gdstk.Label('Z', (10.36,3.64), layer=34, texttype=10))
gf180mcu_fd_sc_mcu9t5v0_.add(gdstk.Label('& Vendor GLOBALFOUNDRIES', (0,2), layer=63, texttype=63))
gf180mcu_fd_sc_mcu9t5v0_.add(gdstk.Label('& Product GF018hv5v_green_sc9', (0,1.5), layer=63, texttype=63))
gf180mcu_fd_sc_mcu9t5v0_.add(gdstk.Label('& Version 2015q2v2', (0,1), layer=63, texttype=63))
gf180mcu_fd_sc_mcu9t5v0_.add(gdstk.Label('& Metric 1.00', (0,0.5), layer=63, texttype=63))
gf180mcu_fd_sc_mcu9t5v0_.add(gdstk.Label('VNW', (0.345,3.92), layer=21, texttype=10))
gf180mcu_fd_sc_mcu9t5v0_.add(gdstk.Label('VPW', (0.34,-0.085), layer=204, texttype=10))

lib.write_gds('gf180mcu_fd_sc_mcu9t5v0__clkbuf_8.gds')
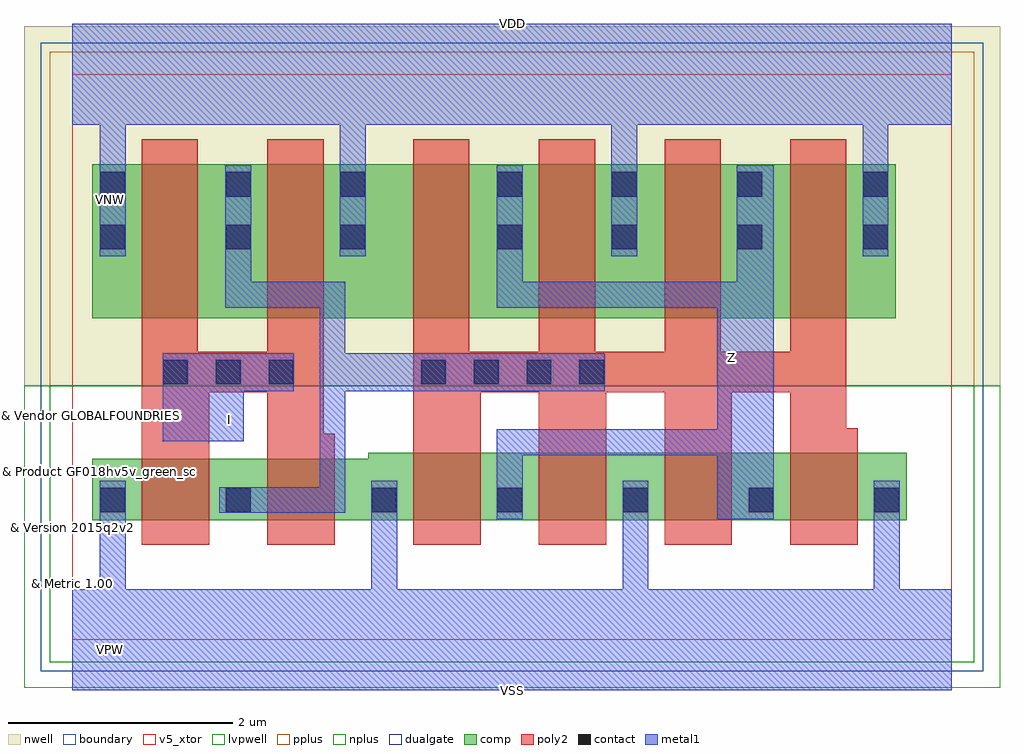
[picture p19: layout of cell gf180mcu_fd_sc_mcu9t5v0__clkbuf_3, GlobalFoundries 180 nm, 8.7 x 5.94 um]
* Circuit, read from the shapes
.subckt gf180mcu_fd_sc_mcu9t5v0__clkbuf_3 I VDD VNW VSS Z
XM1 n1 I VSS VSUBS nfet_05v0 w=0.55u l=0.6u m=2
XM2 Z n1 VSS VSUBS nfet_05v0 w=0.6u l=0.6u m=4
XM3 n1 I VDD VNW pfet_05v0 w=1.375u l=0.5u m=2
XM4 Z n1 VDD VNW pfet_05v0 w=1.375u l=0.5u m=4
.ends

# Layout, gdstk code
import gdstk
lib = gdstk.Library(unit=1e-6, precision=1e-09)
def R(c, l, rs):  # rectangles x0, y0, x1, y1
    for r in rs: c.add(gdstk.rectangle(r[:2], r[2:], *l))
def A(c, l, x, y, w, h, nx, ny, dx, dy):  # array of equal rectangles
    R(c, l, [(x+i*dx, y+j*dy, x+i*dx+w, y+j*dy+h) for i in range(nx) for j in range(ny)])
def P(c, l, *ps):  # polygons
    for p in ps: c.add(gdstk.Polygon(p, *l))
boundary = (0, 0)
nwell = (21, 0)
comp = (22, 0)
poly2 = (30, 0)
pplus = (31, 0)
nplus = (32, 0)
contact = (33, 0)
metal1 = (34, 0)
dualgate = (55, 0)
v5_xtor = (112, 1)
lvpwell = (204, 0)

gf180mcu_fd_sc_mcu9t5v0_ = lib.new_cell('gf180mcu_fd_sc_mcu9t5v0__clkbuf_3')
R(gf180mcu_fd_sc_mcu9t5v0_, boundary, [(0,0,7.84,5.04)])
R(gf180mcu_fd_sc_mcu9t5v0_, nwell, [(-0.43,2.265,8.27,5.47)])
R(gf180mcu_fd_sc_mcu9t5v0_, comp, [(0.18,2.865,7.34,4.24)])
P(gf180mcu_fd_sc_mcu9t5v0_, comp, [(0.18,1.065),(0.18,1.615),(2.64,1.615),(2.64,1.665),(7.44,1.665),(7.44,1.065)])
P(gf180mcu_fd_sc_mcu9t5v0_, poly2, [(0.62,0.845),(0.62,4.46),(1.12,4.46),(1.12,2.565),(1.74,2.565),(1.74,4.46),(2.24,4.46),(2.24,1.835),(2.34,1.835),(2.34,0.845),(1.74,0.845),(1.74,2.205),(1.22,2.205),(1.22,0.845)],
  [(3.04,0.845),(3.04,4.46),(3.54,4.46),(3.54,2.565),(4.16,2.565),(4.16,4.46),(4.66,4.46),(4.66,2.565),(5.28,2.565),(5.28,4.46),(5.78,4.46),(5.78,2.565),(6.4,2.565),(6.4,4.46),(6.9,4.46),(6.9,1.885),(7,1.885),(7,0.845),(6.4,0.845),(6.4,2.205),(5.88,2.205),(5.88,0.845),(5.28,0.845),(5.28,2.205),(4.76,2.205),(4.76,0.845),(4.16,0.845),(4.16,2.205),(3.64,2.205),(3.64,0.845)])
R(gf180mcu_fd_sc_mcu9t5v0_, pplus, [(-0.2,2.265,8.04,5.24)])
R(gf180mcu_fd_sc_mcu9t5v0_, nplus, [(-0.2,-0.2,8.04,2.265)])
A(gf180mcu_fd_sc_mcu9t5v0_, contact, 2.67, 1.135, 0.22, 0.22, 5, 1, 1.12, 0)
A(gf180mcu_fd_sc_mcu9t5v0_, contact, 0.81, 2.275, 0.22, 0.22, 3, 1, 0.47, 0)
A(gf180mcu_fd_sc_mcu9t5v0_, contact, 3.11, 2.275, 0.22, 0.22, 4, 1, 0.47, 0)
A(gf180mcu_fd_sc_mcu9t5v0_, contact, 4.81, 3.48, 0.22, 0.22, 3, 2, 1.12, 0.47)
R(gf180mcu_fd_sc_mcu9t5v0_, contact, [(0.25,1.135,0.47,1.355), (1.37,1.135,1.59,1.355), (0.25,3.48,0.47,3.7), (1.37,3.48,1.59,3.7), (2.39,3.48,2.61,3.7), (3.79,3.48,4.01,3.7), (0.25,3.95,0.47,4.17), (1.37,3.95,1.59,4.17), (2.39,3.95,2.61,4.17), (3.79,3.95,4.01,4.17)])
P(gf180mcu_fd_sc_mcu9t5v0_, metal1, [(0.805,1.77),(0.805,2.555),(1.975,2.555),(1.975,2.215),(1.53,2.215),(1.53,1.77)],
  [(1.31,1.13),(1.31,1.36),(2.205,1.36),(2.205,2.96),(1.365,2.96),(1.365,4.23),(1.595,4.23),(1.595,3.19),(2.435,3.19),(2.435,2.555),(4.745,2.555),(4.745,2.215),(2.435,2.215),(2.435,1.13)],
  [(3.785,1.075),(3.785,1.875),(5.75,1.875),(5.75,2.96),(3.785,2.96),(3.785,4.23),(4.015,4.23),(4.015,3.19),(5.925,3.19),(5.925,4.23),(6.255,4.23),(6.255,1.075),(5.75,1.075),(5.75,1.645),(4.015,1.645),(4.015,1.075)],
  [(0,-0.45),(0,0.45),(0.245,0.45),(0.245,1.415),(0.475,1.415),(0.475,0.45),(2.665,0.45),(2.665,1.415),(2.895,1.415),(2.895,0.45),(4.905,0.45),(4.905,1.415),(5.135,1.415),(5.135,0.45),(7.145,0.45),(7.145,1.415),(7.375,1.415),(7.375,0.45),(7.84,0.45),(7.84,-0.45)],
  [(0.245,3.42),(0.245,4.59),(0,4.59),(0,5.49),(7.84,5.49),(7.84,4.59),(7.275,4.59),(7.275,3.42),(7.045,3.42),(7.045,4.59),(5.035,4.59),(5.035,3.42),(4.805,3.42),(4.805,4.59),(2.615,4.59),(2.615,3.42),(2.385,3.42),(2.385,4.59),(0.475,4.59),(0.475,3.42)])
R(gf180mcu_fd_sc_mcu9t5v0_, dualgate, [(-0.28,-0.28,8.12,5.32)])
R(gf180mcu_fd_sc_mcu9t5v0_, v5_xtor, [(0,0,7.84,5.04)])
R(gf180mcu_fd_sc_mcu9t5v0_, lvpwell, [(-0.43,-0.43,8.27,2.265)])
gf180mcu_fd_sc_mcu9t5v0_.add(gdstk.Label('I', (1.4,1.96), layer=34, texttype=10))
gf180mcu_fd_sc_mcu9t5v0_.add(gdstk.Label('VDD', (3.92,5.49), layer=34, texttype=10))
gf180mcu_fd_sc_mcu9t5v0_.add(gdstk.Label('VSS', (3.92,-0.45), layer=34, texttype=10))
gf180mcu_fd_sc_mcu9t5v0_.add(gdstk.Label('Z', (5.88,2.52), layer=34, texttype=10))
gf180mcu_fd_sc_mcu9t5v0_.add(gdstk.Label('& Vendor GLOBALFOUNDRIES', (0,2), layer=63, texttype=63))
gf180mcu_fd_sc_mcu9t5v0_.add(gdstk.Label('& Product GF018hv5v_green_sc9', (0,1.5), layer=63, texttype=63))
gf180mcu_fd_sc_mcu9t5v0_.add(gdstk.Label('& Version 2015q2v2', (0,1), layer=63, texttype=63))
gf180mcu_fd_sc_mcu9t5v0_.add(gdstk.Label('& Metric 1.00', (0,0.5), layer=63, texttype=63))
gf180mcu_fd_sc_mcu9t5v0_.add(gdstk.Label('VNW', (0.345,3.92), layer=21, texttype=10))
gf180mcu_fd_sc_mcu9t5v0_.add(gdstk.Label('VPW', (0.34,-0.085), layer=204, texttype=10))

lib.write_gds('gf180mcu_fd_sc_mcu9t5v0__clkbuf_3.gds')
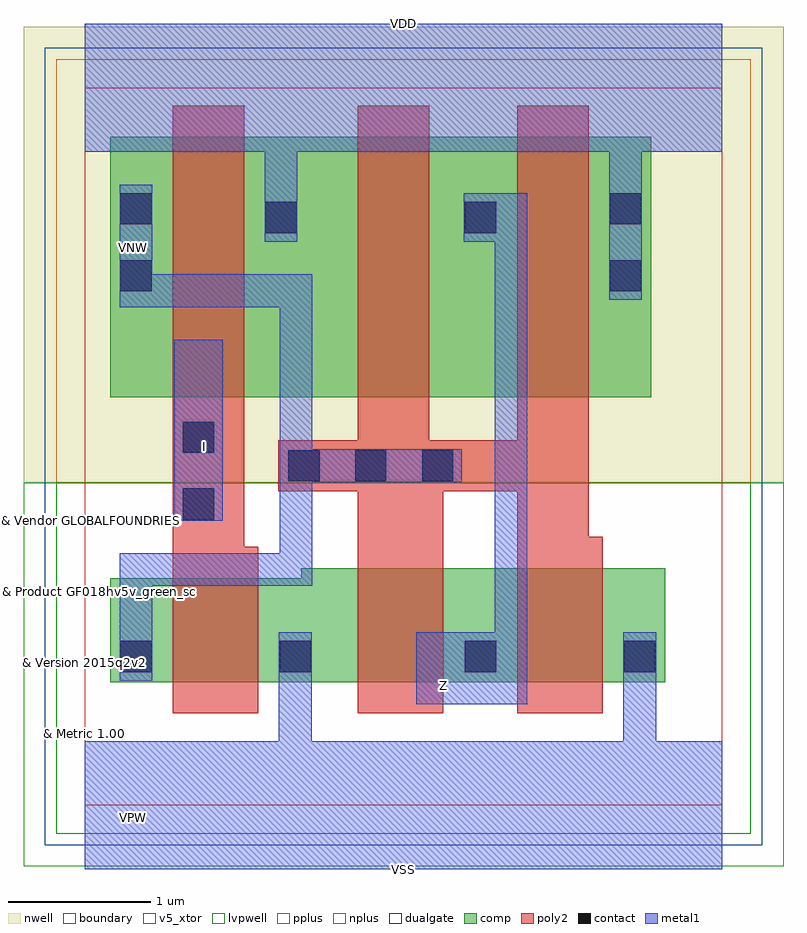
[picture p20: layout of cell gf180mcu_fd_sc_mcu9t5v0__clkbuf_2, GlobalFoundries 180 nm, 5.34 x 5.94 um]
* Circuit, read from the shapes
.subckt gf180mcu_fd_sc_mcu9t5v0__clkbuf_2 I VDD VNW VSS Z
XM1 VSS I n1 VSUBS nfet_05v0 w=0.73u l=0.6u
XM2 Z n1 VSS VSUBS nfet_05v0 w=0.8u l=0.6u m=2
XM3 VDD I n1 VNW pfet_05v0 w=1.83u l=0.5u
XM4 Z n1 VDD VNW pfet_05v0 w=1.83u l=0.5u m=2
.ends

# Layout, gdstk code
import gdstk
lib = gdstk.Library(unit=1e-6, precision=1e-09)
def R(c, l, rs):  # rectangles x0, y0, x1, y1
    for r in rs: c.add(gdstk.rectangle(r[:2], r[2:], *l))
def A(c, l, x, y, w, h, nx, ny, dx, dy):  # array of equal rectangles
    R(c, l, [(x+i*dx, y+j*dy, x+i*dx+w, y+j*dy+h) for i in range(nx) for j in range(ny)])
def P(c, l, *ps):  # polygons
    for p in ps: c.add(gdstk.Polygon(p, *l))
boundary = (0, 0)
nwell = (21, 0)
comp = (22, 0)
poly2 = (30, 0)
pplus = (31, 0)
nplus = (32, 0)
contact = (33, 0)
metal1 = (34, 0)
dualgate = (55, 0)
v5_xtor = (112, 1)
lvpwell = (204, 0)

gf180mcu_fd_sc_mcu9t5v0_ = lib.new_cell('gf180mcu_fd_sc_mcu9t5v0__clkbuf_2')
R(gf180mcu_fd_sc_mcu9t5v0_, boundary, [(0,0,4.48,5.04)])
R(gf180mcu_fd_sc_mcu9t5v0_, nwell, [(-0.43,2.265,4.91,5.47)])
R(gf180mcu_fd_sc_mcu9t5v0_, comp, [(0.18,2.865,3.98,4.695)])
P(gf180mcu_fd_sc_mcu9t5v0_, comp, [(0.18,0.865),(0.18,1.595),(1.52,1.595),(1.52,1.665),(4.08,1.665),(4.08,0.865)])
P(gf180mcu_fd_sc_mcu9t5v0_, poly2, [(0.62,0.645),(0.62,4.915),(1.12,4.915),(1.12,1.815),(1.22,1.815),(1.22,0.645)],
  [(1.92,0.645),(1.92,2.205),(1.36,2.205),(1.36,2.565),(1.92,2.565),(1.92,4.915),(2.42,4.915),(2.42,2.565),(3.04,2.565),(3.04,4.915),(3.54,4.915),(3.54,1.885),(3.64,1.885),(3.64,0.645),(3.04,0.645),(3.04,2.205),(2.52,2.205),(2.52,0.645)])
R(gf180mcu_fd_sc_mcu9t5v0_, pplus, [(-0.2,2.265,4.68,5.24)])
R(gf180mcu_fd_sc_mcu9t5v0_, nplus, [(-0.2,-0.2,4.68,2.265)])
A(gf180mcu_fd_sc_mcu9t5v0_, contact, 1.43, 2.275, 0.22, 0.22, 3, 1, 0.47, 0)
R(gf180mcu_fd_sc_mcu9t5v0_, contact, [(0.25,0.935,0.47,1.155), (1.37,0.935,1.59,1.155), (2.67,0.935,2.89,1.155), (3.79,0.935,4.01,1.155), (0.69,2.005,0.91,2.225), (0.69,2.475,0.91,2.695), (0.25,3.61,0.47,3.83), (3.69,3.61,3.91,3.83), (1.27,4.02,1.49,4.24), (2.67,4.02,2.89,4.24), (0.25,4.08,0.47,4.3), (3.69,4.08,3.91,4.3)])
R(gf180mcu_fd_sc_mcu9t5v0_, metal1, [(0.63,2,0.97,3.27)])
P(gf180mcu_fd_sc_mcu9t5v0_, metal1, [(0.245,0.875),(0.245,1.77),(1.37,1.77),(1.37,3.5),(0.245,3.5),(0.245,4.36),(0.475,4.36),(0.475,3.73),(1.6,3.73),(1.6,2.5),(2.65,2.5),(2.65,2.27),(1.6,2.27),(1.6,1.54),(0.475,1.54),(0.475,0.875)],
  [(2.33,0.71),(2.33,1.215),(2.88,1.215),(2.88,3.96),(2.665,3.96),(2.665,4.3),(3.11,4.3),(3.11,0.71)],
  [(0,-0.45),(0,0.45),(1.365,0.45),(1.365,1.215),(1.595,1.215),(1.595,0.45),(3.785,0.45),(3.785,1.215),(4.015,1.215),(4.015,0.45),(4.48,0.45),(4.48,-0.45)],
  [(3.685,3.55),(3.685,4.59),(1.495,4.59),(1.495,3.96),(1.265,3.96),(1.265,4.59),(0,4.59),(0,5.49),(4.48,5.49),(4.48,4.59),(3.915,4.59),(3.915,3.55)])
R(gf180mcu_fd_sc_mcu9t5v0_, dualgate, [(-0.28,-0.28,4.76,5.32)])
R(gf180mcu_fd_sc_mcu9t5v0_, v5_xtor, [(0,0,4.48,5.04)])
R(gf180mcu_fd_sc_mcu9t5v0_, lvpwell, [(-0.43,-0.43,4.91,2.265)])
gf180mcu_fd_sc_mcu9t5v0_.add(gdstk.Label('I', (0.84,2.52), layer=34, texttype=10))
gf180mcu_fd_sc_mcu9t5v0_.add(gdstk.Label('VDD', (2.24,5.49), layer=34, texttype=10))
gf180mcu_fd_sc_mcu9t5v0_.add(gdstk.Label('VSS', (2.24,-0.45), layer=34, texttype=10))
gf180mcu_fd_sc_mcu9t5v0_.add(gdstk.Label('Z', (2.52,0.84), layer=34, texttype=10))
gf180mcu_fd_sc_mcu9t5v0_.add(gdstk.Label('& Vendor GLOBALFOUNDRIES', (0,2), layer=63, texttype=63))
gf180mcu_fd_sc_mcu9t5v0_.add(gdstk.Label('& Product GF018hv5v_green_sc9', (0,1.5), layer=63, texttype=63))
gf180mcu_fd_sc_mcu9t5v0_.add(gdstk.Label('& Version 2015q2v2', (0,1), layer=63, texttype=63))
gf180mcu_fd_sc_mcu9t5v0_.add(gdstk.Label('& Metric 1.00', (0,0.5), layer=63, texttype=63))
gf180mcu_fd_sc_mcu9t5v0_.add(gdstk.Label('VNW', (0.345,3.92), layer=21, texttype=10))
gf180mcu_fd_sc_mcu9t5v0_.add(gdstk.Label('VPW', (0.34,-0.085), layer=204, texttype=10))

lib.write_gds('gf180mcu_fd_sc_mcu9t5v0__clkbuf_2.gds')
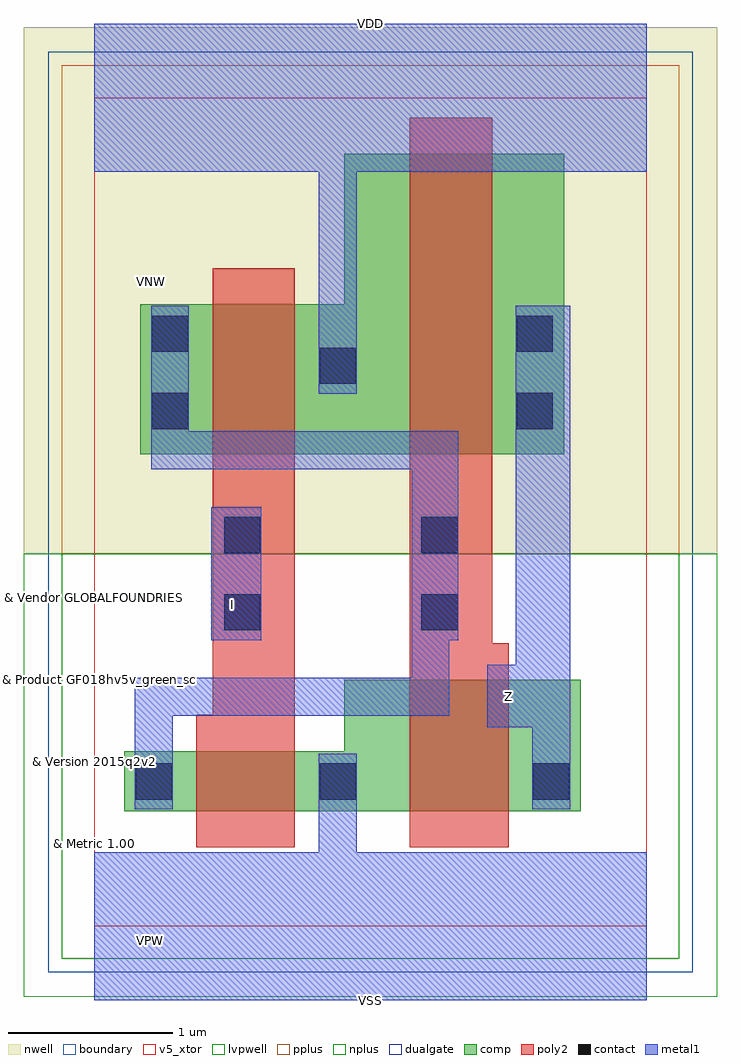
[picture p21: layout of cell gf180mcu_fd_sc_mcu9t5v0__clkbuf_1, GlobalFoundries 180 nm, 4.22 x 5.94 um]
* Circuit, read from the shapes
.subckt gf180mcu_fd_sc_mcu9t5v0__clkbuf_1 I VDD VNW VSS Z
XM1 VSS I n1 VSUBS nfet_05v0 w=0.365u l=0.6u
XM2 Z n1 VSS VSUBS nfet_05v0 w=0.8u l=0.6u
XM3 VDD I n1 VNW pfet_05v0 w=0.915u l=0.5u
XM4 Z n1 VDD VNW pfet_05v0 w=1.83u l=0.5u
.ends

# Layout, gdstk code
import gdstk
lib = gdstk.Library(unit=1e-6, precision=1e-09)
def R(c, l, rs):  # rectangles x0, y0, x1, y1
    for r in rs: c.add(gdstk.rectangle(r[:2], r[2:], *l))
def P(c, l, *ps):  # polygons
    for p in ps: c.add(gdstk.Polygon(p, *l))
boundary = (0, 0)
nwell = (21, 0)
comp = (22, 0)
poly2 = (30, 0)
pplus = (31, 0)
nplus = (32, 0)
contact = (33, 0)
metal1 = (34, 0)
dualgate = (55, 0)
v5_xtor = (112, 1)
lvpwell = (204, 0)

gf180mcu_fd_sc_mcu9t5v0_ = lib.new_cell('gf180mcu_fd_sc_mcu9t5v0__clkbuf_1')
R(gf180mcu_fd_sc_mcu9t5v0_, boundary, [(0,0,3.36,5.04)])
R(gf180mcu_fd_sc_mcu9t5v0_, nwell, [(-0.43,2.265,3.79,5.47)])
P(gf180mcu_fd_sc_mcu9t5v0_, comp, [(0.28,2.87),(0.28,3.785),(1.52,3.785),(1.52,4.7),(2.86,4.7),(2.86,2.87)],
  [(0.18,0.7),(0.18,1.065),(1.52,1.065),(1.52,1.5),(2.96,1.5),(2.96,0.7)])
P(gf180mcu_fd_sc_mcu9t5v0_, poly2, [(0.62,0.48),(0.62,1.285),(0.72,1.285),(0.72,4.005),(1.22,4.005),(1.22,0.48)],
  [(1.92,0.48),(1.92,4.92),(2.42,4.92),(2.42,1.72),(2.52,1.72),(2.52,0.48)])
R(gf180mcu_fd_sc_mcu9t5v0_, pplus, [(-0.2,2.265,3.56,5.24)])
R(gf180mcu_fd_sc_mcu9t5v0_, nplus, [(-0.2,-0.2,3.56,2.265)])
R(gf180mcu_fd_sc_mcu9t5v0_, contact, [(0.25,0.77,0.47,0.99), (1.37,0.77,1.59,0.99), (2.67,0.77,2.89,0.99), (0.79,1.8,1.01,2.02), (1.99,1.8,2.21,2.02), (0.79,2.27,1.01,2.49), (1.99,2.27,2.21,2.49), (0.35,3.025,0.57,3.245), (2.57,3.025,2.79,3.245), (1.37,3.3,1.59,3.52), (0.35,3.495,0.57,3.715), (2.57,3.495,2.79,3.715)])
R(gf180mcu_fd_sc_mcu9t5v0_, metal1, [(0.71,1.74,1.015,2.55)])
P(gf180mcu_fd_sc_mcu9t5v0_, metal1, [(0.245,0.71),(0.245,1.51),(1.93,1.51),(1.93,2.78),(0.345,2.78),(0.345,3.775),(0.575,3.775),(0.575,3.01),(2.215,3.01),(2.215,1.74),(2.16,1.74),(2.16,1.28),(0.475,1.28),(0.475,0.71)],
  [(2.665,0.71),(2.665,1.21),(2.39,1.21),(2.39,1.59),(2.565,1.59),(2.565,3.775),(2.895,3.775),(2.895,0.71)],
  [(0,-0.45),(0,0.45),(1.365,0.45),(1.365,1.05),(1.595,1.05),(1.595,0.45),(3.36,0.45),(3.36,-0.45)],
  [(1.365,3.24),(1.365,4.59),(0,4.59),(0,5.49),(3.36,5.49),(3.36,4.59),(1.595,4.59),(1.595,3.24)])
R(gf180mcu_fd_sc_mcu9t5v0_, dualgate, [(-0.28,-0.28,3.64,5.32)])
R(gf180mcu_fd_sc_mcu9t5v0_, v5_xtor, [(0,0,3.36,5.04)])
R(gf180mcu_fd_sc_mcu9t5v0_, lvpwell, [(-0.43,-0.43,3.79,2.265)])
gf180mcu_fd_sc_mcu9t5v0_.add(gdstk.Label('I', (0.84,1.96), layer=34, texttype=10))
gf180mcu_fd_sc_mcu9t5v0_.add(gdstk.Label('VDD', (1.68,5.49), layer=34, texttype=10))
gf180mcu_fd_sc_mcu9t5v0_.add(gdstk.Label('VSS', (1.68,-0.45), layer=34, texttype=10))
gf180mcu_fd_sc_mcu9t5v0_.add(gdstk.Label('Z', (2.52,1.4), layer=34, texttype=10))
gf180mcu_fd_sc_mcu9t5v0_.add(gdstk.Label('& Vendor GLOBALFOUNDRIES', (0,2), layer=63, texttype=63))
gf180mcu_fd_sc_mcu9t5v0_.add(gdstk.Label('& Product GF018hv5v_green_sc9', (0,1.5), layer=63, texttype=63))
gf180mcu_fd_sc_mcu9t5v0_.add(gdstk.Label('& Version 2015q2v2', (0,1), layer=63, texttype=63))
gf180mcu_fd_sc_mcu9t5v0_.add(gdstk.Label('& Metric 1.00', (0,0.5), layer=63, texttype=63))
gf180mcu_fd_sc_mcu9t5v0_.add(gdstk.Label('VNW', (0.345,3.92), layer=21, texttype=10))
gf180mcu_fd_sc_mcu9t5v0_.add(gdstk.Label('VPW', (0.34,-0.085), layer=204, texttype=10))

lib.write_gds('gf180mcu_fd_sc_mcu9t5v0__clkbuf_1.gds')
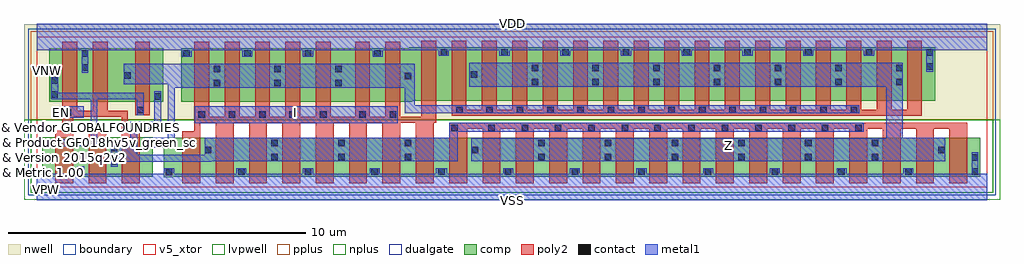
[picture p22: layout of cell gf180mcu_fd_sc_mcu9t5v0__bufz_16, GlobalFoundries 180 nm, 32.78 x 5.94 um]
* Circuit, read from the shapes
.subckt gf180mcu_fd_sc_mcu9t5v0__bufz_16 EN I VDD VNW VSS Z
XM1 VSS EN n1 VSUBS nfet_05v0 w=1.32u l=0.6u
XM2 n2 n1 VSS VSUBS nfet_05v0 w=1.32u l=0.6u
XM3 n3 EN n2 VSUBS nfet_05v0 w=1.32u l=0.6u
XM4 n2 I VSS VSUBS nfet_05v0 w=1.32u l=0.6u m=8
XM5 Z n2 VSS VSUBS nfet_05v0 w=1.32u l=0.6u m=16
XM6 VDD EN n1 VNW pfet_05v0 w=1.8u l=0.5u
XM7 n3 EN VDD VNW pfet_05v0 w=1.8u l=0.5u
XM8 n2 n1 n3 VNW pfet_05v0 w=1.8u l=0.5u
XM9 n3 I VDD VNW pfet_05v0 w=1.8u l=0.5u m=8
XM10 Z n3 VDD VNW pfet_05v0 w=1.8u l=0.5u m=16
.ends

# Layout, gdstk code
import gdstk
lib = gdstk.Library(unit=1e-6, precision=1e-09)
def R(c, l, rs):  # rectangles x0, y0, x1, y1
    for r in rs: c.add(gdstk.rectangle(r[:2], r[2:], *l))
def A(c, l, x, y, w, h, nx, ny, dx, dy):  # array of equal rectangles
    R(c, l, [(x+i*dx, y+j*dy, x+i*dx+w, y+j*dy+h) for i in range(nx) for j in range(ny)])
def P(c, l, *ps):  # polygons
    for p in ps: c.add(gdstk.Polygon(p, *l))
boundary = (0, 0)
nwell = (21, 0)
comp = (22, 0)
poly2 = (30, 0)
pplus = (31, 0)
nplus = (32, 0)
contact = (33, 0)
metal1 = (34, 0)
dualgate = (55, 0)
v5_xtor = (112, 1)
lvpwell = (204, 0)

gf180mcu_fd_sc_mcu9t5v0_ = lib.new_cell('gf180mcu_fd_sc_mcu9t5v0__bufz_16')
R(gf180mcu_fd_sc_mcu9t5v0_, boundary, [(0,0,31.92,5.04)])
R(gf180mcu_fd_sc_mcu9t5v0_, nwell, [(-0.43,2.265,32.35,5.47)])
R(gf180mcu_fd_sc_mcu9t5v0_, comp, [(0.18,0.345,3.9,1.665), (0.42,2.865,4.24,4.665)])
P(gf180mcu_fd_sc_mcu9t5v0_, comp, [(4.85,2.865),(4.85,4.665),(12.51,4.665),(12.51,4.7),(30.17,4.7),(30.17,2.9),(12.61,2.9),(12.61,2.865)],
  [(4.26,0.33),(4.26,1.66),(31.69,1.66),(31.69,0.34),(4.59,0.34),(4.59,0.33)])
R(gf180mcu_fd_sc_mcu9t5v0_, poly2, [(1.74,0.125,2.34,2.125), (3.3,2.405,3.8,4.885)])
P(gf180mcu_fd_sc_mcu9t5v0_, poly2, [(0.62,0.125),(0.62,1.885),(0.86,1.885),(0.86,4.885),(1.36,4.885),(1.36,2.565),(1.88,2.565),(1.88,4.885),(2.38,4.885),(2.38,2.565),(3.06,2.565),(3.06,1.885),(3.46,1.885),(3.46,0.125),(2.86,0.125),(2.86,2.365),(1.22,2.365),(1.22,0.125)],
  [(4.89,0.12),(4.89,1.88),(5.29,1.88),(5.29,4.885),(5.79,4.885),(5.79,2.365),(6.31,2.365),(6.31,4.885),(6.81,4.885),(6.81,2.365),(7.33,2.365),(7.33,4.885),(7.83,4.885),(7.83,2.365),(8.35,2.365),(8.35,4.885),(8.85,4.885),(8.85,2.365),(9.37,2.365),(9.37,4.885),(9.87,4.885),(9.87,2.365),(10.69,2.365),(10.69,4.885),(11.19,4.885),(11.19,2.365),(11.71,2.365),(11.71,4.885),(12.21,4.885),(12.21,2.365),(12.91,2.365),(12.91,4.92),(13.41,4.92),(13.41,2.165),(13.33,2.165),(13.33,0.12),(12.73,0.12),(12.73,2.165),(12.21,2.165),(12.21,0.12),(11.61,0.12),(11.61,2.165),(11.09,2.165),(11.09,0.12),(10.49,0.12),(10.49,2.165),(9.97,2.165),(9.97,0.12),(9.37,0.12),(9.37,2.165),(8.85,2.165),(8.85,0.12),(8.25,0.12),(8.25,2.165),(7.73,2.165),(7.73,0.12),(7.13,0.12),(7.13,2.165),(6.61,2.165),(6.61,0.12),(6.01,0.12),(6.01,2.165),(5.49,2.165),(5.49,0.12)],
  [(13.93,2.4),(13.93,4.92),(14.43,4.92),(14.43,2.6),(14.95,2.6),(14.95,4.92),(15.45,4.92),(15.45,2.6),(15.97,2.6),(15.97,4.92),(16.47,4.92),(16.47,2.6),(16.99,2.6),(16.99,4.92),(17.49,4.92),(17.49,2.6),(18.01,2.6),(18.01,4.92),(18.51,4.92),(18.51,2.6),(19.03,2.6),(19.03,4.92),(19.53,4.92),(19.53,2.6),(20.05,2.6),(20.05,4.92),(20.55,4.92),(20.55,2.6),(21.07,2.6),(21.07,4.92),(21.57,4.92),(21.57,2.6),(22.09,2.6),(22.09,4.92),(22.59,4.92),(22.59,2.6),(23.11,2.6),(23.11,4.92),(23.61,4.92),(23.61,2.6),(24.13,2.6),(24.13,4.92),(24.63,4.92),(24.63,2.6),(25.15,2.6),(25.15,4.92),(25.65,4.92),(25.65,2.6),(26.17,2.6),(26.17,4.92),(26.67,4.92),(26.67,2.6),(27.19,2.6),(27.19,4.92),(27.69,4.92),(27.69,2.6),(28.21,2.6),(28.21,4.92),(28.71,4.92),(28.71,2.6),(29.23,2.6),(29.23,4.92),(29.73,4.92),(29.73,2.4)],
  [(13.85,0.12),(13.85,2.16),(31.25,2.16),(31.25,0.12),(30.65,0.12),(30.65,1.96),(30.13,1.96),(30.13,0.12),(29.53,0.12),(29.53,1.96),(29.01,1.96),(29.01,0.12),(28.41,0.12),(28.41,1.96),(27.89,1.96),(27.89,0.12),(27.29,0.12),(27.29,1.96),(26.77,1.96),(26.77,0.12),(26.17,0.12),(26.17,1.96),(25.65,1.96),(25.65,0.12),(25.05,0.12),(25.05,1.96),(24.53,1.96),(24.53,0.12),(23.93,0.12),(23.93,1.96),(23.41,1.96),(23.41,0.12),(22.81,0.12),(22.81,1.96),(22.29,1.96),(22.29,0.12),(21.69,0.12),(21.69,1.96),(21.17,1.96),(21.17,0.12),(20.57,0.12),(20.57,1.96),(20.05,1.96),(20.05,0.12),(19.45,0.12),(19.45,1.96),(18.93,1.96),(18.93,0.12),(18.33,0.12),(18.33,1.96),(17.81,1.96),(17.81,0.12),(17.21,0.12),(17.21,1.96),(16.69,1.96),(16.69,0.12),(16.09,0.12),(16.09,1.96),(15.57,1.96),(15.57,0.12),(14.97,0.12),(14.97,1.96),(14.45,1.96),(14.45,0.12)])
R(gf180mcu_fd_sc_mcu9t5v0_, pplus, [(-0.2,2.265,32.12,5.24)])
R(gf180mcu_fd_sc_mcu9t5v0_, nplus, [(-0.2,-0.2,32.12,2.265)])
A(gf180mcu_fd_sc_mcu9t5v0_, contact, 6.76, 0.41, 0.22, 0.22, 12, 1, 2.24, 0)
A(gf180mcu_fd_sc_mcu9t5v0_, contact, 7.88, 0.9, 0.22, 0.22, 3, 2, 2.24, 0.47)
A(gf180mcu_fd_sc_mcu9t5v0_, contact, 16.84, 0.9, 0.22, 0.22, 6, 2, 2.24, 0.47)
A(gf180mcu_fd_sc_mcu9t5v0_, contact, 15.165, 1.87, 0.22, 0.22, 3, 1, 1.115, 0)
A(gf180mcu_fd_sc_mcu9t5v0_, contact, 21.875, 1.87, 0.22, 0.22, 3, 1, 1.125, 0)
A(gf180mcu_fd_sc_mcu9t5v0_, contact, 15.1, 2.475, 0.22, 0.22, 3, 1, 1.02, 0)
A(gf180mcu_fd_sc_mcu9t5v0_, contact, 5.94, 3.39, 0.22, 0.22, 3, 2, 2.04, 0.47)
A(gf180mcu_fd_sc_mcu9t5v0_, contact, 16.62, 3.425, 0.22, 0.22, 7, 2, 2.04, 0.47)
A(gf180mcu_fd_sc_mcu9t5v0_, contact, 4.92, 4.375, 0.22, 0.22, 3, 1, 2.04, 0)
A(gf180mcu_fd_sc_mcu9t5v0_, contact, 13.56, 4.41, 0.22, 0.22, 9, 1, 2.04, 0)
R(gf180mcu_fd_sc_mcu9t5v0_, contact, [(4.33,0.4,4.55,0.62), (1.37,0.415,1.59,0.635), (2.49,0.74,2.71,0.96), (31.4,0.88,31.62,1.1), (5.64,1.135,5.86,1.355), (14.6,1.135,14.82,1.355), (30.28,1.135,30.5,1.355), (2.49,1.21,2.71,1.43), (0.25,1.375,0.47,1.595), (3.61,1.375,3.83,1.595), (1.81,1.835,2.03,2.055), (13.92,1.87,14.14,2.09), (18.52,1.87,18.74,2.09), (19.645,1.87,19.865,2.09), (20.74,1.87,20.96,2.09), (25.245,1.87,25.465,2.09), (26.355,1.87,26.575,2.09), (27.495,1.87,27.715,2.09), (5.43,2.32,5.65,2.54), (6.44,2.32,6.66,2.54), (7.465,2.32,7.685,2.54), (8.48,2.32,8.7,2.54), (9.51,2.32,9.73,2.54), (10.83,2.32,11.05,2.54), (11.85,2.32,12.07,2.54), (0.93,2.39,1.15,2.61), (3.37,2.475,3.59,2.695), (14.085,2.475,14.305,2.695), (18.15,2.475,18.37,2.695), (19.17,2.475,19.39,2.695), (20.195,2.475,20.415,2.695), (21.21,2.475,21.43,2.695), (22.24,2.475,22.46,2.695), (23.26,2.475,23.48,2.695), (24.275,2.475,24.495,2.695), (25.295,2.475,25.515,2.695), (26.305,2.475,26.525,2.695), (27.34,2.475,27.56,2.695), (3.95,2.935,4.17,3.155), (0.49,3,0.71,3.22), (0.49,3.47,0.71,3.69), (12.36,3.625,12.58,3.845), (2.93,3.63,3.15,3.85), (14.58,3.665,14.8,3.885), (1.51,3.905,1.73,4.125), (29.88,3.94,30.1,4.16), (1.51,4.375,1.73,4.595), (11.34,4.375,11.56,4.595)])
R(gf180mcu_fd_sc_mcu9t5v0_, metal1, [(5.3,2.15,12.125,2.71), (0.545,2.33,1.575,2.71)])
P(gf180mcu_fd_sc_mcu9t5v0_, metal1, [(0.19,1.37),(0.19,1.6),(1.805,1.6),(1.805,2.94),(0.485,2.94),(0.485,3.75),(0.715,3.75),(0.715,3.17),(3.595,3.17),(3.595,2.415),(3.365,2.415),(3.365,2.94),(2.035,2.94),(2.035,1.37)],
  [(3.605,1.315),(3.605,1.655),(4.405,1.655),(4.405,3.445),(2.925,3.445),(2.925,4.14),(12.7,4.14),(12.7,2.755),(27.62,2.755),(27.62,2.47),(12.355,2.47),(12.355,3.33),(4.635,3.33),(4.635,1.315)],
  [(2.485,0.68),(2.485,1.49),(3.145,1.49),(3.145,2.185),(3.945,2.185),(3.945,3.215),(4.175,3.215),(4.175,1.955),(3.375,1.955),(3.375,1.085),(5.635,1.085),(5.635,1.65),(13.855,1.65),(13.855,2.16),(27.775,2.16),(27.775,1.865),(14.145,1.865),(14.145,0.865),(5.865,0.865),(5.865,0.855),(2.715,0.855),(2.715,0.68)],
  [(14.595,0.865),(14.595,1.635),(28.53,1.635),(28.53,3.365),(14.52,3.365),(14.52,4.175),(29.09,4.175),(29.09,1.65),(30.505,1.65),(30.505,0.865)],
  [(0,-0.45),(0,0.45),(1.365,0.45),(1.365,0.695),(1.595,0.695),(1.595,0.45),(4.27,0.45),(4.27,0.625),(4.61,0.625),(4.61,0.45),(6.7,0.45),(6.7,0.635),(7.04,0.635),(7.04,0.45),(8.94,0.45),(8.94,0.635),(9.28,0.635),(9.28,0.45),(11.18,0.45),(11.18,0.635),(11.52,0.635),(11.52,0.45),(13.405,0.45),(13.405,0.635),(13.78,0.635),(13.78,0.45),(15.66,0.45),(15.66,0.635),(16,0.635),(16,0.45),(17.9,0.45),(17.9,0.635),(18.24,0.635),(18.24,0.45),(20.14,0.45),(20.14,0.635),(20.48,0.635),(20.48,0.45),(22.38,0.45),(22.38,0.635),(22.72,0.635),(22.72,0.45),(24.62,0.45),(24.62,0.635),(24.96,0.635),(24.96,0.45),(26.86,0.45),(26.86,0.635),(27.2,0.635),(27.2,0.45),(29.1,0.45),(29.1,0.635),(29.44,0.635),(29.44,0.45),(31.395,0.45),(31.395,1.16),(31.625,1.16),(31.625,0.45),(31.92,0.45),(31.92,-0.45)],
  [(1.505,3.845),(1.505,4.59),(0,4.59),(0,5.49),(31.92,5.49),(31.92,4.59),(30.105,4.59),(30.105,3.88),(29.875,3.88),(29.875,4.59),(28.12,4.59),(28.12,4.405),(27.78,4.405),(27.78,4.59),(26.08,4.59),(26.08,4.405),(25.74,4.405),(25.74,4.59),(24.04,4.59),(24.04,4.405),(23.7,4.405),(23.7,4.59),(22,4.59),(22,4.405),(21.66,4.405),(21.66,4.59),(19.96,4.59),(19.96,4.405),(19.62,4.405),(19.62,4.59),(17.92,4.59),(17.92,4.405),(17.58,4.405),(17.58,4.59),(15.88,4.59),(15.88,4.405),(15.54,4.405),(15.54,4.59),(13.84,4.59),(13.84,4.405),(13.5,4.405),(13.5,4.59),(11.62,4.59),(11.62,4.37),(11.28,4.37),(11.28,4.59),(9.28,4.59),(9.28,4.37),(8.94,4.37),(8.94,4.59),(7.24,4.59),(7.24,4.37),(6.9,4.37),(6.9,4.59),(5.2,4.59),(5.2,4.37),(4.86,4.37),(4.86,4.59),(1.735,4.59),(1.735,3.845)])
R(gf180mcu_fd_sc_mcu9t5v0_, dualgate, [(-0.28,-0.28,32.2,5.32)])
R(gf180mcu_fd_sc_mcu9t5v0_, v5_xtor, [(0,0,31.92,5.04)])
R(gf180mcu_fd_sc_mcu9t5v0_, lvpwell, [(-0.43,-0.43,32.35,2.265)])
gf180mcu_fd_sc_mcu9t5v0_.add(gdstk.Label('EN', (0.84,2.52), layer=34, texttype=10))
gf180mcu_fd_sc_mcu9t5v0_.add(gdstk.Label('I', (8.68,2.52), layer=34, texttype=10))
gf180mcu_fd_sc_mcu9t5v0_.add(gdstk.Label('VDD', (15.96,5.49), layer=34, texttype=10))
gf180mcu_fd_sc_mcu9t5v0_.add(gdstk.Label('VSS', (15.96,-0.45), layer=34, texttype=10))
gf180mcu_fd_sc_mcu9t5v0_.add(gdstk.Label('Z', (23.24,1.4), layer=34, texttype=10))
gf180mcu_fd_sc_mcu9t5v0_.add(gdstk.Label('& Vendor GLOBALFOUNDRIES', (0,2), layer=63, texttype=63))
gf180mcu_fd_sc_mcu9t5v0_.add(gdstk.Label('& Product GF018hv5v_green_sc9', (0,1.5), layer=63, texttype=63))
gf180mcu_fd_sc_mcu9t5v0_.add(gdstk.Label('& Version 2015q2v2', (0,1), layer=63, texttype=63))
gf180mcu_fd_sc_mcu9t5v0_.add(gdstk.Label('& Metric 1.00', (0,0.5), layer=63, texttype=63))
gf180mcu_fd_sc_mcu9t5v0_.add(gdstk.Label('VNW', (0.345,3.92), layer=21, texttype=10))
gf180mcu_fd_sc_mcu9t5v0_.add(gdstk.Label('VPW', (0.34,-0.085), layer=204, texttype=10))

lib.write_gds('gf180mcu_fd_sc_mcu9t5v0__bufz_16.gds')
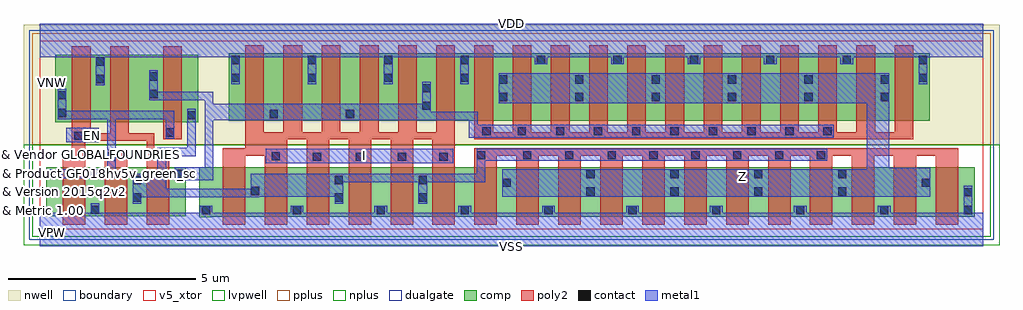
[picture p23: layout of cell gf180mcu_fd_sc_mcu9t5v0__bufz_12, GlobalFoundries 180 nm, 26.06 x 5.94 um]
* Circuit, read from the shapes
.subckt gf180mcu_fd_sc_mcu9t5v0__bufz_12 EN I VDD VNW VSS Z
XM1 VSS EN n1 VSUBS nfet_05v0 w=1.32u l=0.6u
XM2 n2 n1 VSS VSUBS nfet_05v0 w=1.32u l=0.6u
XM3 n3 EN n2 VSUBS nfet_05v0 w=1.32u l=0.6u
XM4 n2 I VSS VSUBS nfet_05v0 w=1.32u l=0.6u m=6
XM5 Z n2 VSS VSUBS nfet_05v0 w=1.32u l=0.6u m=12
XM6 VDD EN n1 VNW pfet_05v0 w=1.8u l=0.5u
XM7 n3 EN VDD VNW pfet_05v0 w=1.8u l=0.5u
XM8 n2 n1 n3 VNW pfet_05v0 w=1.8u l=0.5u
XM9 n3 I VDD VNW pfet_05v0 w=1.8u l=0.5u m=6
XM10 Z n3 VDD VNW pfet_05v0 w=1.8u l=0.5u m=12
.ends

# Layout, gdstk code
import gdstk
lib = gdstk.Library(unit=1e-6, precision=1e-09)
def R(c, l, rs):  # rectangles x0, y0, x1, y1
    for r in rs: c.add(gdstk.rectangle(r[:2], r[2:], *l))
def A(c, l, x, y, w, h, nx, ny, dx, dy):  # array of equal rectangles
    R(c, l, [(x+i*dx, y+j*dy, x+i*dx+w, y+j*dy+h) for i in range(nx) for j in range(ny)])
def P(c, l, *ps):  # polygons
    for p in ps: c.add(gdstk.Polygon(p, *l))
boundary = (0, 0)
nwell = (21, 0)
comp = (22, 0)
poly2 = (30, 0)
pplus = (31, 0)
nplus = (32, 0)
contact = (33, 0)
metal1 = (34, 0)
dualgate = (55, 0)
v5_xtor = (112, 1)
lvpwell = (204, 0)

gf180mcu_fd_sc_mcu9t5v0_ = lib.new_cell('gf180mcu_fd_sc_mcu9t5v0__bufz_12')
R(gf180mcu_fd_sc_mcu9t5v0_, boundary, [(0,0,25.2,5.04)])
R(gf180mcu_fd_sc_mcu9t5v0_, nwell, [(-0.43,2.265,25.63,5.47)])
R(gf180mcu_fd_sc_mcu9t5v0_, comp, [(0.18,0.345,3.9,1.665), (0.42,2.865,4.24,4.665), (5.05,2.9,23.77,4.7)])
P(gf180mcu_fd_sc_mcu9t5v0_, comp, [(4.26,0.33),(4.26,1.66),(24.97,1.66),(24.97,0.34),(4.59,0.34),(4.59,0.33)])
R(gf180mcu_fd_sc_mcu9t5v0_, poly2, [(1.74,0.125,2.34,2.125), (3.3,2.405,3.8,4.885)])
P(gf180mcu_fd_sc_mcu9t5v0_, poly2, [(0.62,0.125),(0.62,1.885),(0.86,1.885),(0.86,4.885),(1.36,4.885),(1.36,2.565),(1.88,2.565),(1.88,4.885),(2.38,4.885),(2.38,2.565),(3.06,2.565),(3.06,1.885),(3.46,1.885),(3.46,0.125),(2.86,0.125),(2.86,2.365),(1.22,2.365),(1.22,0.125)],
  [(4.89,0.12),(4.89,2.16),(5.49,2.16),(5.49,4.92),(5.99,4.92),(5.99,2.6),(6.51,2.6),(6.51,4.92),(7.01,4.92),(7.01,2.6),(7.53,2.6),(7.53,4.92),(8.03,4.92),(8.03,2.6),(8.55,2.6),(8.55,4.92),(9.05,4.92),(9.05,2.6),(9.57,2.6),(9.57,4.92),(10.07,4.92),(10.07,2.6),(10.59,2.6),(10.59,4.92),(11.09,4.92),(11.09,0.12),(10.49,0.12),(10.49,2.4),(9.97,2.4),(9.97,0.12),(9.37,0.12),(9.37,2.4),(8.85,2.4),(8.85,0.12),(8.25,0.12),(8.25,2.4),(7.73,2.4),(7.73,0.12),(7.13,0.12),(7.13,2.4),(6.61,2.4),(6.61,0.12),(6.01,0.12),(6.01,1.96),(5.49,1.96),(5.49,0.12)],
  [(11.61,2.4),(11.61,4.92),(12.11,4.92),(12.11,2.6),(12.63,2.6),(12.63,4.92),(13.13,4.92),(13.13,2.6),(13.65,2.6),(13.65,4.92),(14.15,4.92),(14.15,2.6),(14.67,2.6),(14.67,4.92),(15.17,4.92),(15.17,2.6),(15.69,2.6),(15.69,4.92),(16.19,4.92),(16.19,2.6),(16.71,2.6),(16.71,4.92),(17.21,4.92),(17.21,2.6),(17.73,2.6),(17.73,4.92),(18.23,4.92),(18.23,2.6),(18.75,2.6),(18.75,4.92),(19.25,4.92),(19.25,2.6),(19.77,2.6),(19.77,4.92),(20.27,4.92),(20.27,2.6),(20.79,2.6),(20.79,4.92),(21.29,4.92),(21.29,2.6),(21.81,2.6),(21.81,4.92),(22.31,4.92),(22.31,2.6),(22.83,2.6),(22.83,4.92),(23.33,4.92),(23.33,2.4)],
  [(11.61,0.12),(11.61,2.16),(24.53,2.16),(24.53,0.12),(23.93,0.12),(23.93,1.96),(23.41,1.96),(23.41,0.12),(22.81,0.12),(22.81,1.96),(22.29,1.96),(22.29,0.12),(21.69,0.12),(21.69,1.96),(21.17,1.96),(21.17,0.12),(20.57,0.12),(20.57,1.96),(20.05,1.96),(20.05,0.12),(19.45,0.12),(19.45,1.96),(18.93,1.96),(18.93,0.12),(18.33,0.12),(18.33,1.96),(17.81,1.96),(17.81,0.12),(17.21,0.12),(17.21,1.96),(16.69,1.96),(16.69,0.12),(16.09,0.12),(16.09,1.96),(15.57,1.96),(15.57,0.12),(14.97,0.12),(14.97,1.96),(14.45,1.96),(14.45,0.12),(13.85,0.12),(13.85,1.96),(13.33,1.96),(13.33,0.12),(12.73,0.12),(12.73,1.96),(12.21,1.96),(12.21,0.12)])
R(gf180mcu_fd_sc_mcu9t5v0_, pplus, [(-0.2,2.265,25.4,5.24)])
R(gf180mcu_fd_sc_mcu9t5v0_, nplus, [(-0.2,-0.2,25.4,2.265)])
A(gf180mcu_fd_sc_mcu9t5v0_, contact, 6.76, 0.41, 0.22, 0.22, 9, 1, 2.24, 0)
A(gf180mcu_fd_sc_mcu9t5v0_, contact, 14.6, 0.9, 0.22, 0.22, 4, 2, 2.24, 0.47)
A(gf180mcu_fd_sc_mcu9t5v0_, contact, 15.82, 2.51, 0.22, 0.22, 4, 1, 1.025, 0)
A(gf180mcu_fd_sc_mcu9t5v0_, contact, 12.26, 3.425, 0.22, 0.22, 6, 2, 2.04, 0.47)
A(gf180mcu_fd_sc_mcu9t5v0_, contact, 5.12, 3.94, 0.22, 0.22, 4, 1, 2.04, 0)
A(gf180mcu_fd_sc_mcu9t5v0_, contact, 5.12, 4.41, 0.22, 0.22, 10, 1, 2.04, 0)
R(gf180mcu_fd_sc_mcu9t5v0_, contact, [(4.33,0.4,4.55,0.62), (1.37,0.415,1.59,0.635), (2.49,0.74,2.71,0.96), (7.88,0.74,8.1,0.96), (10.12,0.74,10.34,0.96), (24.68,0.88,24.9,1.1), (5.64,0.915,5.86,1.135), (12.36,1.135,12.58,1.355), (23.56,1.135,23.78,1.355), (2.49,1.21,2.71,1.43), (7.88,1.21,8.1,1.43), (10.12,1.21,10.34,1.43), (0.25,1.375,0.47,1.595), (3.61,1.375,3.83,1.595), (7.295,1.83,7.515,2.05), (8.445,1.83,8.665,2.05), (9.565,1.83,9.785,2.05), (10.675,1.83,10.895,2.05), (1.81,1.835,2.03,2.055), (6.195,1.845,6.415,2.065), (11.68,1.87,11.9,2.09), (12.91,1.87,13.13,2.09), (14.035,1.87,14.255,2.09), (15.165,1.87,15.385,2.09), (16.28,1.87,16.5,2.09), (17.4,1.87,17.62,2.09), (18.515,1.87,18.735,2.09), (19.64,1.87,19.86,2.09), (20.755,1.87,20.975,2.09), (0.93,2.39,1.15,2.61), (3.37,2.475,3.59,2.695), (11.82,2.51,12.04,2.73), (12.765,2.51,12.985,2.73), (13.79,2.51,14.01,2.73), (14.8,2.51,15.02,2.73), (19.91,2.51,20.13,2.73), (20.93,2.51,21.15,2.73), (3.95,2.935,4.17,3.155), (6.14,2.97,6.36,3.19), (8.18,2.97,8.4,3.19), (0.49,3,0.71,3.22), (10.22,3.19,10.44,3.41), (0.49,3.47,0.71,3.69), (2.93,3.505,3.15,3.725), (10.22,3.66,10.44,3.88), (1.51,3.905,1.73,4.125), (23.48,3.94,23.7,4.16), (2.93,3.975,3.15,4.195), (1.51,4.375,1.73,4.595)])
R(gf180mcu_fd_sc_mcu9t5v0_, metal1, [(6.04,1.77,11.05,2.15), (0.71,2.33,1.575,2.71)])
P(gf180mcu_fd_sc_mcu9t5v0_, metal1, [(0.19,1.37),(0.19,1.6),(1.805,1.6),(1.805,2.94),(0.485,2.94),(0.485,3.75),(0.715,3.75),(0.715,3.17),(3.595,3.17),(3.595,2.415),(3.365,2.415),(3.365,2.94),(2.035,2.94),(2.035,1.37)],
  [(2.485,0.68),(2.485,1.49),(3.145,1.49),(3.145,2.185),(3.945,2.185),(3.945,3.215),(4.175,3.215),(4.175,1.955),(3.375,1.955),(3.375,1.085),(5.635,1.085),(5.635,1.49),(11.675,1.49),(11.675,2.15),(21.035,2.15),(21.035,1.83),(11.905,1.83),(11.905,1.26),(10.345,1.26),(10.345,0.68),(10.115,0.68),(10.115,1.26),(8.105,1.26),(8.105,0.68),(7.875,0.68),(7.875,0.865),(5.865,0.865),(5.865,0.855),(2.715,0.855),(2.715,0.68)],
  [(3.605,1.315),(3.605,1.655),(4.405,1.655),(4.405,3.445),(2.925,3.445),(2.925,4.255),(3.155,4.255),(3.155,3.675),(4.635,3.675),(4.635,3.36),(10.215,3.36),(10.215,3.94),(10.445,3.94),(10.445,3.14),(11.695,3.14),(11.695,2.79),(21.21,2.79),(21.21,2.45),(11.465,2.45),(11.465,2.91),(4.635,2.91),(4.635,1.315)],
  [(12.355,0.865),(12.355,1.6),(22.08,1.6),(22.08,3.365),(12.255,3.365),(12.255,4.175),(22.685,4.175),(22.685,1.65),(23.785,1.65),(23.785,0.865)],
  [(0,-0.45),(0,0.45),(1.365,0.45),(1.365,0.695),(1.595,0.695),(1.595,0.45),(4.27,0.45),(4.27,0.625),(4.61,0.625),(4.61,0.45),(6.7,0.45),(6.7,0.635),(7.04,0.635),(7.04,0.45),(8.94,0.45),(8.94,0.635),(9.28,0.635),(9.28,0.45),(11.18,0.45),(11.18,0.635),(11.52,0.635),(11.52,0.45),(13.42,0.45),(13.42,0.635),(13.76,0.635),(13.76,0.45),(15.66,0.45),(15.66,0.635),(16,0.635),(16,0.45),(17.9,0.45),(17.9,0.635),(18.24,0.635),(18.24,0.45),(20.14,0.45),(20.14,0.635),(20.48,0.635),(20.48,0.45),(22.38,0.45),(22.38,0.635),(22.72,0.635),(22.72,0.45),(24.675,0.45),(24.675,1.16),(24.905,1.16),(24.905,0.45),(25.2,0.45),(25.2,-0.45)],
  [(1.505,3.845),(1.505,4.59),(0,4.59),(0,5.49),(25.2,5.49),(25.2,4.59),(23.705,4.59),(23.705,3.88),(23.475,3.88),(23.475,4.59),(21.72,4.59),(21.72,4.405),(21.38,4.405),(21.38,4.59),(19.68,4.59),(19.68,4.405),(19.34,4.405),(19.34,4.59),(17.64,4.59),(17.64,4.405),(17.3,4.405),(17.3,4.59),(15.6,4.59),(15.6,4.405),(15.26,4.405),(15.26,4.59),(13.56,4.59),(13.56,4.405),(13.22,4.405),(13.22,4.59),(11.465,4.59),(11.465,3.88),(11.235,3.88),(11.235,4.59),(9.425,4.59),(9.425,3.88),(9.195,3.88),(9.195,4.59),(7.385,4.59),(7.385,3.88),(7.155,3.88),(7.155,4.59),(5.345,4.59),(5.345,3.88),(5.115,3.88),(5.115,4.59),(1.735,4.59),(1.735,3.845)])
R(gf180mcu_fd_sc_mcu9t5v0_, dualgate, [(-0.28,-0.28,25.48,5.32)])
R(gf180mcu_fd_sc_mcu9t5v0_, v5_xtor, [(0,0,25.2,5.04)])
R(gf180mcu_fd_sc_mcu9t5v0_, lvpwell, [(-0.43,-0.43,25.63,2.265)])
gf180mcu_fd_sc_mcu9t5v0_.add(gdstk.Label('EN', (1.4,2.52), layer=34, texttype=10))
gf180mcu_fd_sc_mcu9t5v0_.add(gdstk.Label('I', (8.68,1.96), layer=34, texttype=10))
gf180mcu_fd_sc_mcu9t5v0_.add(gdstk.Label('VDD', (12.6,5.49), layer=34, texttype=10))
gf180mcu_fd_sc_mcu9t5v0_.add(gdstk.Label('VSS', (12.6,-0.45), layer=34, texttype=10))
gf180mcu_fd_sc_mcu9t5v0_.add(gdstk.Label('Z', (18.76,1.4), layer=34, texttype=10))
gf180mcu_fd_sc_mcu9t5v0_.add(gdstk.Label('& Vendor GLOBALFOUNDRIES', (0,2), layer=63, texttype=63))
gf180mcu_fd_sc_mcu9t5v0_.add(gdstk.Label('& Product GF018hv5v_green_sc9', (0,1.5), layer=63, texttype=63))
gf180mcu_fd_sc_mcu9t5v0_.add(gdstk.Label('& Version 2015q2v2', (0,1), layer=63, texttype=63))
gf180mcu_fd_sc_mcu9t5v0_.add(gdstk.Label('& Metric 1.00', (0,0.5), layer=63, texttype=63))
gf180mcu_fd_sc_mcu9t5v0_.add(gdstk.Label('VNW', (0.345,3.92), layer=21, texttype=10))
gf180mcu_fd_sc_mcu9t5v0_.add(gdstk.Label('VPW', (0.34,-0.085), layer=204, texttype=10))

lib.write_gds('gf180mcu_fd_sc_mcu9t5v0__bufz_12.gds')
